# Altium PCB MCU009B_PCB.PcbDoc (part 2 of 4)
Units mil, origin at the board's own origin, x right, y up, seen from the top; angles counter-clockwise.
Board outline 2657.23 x 2215.46 mil, 10 copper layers (Top Layer, Internal-Plane 2, Mid-Layer 3, Mid-Layer 4, Internal-Plane 5, Internal-Plane 6, Mid-Layer 7, Mid-Layer 8, Internal-Plane 9, Bottom Layer), stack 60.8 mil thick; 232 components, 196 nets, 851 pads, 493 vias.

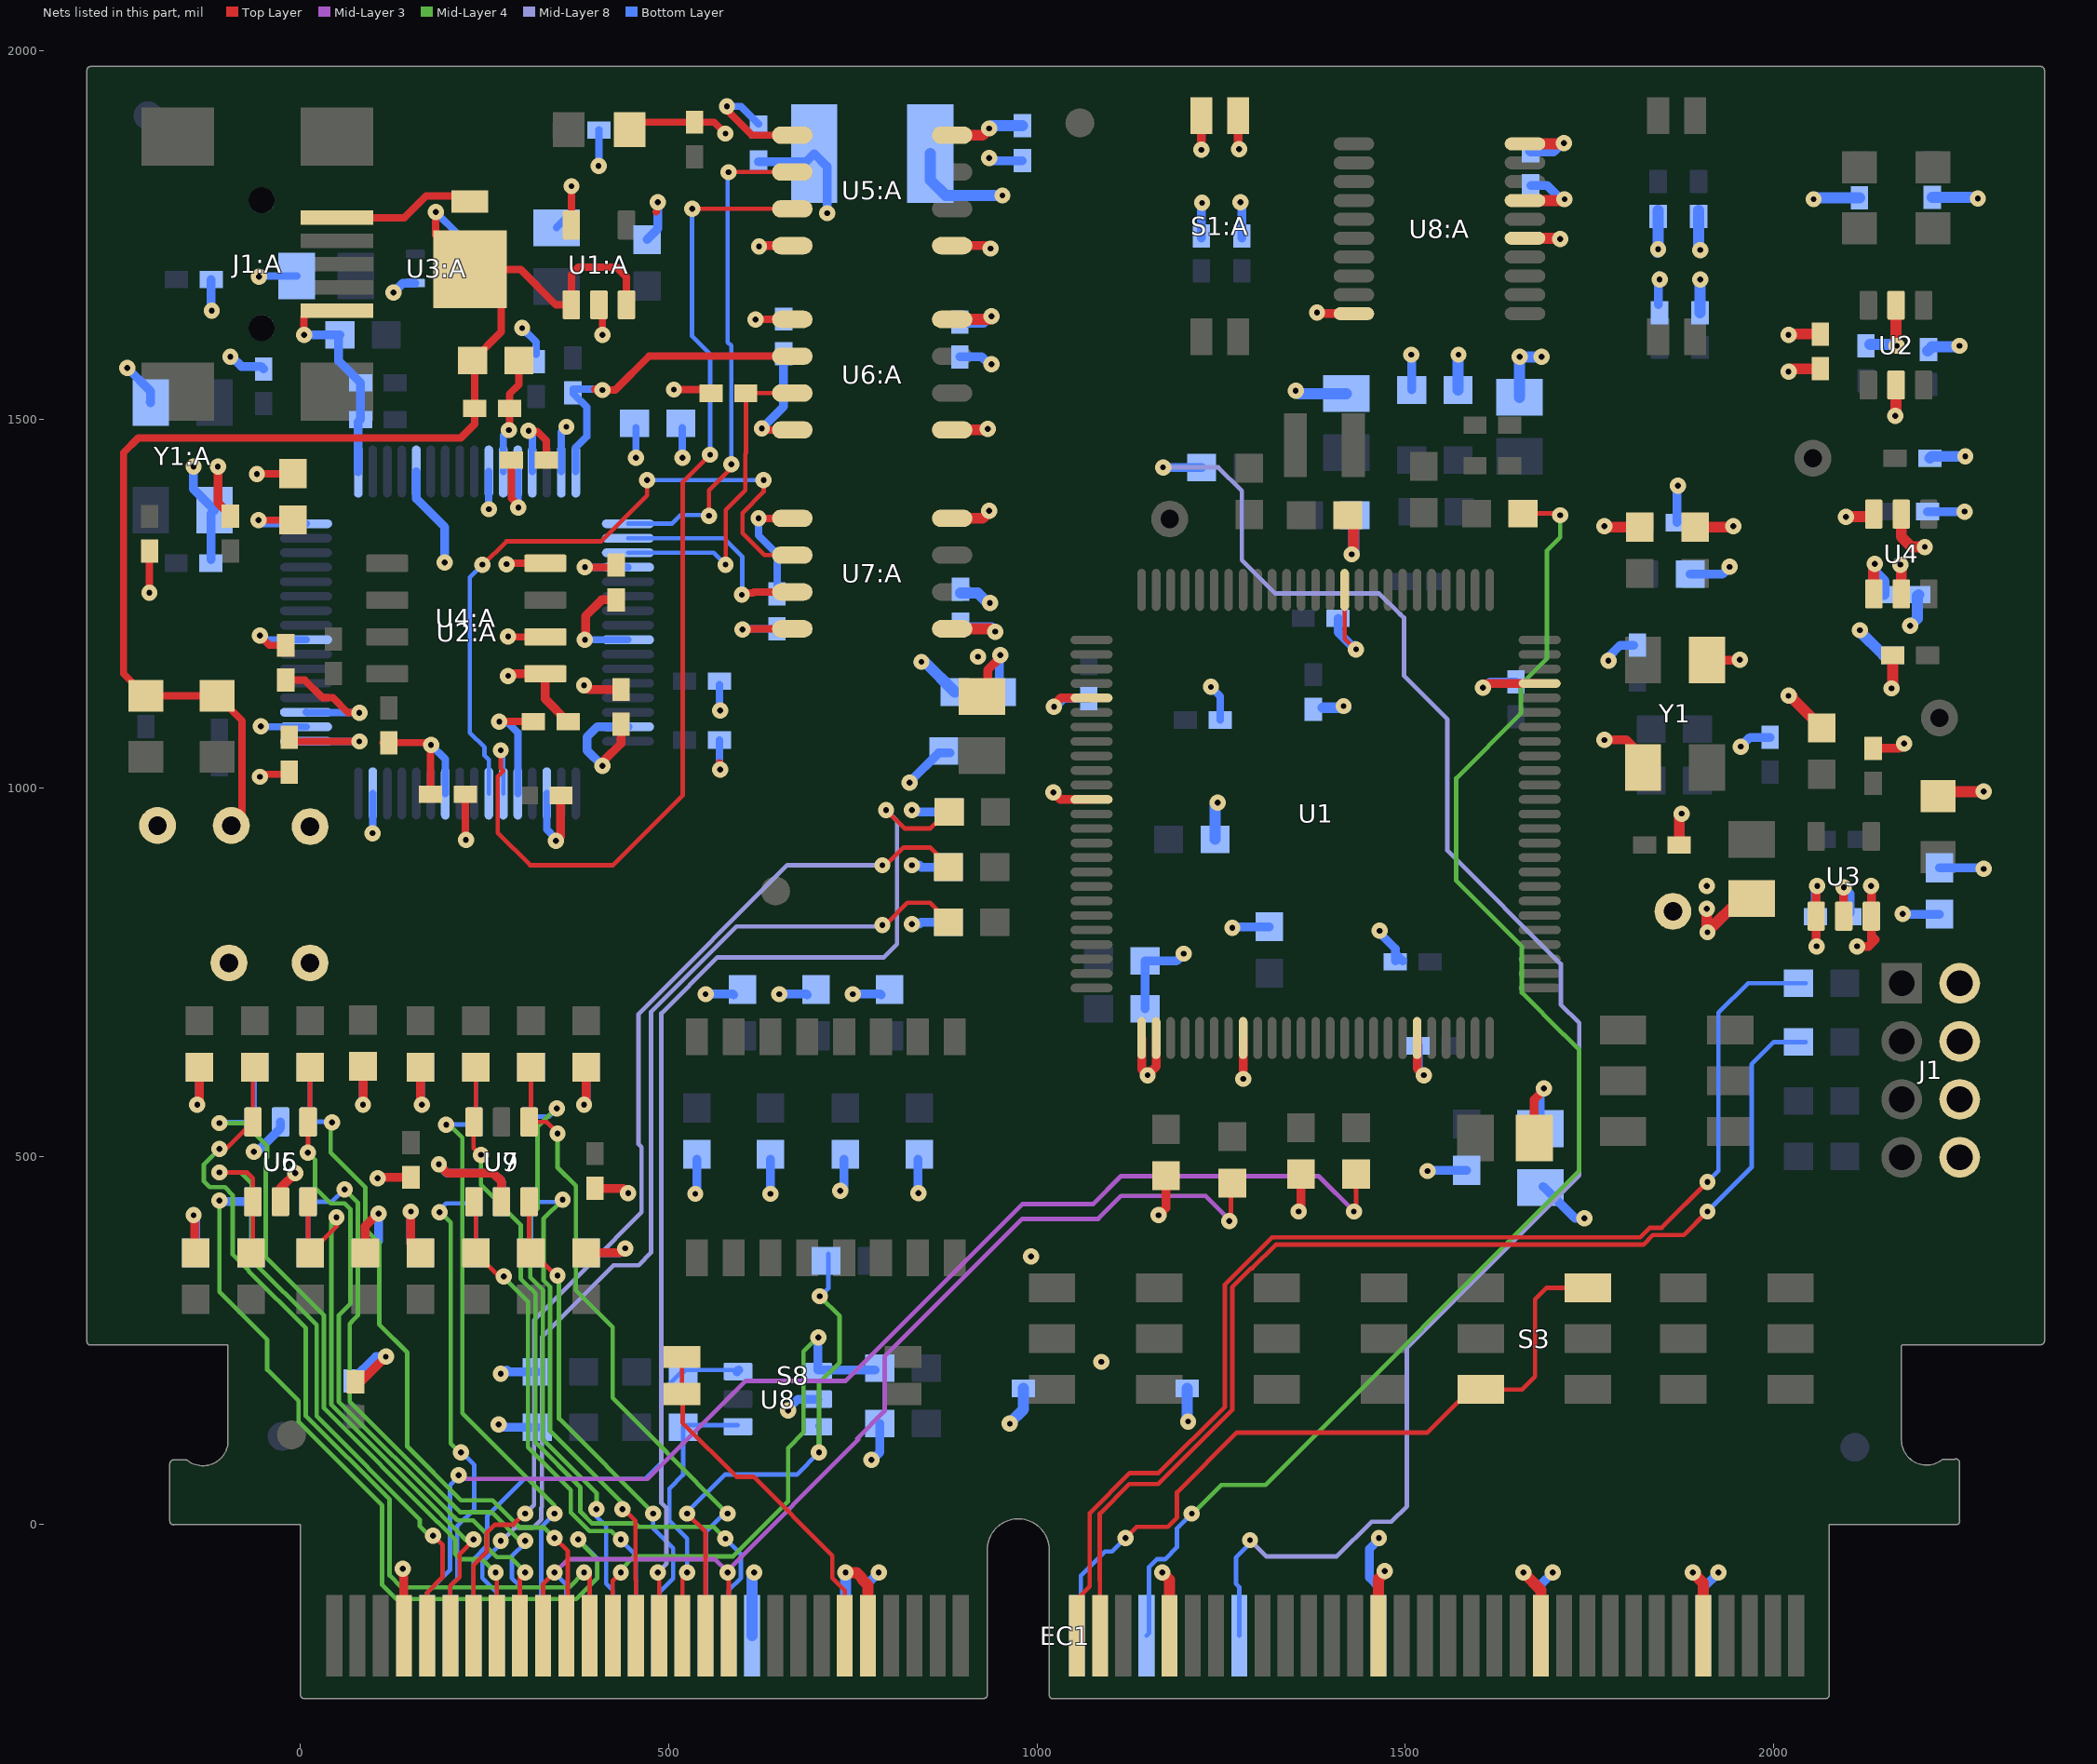
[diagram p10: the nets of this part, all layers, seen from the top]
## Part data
C1 C2 C8 C20 C21 C24 C27: library part CMP-0007318-5, "CAP, CERM, 10 uF, 10 V, +/- 20%, X5R, 0603", Cap_Case=0603, Manufacturer=MuRata, TempCo=X5R, Tolerance_%=20%, Value1=Unknown, Value2=10V, ValueDisplayed=10uF
C1:A C3 C4 C5 C6 C6:A C7:A C8:A C9 C9:A C10:A C11:A C12:A C14 C14:A C15 C16 C16:A C17 C18 C19:A C20:A C21:A C22:A C23:A C24:A C25 C25:A C31 C32 C33: library part CMP-0006629-2, "CAP, CERM, 0.1 uF, 10 V, +/- 10%, X7R, 0402", Cap_Case=0402, Manufacturer=MuRata, Supplier Part Number 1=GRM155R71A104KA01D-ND, TempCo=X7R, Tolerance_%=10%, Value1=Unknown, Value2=10V, ValueDisplayed=0.1uF
C2:A C3:A C5:A C13:A C15:A: library part CMP-0007312-5, "CAP, CERM, 4.7 uF, 6.3 V, +/- 20%, X5R, 0603", Cap_Case=0603, Manufacturer=MuRata, Supplier Part Number 1=490-5421-1-ND, TempCo=X5R, Tolerance_%=20%, Value1="0.001 ohm", Value2=6.3V, ValueDisplayed=4.7uF
C4:A C26 C29 C30: library part CMP-0006639-2, "CAP, CERM, 0.01 uF, 16 V, +/- 10%, X7R, 0402", Cap_Case=0402, Manufacturer=MuRata, Supplier Part Number 1=490-1313-1-ND, TempCo=X7R, Tolerance_%=10%, Value1=Unknown, Value2=16V, ValueDisplayed=0.01uF
C7: library part CMP-0008285-2, "CAP, CERM, 10 uF, 10 V, +/- 10%, X5R, 0805", Cap_Case=0805, Manufacturer=MuRata, Supplier Part Number 1=490-1709-1-ND, TempCo=X5R, Tolerance_%=10%, Value1="0.002 ohm", Value2=10V, ValueDisplayed=10uF
C10 C11 C12 C13 C19 C60 C61: library part CMP-0007323-5, "CAP, CERM, 2.2 uF, 10 V, +/- 10%, X5R, 0603", Cap_Case=0603, Manufacturer=MuRata, Supplier Part Number 1=490-1545-1-ND, TempCo=X5R, Tolerance_%=10%, Value1=Unknown, Value2=10V, ValueDisplayed=2.2uF
C17:A C18:A: library part CMP-0006443-2, "CAP, CERM, 27 pF, 50 V, +/- 5%, C0G/NP0, 0402", Cap_Case=0402, Manufacturer=MuRata, Supplier Part Number 1=14T3294, TempCo=C0G/NP0, Tolerance_%=5%, Value1=Unknown, Value2=50V, ValueDisplayed=27pF
C22 C23: library part CMP-0006420-2, "CAP, CERM, 15 pF, 50 V, +/- 5%, C0G/NP0, 0402", Cap_Case=0402, Manufacturer=MuRata, Supplier Part Number 1=81-GRM1555C1H150JA1D, TempCo=C0G/NP0, Tolerance_%=5%, Value1=Unknown, Value2=50V, ValueDisplayed=15pF
C26:A: library part CMP-0009297-2, "CAP, CERM, 0.01 uF, 1500 V, +/- 10%, X7R, 1812", Cap_Case=1812, Manufacturer=AVX, Supplier Part Number 1=478-4735-1-ND, TempCo=X7R, Tolerance_%=10%, Value1="0.05 ohm", Value2=1500V, ValueDisplayed=0.01uF
C28: library part CMP-0006638-2, "CAP, CERM, 1000 pF, 16 V, +/- 10%, X7R, 0402", Cap_Case=0402, Manufacturer=MuRata, Supplier Part Number 1=GRM155R71C102KA01D-ND, TempCo=X7R, Tolerance_%=10%, Value1=Unknown, Value2=16V, ValueDisplayed=1000pF
C34 C35 C36 C37 C38 C39 C40: library part CMP-0007209-4, "CAP, CERM, 330 pF, 50 V, +/- 5%, C0G/NP0, 0603", Cap_Case=0603, Manufacturer=MuRata, Supplier Part Number 1=490-1439-1-ND, TempCo=C0G/NP0, Tolerance_%=5%, Value1=Unknown, Value2=50V, ValueDisplayed=330pF
C41 C42 C43 C44 C45 C46 C47 C48 C49 C50 C51 C52 C53 C54 C55 C56 C57 C58 C59: library part CMP-0007378-5, "CAP, CERM, 0.1 uF, 16 V, +/- 10%, X7R, 0603", Cap_Case=0603, Manufacturer=MuRata, Supplier Part Number 1=490-1532-1-ND, TempCo=X7R, Tolerance_%=10%, Value1=Unknown, Value2=16V, ValueDisplayed=0.1uF
D1 D2:A: library part CMP-0002960-2, "LED, Bright Green, SMD", Color="Bright Green", Manufacturer="Wurth Elektronik", Power_TotalModule=72mW, Supplier Part Number 1=732-4986-1-ND, Value1=0.072W, Value2=2V
D1:A: library part CMP-0028747-1, "Diode, Schottky, 10 V, 1 A, AEC-Q101, POWERMITE", Manufacturer="ON Semiconductor", Supplier Part Number 1=MBRM110ET1GOSCT-ND, Value1=1A, Value2=0.53V
D2 D3: library part CMP-0002951-2, "LED, Red, SMD", Color=Red, Manufacturer="Wurth Elektronik", Power_TotalModule=72mW, Supplier Part Number 1=732-4985-1-ND, Value1=0.072W, Value2=1.9V
D3:A D4:A: library part CMP-0002959-2, "LED, Blue, SMD", Color=Blue, Manufacturer="Wurth Elektronik", Power_TotalModule=105mW, Supplier Part Number 1=732-4982-1-ND, Value1=0.105W, Value2=3.2V
EC1: library part CMP-0003813-2, "C2000 controlCARD-120HSEC Edge Connector for Samtec HSEC8-160-01-L-DV-A-BL", Manufacturer=Any
FID1 FID2 FID3 FID4 FID5 FID6: library part CMP-0077181-1, "Fiducial mark.  There is nothing to buy or mount.", Manufacturer=N/A
J1: library part CMP-0055568-1, "Header, 2mm, 4x2, Tin, TH", Color=Black, Current_A=3.2A, Manufacturer=Samtec, Supplier Part Number 1=SAM1177-04-ND
J1:A: library part CMP-0054809-1, "Connector, Receptacle, USB Mini B 2.0, SMT", Color=Black, Current_A=1A, Manufacturer="Wurth Elektronik", Supplier Part Number 1=732-2109-1-ND, Voltage_V=30V
L1: library part CMP-0003363-1, "Ferrite Bead, 220 ohm @ 100 MHz, 2 A, 0805", Manufacturer=MuRata, Supplier Part Number 1=490-1054-1-ND, Value1="0.045 ohm", Value2=2A, ValueDisplayed="220 ohm"
L1:A L2:A: library part CMP-0003398-1, "Ferrite Bead, 600 ohm @ 100 MHz, 0.5 A, 0805", Manufacturer="Laird-Signal Integrity Products", Supplier Part Number 1=240-2399-1-ND, Value1="0.3 ohm", Value2=0.5A, ValueDisplayed="600 ohm"
L2: library part CMP-0003306-1, "Ferrite Bead, 60 ohm @ 100 MHz, 3 A, 0805", Manufacturer="Taiyo Yuden", Supplier Part Number 1=587-1932-1-ND, Value1="0.025 ohm", Value2=3A, ValueDisplayed="60 ohm"
L3: library part CMP-0058752-1, "Inductor, Multilayer, Ferrite, 2.2 uH, 1.3 A, 0.08 ohm, SMD", Manufacturer=MuRata, Supplier Part Number 1=490-5114-1-ND, Value1="0.08 ohm", Value2=1.3A, ValueDisplayed=2.2uH
Logo1: library part CMP-0074838-1, "Texas Instrument Corporate Signature"
Logo2: library part CMP-0074769-1
Logo3: library part CMP-0074847-1, "FCC_disclaimer"
LOGO4: library part CMP-0074844-1
R1 R2: library part CMP-0026938-5, "RES, 4.7 k, 5%, 0.063 W, AEC-Q200 Grade 0, 0402", Manufacturer=Vishay-Dale, Power_W=63mW, Supplier Part Number 1=541-4.7KJCT-ND, TempCo="200 ppm/C", Tolerance_%=5%, Value2=0.063W, Value_Code=4k70, ValueDisplayed=4.7k
R1:A R10 R11 R23: library part CMP-0026962-3, "RES, 680, 5%, 0.063 W, AEC-Q200 Grade 0, 0402", Manufacturer=Vishay-Dale, Power_W=63mW, Supplier Part Number 1=541-680JCT-ND, TempCo="200 ppm/C", Tolerance_%=5%, Value2=0.063W, Value_Code=680R, ValueDisplayed=680
R2:A R4:A R8 R9 R9:A R15:A R16:A: library part CMP-0026825-5, "RES, 10 k, 5%, 0.063 W, AEC-Q200 Grade 0, 0402", Manufacturer=Vishay-Dale, Power_W=63mW, Supplier Part Number 1=541-10KJCT-ND, TempCo="200 ppm/C", Tolerance_%=5%, Value2=0.063W, Value_Code=10k0, ValueDisplayed=10k
R3 R4 R5 R6 R7 R16 R17 R18 R19 R21 R22 R28 R32 R35 R36 R37 R38 R39 R40 R41 R42 R43 R44 R45 R46 R47 R48 R49 R50 R51 R52 R53 R54 R55 R56 R57 R58 R59 R60 R61 R62 R63 R64: library part CMP-0025697-4, "RES, 0, 5%, 0.1 W, AEC-Q200 Grade 0, 0603", Manufacturer=Vishay-Dale, Power_W=100mW, Supplier Part Number 1=541-0.0GCT-ND, TempCo="200 ppm/C", Tolerance_%=5%, Value2=0.1W, Value_Code=0000, ValueDisplayed=0
R3:A R6:A R12:A R13:A R29: library part CMP-0026822-3, "RES, 0, 5%, 0.063 W, AEC-Q200 Grade 0, 0402", Manufacturer=Vishay-Dale, Power_W=63mW, Supplier Part Number 1=541-0.0JCT-ND, TempCo="200 ppm/C", Tolerance_%=5%, Value2=0.063W, Value_Code=0000, ValueDisplayed=0
R5:A R7:A R8:A R11:A: library part CMP-0026852-3, "RES, 1.0 k, 5%, 0.063 W, AEC-Q200 Grade 0, 0402", Manufacturer=Vishay-Dale, Power_W=63mW, Supplier Part Number 1=541-1.0KJCT-ND, TempCo="200 ppm/C", Tolerance_%=5%, Value2=0.063W, Value_Code=1k00, ValueDisplayed=1.0k
R10:A R27 R30 R31 R33 R34: library part CMP-0026890-5, "RES, 2.2 k, 5%, 0.063 W, AEC-Q200 Grade 0, 0402", Manufacturer=Vishay-Dale, Power_W=63mW, Supplier Part Number 1=541-2.2KJCT-ND, TempCo="200 ppm/C", Tolerance_%=5%, Value2=0.063W, Value_Code=2k20, ValueDisplayed=2.2k
R12 R13: library part CMP-0026826-2, "RES, 10 M, 5%, 0.063 W, AEC-Q200 Grade 0, 0402", Manufacturer=Vishay-Dale, Power_W=63mW, Supplier Part Number 1=541-10MJCT-ND, TempCo="200 ppm/C", Tolerance_%=5%, Value2=0.063W, Value_Code=10M0, ValueDisplayed=10M
R14 R15 R20: library part CMP-0020442-3, "RES, 0, 5%, 0.125 W, AEC-Q200 Grade 0, 0805", Manufacturer=Vishay-Dale, Power_W=125mW, Supplier Part Number 1=541-0.0ACT-ND, TempCo="200 ppm/C", Tolerance_%=5%, Value2=0.125W, Value_Code=0000, ValueDisplayed=0
R14:A: library part CMP-0026834-3, "RES, 12 k, 5%, 0.063 W, AEC-Q200 Grade 0, 0402", Manufacturer=Vishay-Dale, Power_W=63mW, Supplier Part Number 1=541-12KJCT-ND, TempCo="200 ppm/C", Tolerance_%=5%, Value2=0.063W, Value_Code=12k0, ValueDisplayed=12k
R24: library part CMP-0026129-2, "RES, 1.00, 1%, 0.063 W, AEC-Q200 Grade 0, 0402", Manufacturer=Vishay-Dale, Power_W=63mW, Supplier Part Number 1=541-1.00LLCT-ND, TempCo="100 ppm/C", Tolerance_%=1%, Value2=0.063W, Value_Code=1R00, ValueDisplayed=1.00
R25 R26: library part CMP-0026949-3, "RES, 56 k, 5%, 0.063 W, AEC-Q200 Grade 0, 0402", Manufacturer=Vishay-Dale, Power_W=63mW, Supplier Part Number 1=541-56KJCT-ND, TempCo="200 ppm/C", Tolerance_%=5%, Value2=0.063W, Value_Code=56k0, ValueDisplayed=56k
S1 S1:A S8: library part CMP-0002230-1, "Switch, SPST, 2 Pos, 25mA, 24VDC, SMD", CurrentRating_mA=25A, Manufacturer="CTS Electrocomponents", Supplier Part Number 1=CT2182LPST-ND
S2 S3 S4: library part CMP-0002123-2, "SLIDE SWITCH DPDT  .1A, SMT", CurrentRating_mA=100A, Manufacturer="Copal Electronics", Supplier Part Number 1=CAS220JCT-ND
S5 S6: library part CMP-0002233-1, "Switch, Dual SPDT,  2 Pos, 0.1A, 6VDC, SMD", CurrentRating_mA=100A, Manufacturer="Copal Electronics", Supplier Part Number 1=CASD20JCT-ND
S7: library part CMP-0002229-1, "Switch, SPST, 8 Pos, 25mA, 24VDC, SMD", CurrentRating_mA=25A, Manufacturer="CTS Electrocomponents", Supplier Part Number 1=CT2188LPST-ND
TP1 TP1:A TP2 TP2:A TP3 TP3:A TP4 TP5 TP6: library part CMP-0078143-2, "TEST POINT.  No entry in BOM.", Manufacturer=N/A
U1: library part CMP-0078352-1, "Piccolo Microcontroller, PZ0100A (LQFP-100)", Alternate Manufacturer="Texas Instruments"
U1:A: library part CMP-0073823-1, "Low-Noise, High PSRR, RF 200-mA Low-Dropout Linear Regulators, DBV0005A (SOT-23-5)", Alternate Manufacturer="Texas Instruments", Alternate PartNumber=TPS73033DBVT
U2: library part CMP-0051789-2, "Dual Buffer/Driver with Open-Drain Output, DBV0006A, LARGE T&R", F @ Nom Voltage(Max)(Mhz)=150, Generic Part Number=SN74LVC2G07, ICC @ Nom Voltage(Max)(mA)=0.01, Manufacturer="Texas Instruments", Operating Temperature Range(C)="-40 to 125", Rating=Catalog, tpd @ Nom Voltage(Max)(ns)=8.6,4.4,3.7,2.9, Voltage(Nom)(V)=1.8,2.5,3.3,5
U2:A: library part CMP-0004796-1, "Dual High Speed USB To Multipurpose UART/FIFO IC, LQFP-64", Manufacturer=FTDI, Supplier Part Number 1=768-1024-1-ND
U3: library part CMP-0036866-2, "Single Output Low Noise LDO, 400 mA, Fixed 3.3 V Output, 1.7 to 5.5 V Input, with Reverse Current Protection, 5-pin SOT-23 (DBV), -40 to 85 degC, Green (RoHS & no Sb/Br)", Alternate Manufacturer="Texas Instruments", Alternate PartNumber=TPS73633DBVT, Rating=Catalog
U3:A: library part CMP-0043096-2, "Low-Capacitance + / - 15 kV ESD-Protection Array for High-Speed Data Interfaces, 2 Channels, -40 to +85 degC, 5-pin SOT (DRL), Green (RoHS & no Sb/Br)", Breakdown Voltage(Min)(V)=11, IO Capacitance(Typ)(pF)=1.5, IO Leakage Current(nA)=1, Manufacturer="Texas Instruments"
U4: library part CMP-0067340-2, "High-Accuracy, Fixed-Threshold OV/UV Monitor, DDC0006A (SOT-23-T-6)", Alternate Manufacturer="Texas Instruments", Alternate PartNumber=TPS3702CX33DDCT
U4:A: library part CMP-0005261-2, "2K Microwire Compatible Serial EEPROM, SOIC-8", Manufacturer=Microchip, Supplier Part Number 1=93LC56C-I/SN-ND
U5 U6 U7 U8 U9: library part CMP-0066599-1, "Automotive Low-Capacitance 4-Channel +/-15-kV ESD Protection Array for High-Speed Data Interfaces, DBV0006A (SOT-23-6)", Alternate Manufacturer="Texas Instruments"
U5:A U6:A U7:A: library part CMP-0029375-1, "25 Mbps Dual Channels, 2 / 0, Digital Isolator, 3.3 V / 5 V, -40 to +125 degC, 8-pin SOIC (D), Green (RoHS & no Sb/Br)", Insulation Rating(VRMS)=2500, Manufacturer="Texas Instruments", Rating=Catalog, Supply Voltage(s)(V)="3.3, 5"
U8:A: library part CMP-0047070-3, "Octal Buffer/Driver With 3-State OUtputs, PW0020A (TSSOP-20)", Alternate Manufacturer="Texas Instruments", Alternate PartNumber=SN74ALVC244PW, F @ Nom Voltage(Max)(Mhz)=100, Generic Part Number=SN74ALVC244, ICC @ Nom Voltage(Max)(mA)=0.024, Operating Temperature Range(C)="-40 to 85", Rating=Catalog, tpd @ Nom Voltage(Max)(ns)=4.4,3.1,2.8, Voltage(Nom)(V)=1.8,2.5,2.7,3.3
Y1: library part CMP-0080365-1, "Crystal, 20 MHz, 25 ppm, 18, SMD", Frequency Stability="30 ppm", Frequency Tolerance="25 ppm", Load Capacitance=18, Manufacturer="ECS Inc.", PartNumber=ECS-200-18-30B-AGN-TR, Supplier Part Number 1=XC2693CT-ND
Y1:A: library part CMP-0004646-3, "Crystal, 12 MHz, 20pF, SMD", Frequency Stability=+/-50ppm, Manufacturer="ECS Inc.", PartNumber=ECS-120-20-30B-TR, Supplier Part Number 1=XC1118CT-ND
ZZ1: library part CMP-0077236-1
ZZ2: library part CMP-0077237-1
ZZ3: library part CMP-0077238-1

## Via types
v1: diameter 22, hole 8, Top Layer to Bottom Layer, 414 vias
v2: diameter 22, hole 8, Top Layer to Bottom Layer, tented both sides, 79 vias

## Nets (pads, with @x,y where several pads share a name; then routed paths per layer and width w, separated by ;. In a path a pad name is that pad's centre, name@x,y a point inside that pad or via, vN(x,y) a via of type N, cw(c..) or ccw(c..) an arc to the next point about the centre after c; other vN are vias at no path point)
3V3: C7.2 C9.1 C10.2 C19.2 C20:A.1 C22:A.1 C24:A.1 C25:A.2 C31.1 L1.1 L2.1 R1.1 R2.2 R8.2 R9.2 R10.1 R11.1 R12.2 R13.2 R14.1 R15:A.2 R16:A.2 R20.2 R25.1 R26.2 R27.2 R28.2 R30.2 R31.2 TP2.1 U2.5 U4.3 U4.4 U4.5 U5:A.8 U6:A.8 U7:A.1 U8:A.20 | length 1989.6
  Top Layer w12: R1.1@75,193.62 81.62,193.62 v1(116,228) v1@118,230 ; L2.1@933.1,1127.4 933.1,1160.1 v1@949,1176 ; L1.1@1675,525 1675,577 v1@1689,591
  Top Layer w15: U7:A.1@883.5,1215.87 936.13,1215.87 v1@938,1214 ; U6:A.8@883.5,1635.87 933.87,1635.87 v1(938,1640) ; U5:A.8@883.5,1885.87 925.87,1885.87 v1(935,1895) ; U8:A.20@1662.34,1874 1714,1874 v1(1715,1875) ; R31.2@1871.72,922.4 1871.72,961.72 v1(1875,965) ; R28.2@1893.1,1353.9 v1@1944,1353.9 ; v1(1909,836) 1909,806 v1@1910,805 ; v1(1910,804) v1@1910,805 ; v1@1944,1356 v1(1945,1355) ; v1@1945,1353.9 1945.9,1353.9 v1@1946,1354 ; R20.2@1970,850 1955,850 v1@1910,805 ; v1(2020,1615) 2021.02,1616.02 C9.1@2063.1,1616.02 ; v1(2098,1368) 2135,1368 U4.3@2135.7,1368.7 ; U4.4@2135.7,1263.27 2135.7,1302.7 2136,1303 v1@2137,1303 ; U4.3@2135.7,1371.53 U4.3@2135.7,1368.7 ; U4.3@2137,1370 U4.3@2135.7,1368.7 ; U2.5@2165.91,1655 2165.91,1603.09 v1@2167,1602 ; v1(2172,1303) 2173.1,1301.9 U4.5@2173.1,1263.27
  Bottom Layer w12: R2.2@70.2,195.28 70,195.47 102.53,228 v1(116,228) ; v1@949,1180 949,1144 946,1141 C10.2@949.6,1137.4 ; R15:A.2@1223.1,1746.02 1223.1,1748.02 1223.1,1793.1 v1(1224,1794) ; v1(1276,1795) 1278.1,1792.9 1278.1,1748.02 R16:A.2@1278.1,1746.02 ; C7.2@1683.1,537.4 1683.1,587.1 v1(1688,592)
  Bottom Layer w15: C22:A.1@895,1632.24 927.24,1632.24 935,1640 v1(938,1640) ; C24:A.1@896.22,1217.24 937.76,1217.24 v1(943,1212) ; v1(935,1895) 938.62,1898.62 C20:A.1@980,1898.62 ; v1@962,137 981.38,156.38 R8.2@981.38,185 ; R9.2@1203.62,185 1203.62,141.38 v1(1205,140) ; C19.2@1571.5,1540 1571.5,1587.5 v1(1572,1588) ; R14.1@1655,1530 v1(1655,1585) v1@1684,1585 ; C25:A.2@1670,1864.62 1700.62,1864.62 v1@1710,1874 ; v1@1842,1727 1843.1,1728.1 1843.1,1776.78 R25.1@1843.1,1783.78 ; R26.2@1898.1,1783.78 1898.1,1776.78 1898.1,1731.9 v1(1900,1730) ; v1(2054,1799) 2055.86,1800.86 R10.1@2116.34,1800.85 ; v1@2115,1214 2149,1180 R30.2@2161.38,1180 ; R12.2@2130.23,1601.79 2165.21,1601.79 v1(2167,1600) ; v1@2137,1303 2137,1293 2149.48,1280.52 C31.1@2149.48,1262.4 ; R13.2@2209,1593 2214.62,1598.62 2250.62,1598.62 v1(2252,1600) ; R27.2@2211.72,1447.4 2214.32,1450 v1(2260,1450) ; R11.1@2215.08,1801.37 2275.63,1801.37 v1(2277,1800)
  other v1: 963,137 1909,867 920,1178 950,1180 2117,1214 2137,1304 1685,1585 1843,1731
EMU_1V8: C5:A.2 C6:A.2 C7:A.2 C8:A.2 U2:A.12 U2:A.37 U2:A.49 U2:A.64 | length 609.2
  Top Layer w10: v2(-56.72,1363.35) C5:A.2@-19.8,1363.35 ; C7:A.2@-17.19,1065.68 -14.33,1062.82 62.58,1062.82 ; 7.72,1063.23 62.17,1063.23 62.58,1062.82 ; v2(80,1063) 62.77,1063 62.58,1062.82 ; v2(270,1090) C8:A.2@316.38,1090 ; C6:A.2@286.57,1444.84 286.57,1393.06 295.88,1383.75 v2(295.88,1380.55) v2@295.12,1381.31
  Bottom Layer w10: v2(-56.72,1363.35) -55.68,1364.38 -55.68,1361.68 -52.5,1358.5 U2:A.64@7.72,1358.5 ; U2:A.49@7.72,1063.23 79.77,1063.23 v2(80,1063) ; v2(270,1090) 280,1090 295.12,1074.88 U2:A.37@295.12,992.36 ; v2@295.12,1381.31 U2:A.12@295.12,1429.37
EMU_3V3: C2:A.1 C9:A.2 C10:A.2 C11:A.2 C12:A.2 C19:A.2 C21:A.2 C23:A.2 L1:A.2 L2:A.2 R1:A.1 R2:A.2 R4:A.2 R9:A.1 R11:A.1 TP2:A.1 U1:A.5 U2:A.20 U2:A.31 U2:A.42 U2:A.50 U2:A.56 U4:A.6 U4:A.8 U5:A.1 U6:A.1 U7:A.8 | length 1573.2
  Top Layer w10: v2(-55.01,1206.64) -41.83,1193.46 C10:A.2@-19.8,1193.46 ; R9:A.1@112.18,1061.44 174.32,1061.44 v2(177.31,1058.45) 176.73,1057.87 C12:A.2@176.73,991.34 ; v2@281.2,1304.84 U4:A.8@332.48,1304.84 ; v2@282.79,1204.84 U4:A.6@332.48,1204.84 ; v2(367.99,1816.64) 367.79,1816.44 U1:A.5@367.79,1763.98 U1:A.5@371.93,1759.84 ; v2(386.22,1299.45) C9:A.2@425.79,1299.45 ; v2(506.99,1540.64) 552.37,1540.64 R2:A.2@552.6,1540.87 ; v2@576.5,1922.5 613.13,1885.87 U5:A.1@668.94,1885.87 ; v2(600,1215) 612.6,1215 613.61,1216.02 ; v2@617.22,1635.87 U6:A.1@655.6,1635.87 ; v2(617.99,1635.64) 655.37,1635.64 U6:A.1@655.6,1635.87 ; U7:A.8@646.99,1216.02 613.61,1216.02 ; U6:A.1@655.99,1636.26 U6:A.1@655.6,1635.87 ; U7:A.8@668.94,1215.87 613.76,1215.87 613.61,1216.02 ; U6:A.1@668.94,1635.87 U6:A.1@655.6,1635.87
  Top Layer w12: v2(410,1030) 410,1035 435.2,1060.2 C11:A.2@435.2,1086.22
  Bottom Layer w10: v2(-56.01,1693.64) -54.8,1694.84 L2:A.2@-4.8,1694.84 ; v2@-55,1085 -52.91,1082.91 U2:A.50@7.72,1082.91 ; v2(-55.01,1206.64) -49.37,1201 U2:A.56@7.72,1201.02 ; v2@177.31,1058.26 196.69,1038.88 U2:A.42@196.69,992.36 ; v2(301.07,1624.04) 320.2,1604.91 R11:A.1@320.2,1588.46 ; L1:A.2@347.57,1760.29 367.99,1780.71 v2(367.99,1816.64) ; v2(386.22,1299.45) U2:A.20@444.72,1299.45 ; v2@405.09,1844.32 R1:A.1@405.09,1892.91 ; v2(518.49,1448.13) C2:A.1@518.49,1488.64 ; v2@568.82,1110.81 R4:A.2@568.82,1139.84 ; v2(579,1925) 598,1925 C19:A.2@622,1901 ; v2(600,1215) 601.02,1216.02 C23:A.2@646.99,1216.02 ; v2(617.99,1635.64) 618.61,1636.26 C21:A.2@655.99,1636.26
  Bottom Layer w12: v2(410,1030) 389.03,1050.97 389.03,1069.03 402.91,1082.91 U2:A.31@444.72,1082.91
  other v2: -53.73,1083.57 570,1105 281.99,1205.64 279.99,1303.64 404.72,1843.95
EMU_5V0: C1:A.2 C3:A.1 D1:A.1 D3:A.2 D4:A.2 TP1:A.1 U1:A.1 U1:A.3 U3:A.1 | length 1863.2
  Top Layer w10: TP1:A.1@-91,952 -79,964 -79,1090.97 D4:A.2@-113.01,1124.98 -209.63,1124.98 D3:A.2@-209.8,1124.8 -240,1155 -240,1455 -220.22,1474.78 217.5,1474.78 236.57,1493.86 C1:A.2@236.57,1514.84 236.57,1576.97 C3:A.1@233.7,1579.84 272.69,1618.83 D1:A.1@272.69,1703.05 ; v2(183.66,1781.59) 183.66,1750.38 D1:A.1@230.2,1703.84 ; D1:A.1@214.72,1724.53 251.2,1724.53 D1:A.1@272.69,1703.05 ; U1:A.3@442.6,1655.71 442.6,1693.38 429.37,1706.61 377.57,1706.61 367.79,1696.84 U1:A.1@367.79,1655.71 346.9,1655.71 299,1703.6 272.69,1703.6 D1:A.1@272.69,1703.05
  Bottom Layer w10: v2(183.66,1781.59) 214.72,1750.52 U3:A.1@214.72,1724.53
EMU_GND: C1:A.1 C2:A.2 C3:A.2 C4:A.1 C5:A.1 C6:A.1 C7:A.1 C8:A.1 C9:A.1 C10:A.1 C11:A.1 C12:A.1 C13:A.2 C14:A.1 C15:A.2 C16:A.1 C17:A.1 C18:A.1 C19:A.1 C21:A.1 C23:A.1 C26:A.2 D2:A.1 J1:A.5 R5:A.2 R6:A.2 R12:A.1 R13:A.1 R14:A.1 TP3:A.1 U1:A.2 U2:A.1 U2:A.5 U2:A.10 U2:A.11 U2:A.13 U2:A.15 U2:A.25 U2:A.35 U2:A.47 U2:A.51 U3:A.4 U4:A.5 U5:A.4 U6:A.4 U7:A.5 Y1:A.2 Y1:A.4 | length 3004.6
  Top Layer w10: v2(-205,1265) -205,1321.02 C17:A.1@-204.8,1321.22 ; v2(-59,1426) -20.14,1426 C5:A.1@-19.8,1426.34 ; v2@-46.76,1018.44 C7:A.1@-17.19,1018.44 ; C10:A.1@-19.8,1146.22 5.94,1146.22 29.9,1122.26 44.29,1122.26 64.55,1102 v2(80,1102) ; v2(5,1615) 5,1639.06 13.82,1647.87 J1:A.5@49.86,1647.87 ; v2@98.14,938.03 v2@98.27,938.15 ; C12:A.1@223.98,991.34 223.98,930.55 v2@224.87,929.65 ; v2(282.99,1485.64) 283.82,1486.46 C1:A.1@283.82,1514.84 283.82,1534.46 296.69,1547.34 C3:A.2@296.69,1579.84 ; v2(309.8,1484.54) 310.63,1483.71 321.47,1483.71 333.82,1471.37 C6:A.1@333.82,1444.84 ; R13:A.1@352,989.84 R13:A.1@352,991 ; U1:A.2@405.2,1655.71 410,1650.9 v2(410,1615) ; D2:A.1@445,1895 453.46,1903.46 C4:A.1@531.46,1903.46 ; 482.79,1781.74 483.55,1782.5 ; C4:A.1@535,1907 C4:A.1@531.46,1903.46 ; v2@568.82,1033.81 570,1032.63 v2(570,1025) ; v2(577,1888) 561.54,1903.46 C4:A.1@535.2,1903.46 C4:A.1@531.46,1903.46 ; v2(621.97,1365.87) U7:A.5@668.94,1365.87 ; v2(626.37,1487.85) 628.35,1485.87 U6:A.4@668.94,1485.87
  Top Layer w12: v1(-112,1436) -112,1387 R12:A.1@-95,1370 ; v1(282,1152) 284.84,1154.84 U4:A.5@332.48,1154.84 332.48,1120.52 C8:A.1@362,1091 ; v1(347,928) 353,934 R13:A.1@353,991 ; C8:A.1@363.62,1090 C8:A.1@363.62,1091 ; v2(385,1139) 390.54,1133.46 C11:A.1@435.2,1133.46 ; v2(386.22,1200.87) 387.08,1201.72 387.08,1233.2 408.99,1255.12 C9:A.1@428.7,1255.12 ; v2(622.61,1735.03) 623.44,1735.87 U5:A.4@668.94,1735.87
  Bottom Layer w10: U2:A.51@7.72,1102.6 8.31,1102 v2(80,1102) ; v2@98.27,938.15 U2:A.47@98.27,992.36 ; v2@255.75,1379.73 U2:A.10@255.75,1429.37 ; U2:A.11@275.43,1429.37 275.43,1478.08 v2(282.99,1485.64) ; v2(309.8,1484.54) 314.8,1479.54 U2:A.13@314.8,1429.37 ; U2:A.35@334.49,992.36 334.49,943.51 346,932 v1@346,927 ; U2:A.15@354.17,1429.37 354.17,1483.17 v2(361,1490) ; v2@386.22,1201.02 U2:A.25@444.72,1201.02 ; C2:A.2@455.5,1488.64 v2(455.5,1447.9) v2@455.95,1447.44 ; v2@568.82,1033.81 R5:A.2@568.82,1064.84 ; v2(621.97,1365.87) 621.97,1342.64 646.99,1317.61 C23:A.1@646.99,1263.26
  Bottom Layer w12: v2(-235,1570) -203.11,1538.11 Y1:A.2@-203.11,1522.68 Y1:A.2@-204.05,1523.61 ; v2(-145,1436) -145,1405.51 Y1:A.4@-116.5,1377.01 -121.18,1372.32 C14:A.1@-121.18,1309.84 ; R6:A.2@-121.18,1689.84 -121.18,1648.42 v2(-120.28,1647.52) ; v1(-95,1585) -93,1585 -80,1572 -53.38,1572 C18:A.1@-50,1568.62 ; v2(5,1615) 5.16,1614.84 C15:A.2@53.7,1614.84 51.93,1613.07 51.93,1579.49 C16:A.1@81.57,1549.84 R14:A.1@81.57,1499.84 78.58,1496.85 U2:A.1@78.58,1429.37 ; v2(126.39,1672.23) 139.31,1685.16 U3:A.4@155.67,1685.16 ; U2:A.5@157.32,1429.37 157.32,1392.68 196,1354 v2(196,1306) ; v1@346,927 v1(347,928) ; C13:A.2@470.54,1744.14 485,1758.6 v2(485,1795) ; C19:A.1@621.88,1849.74 686.35,1849.74 C26:A.2@697.48,1860.87 715,1843.35 v2(715,1780) ; v2(626.37,1487.85) 655.99,1517.48 C21:A.1@655.99,1589.02
  other v2: 224.68,929.27 97.99,938.5 -55,1015 256.06,1378.28
EMU_SCI-RX: U2:A.38 U5:A.3 | length 1443.1
  Top Layer w6: v2(272,1051) 272,1026.55 275.43,1023.12 267.93,1015.62 267.93,938.94 311.88,895 424.53,895 518.89,989.36 518.89,1414.86 v2(556.16,1452.13) ; v2(531.76,1785.87) U5:A.3@668.94,1785.87
  Bottom Layer w6: v2@272,1050 275.43,1046.57 U2:A.38@275.43,992.36 ; v2(531.76,1785.87) 531.76,1613.03 556.16,1588.63 v2(556.16,1452.13)
EMU_SCI-TX: U2:A.39 U7:A.6 | length 936.4
  Top Layer w6: v2@247,1302 279.64,1334.64 408.39,1334.64 470.5,1396.75 v2(470.5,1417.77) ; v2(628.8,1417.77) 628.8,1401.8 ; 629,1402 628.8,1401.8 ; U7:A.6@668.94,1315.87 629.88,1315.87 600,1345.74 600,1373 628.8,1401.8
  Bottom Layer w6: v2(247,1303) 230,1286 230,1075 250,1055 250,1044 255.75,1038.25 U2:A.39@255.75,992.36 ; v2@470.17,1418.09 v2(470.5,1417.77) v2(628.8,1417.77)
EMU_TCK: R3:A.1 U2:A.16 U6:A.2 | length 455.1
  Top Layer w10: v2@399.41,1541.22 400.63,1540 v2(410,1540) 427.35,1540 473.22,1585.87 U6:A.2@668.94,1585.87
  Bottom Layer w10: U2:A.16@373.86,1429.37 373.86,1462.11 388.79,1477.04 388.79,1516.75 370.2,1535.34 370.2,1541.22 408.78,1541.22 v2(410,1540)
EMU_TDI: U2:A.17 U5:A.2 | length 686.5
  Top Layer w6: v2(554.73,1369.33) 554.73,1404.05 588,1437.32 586.32,1439 v2(585,1439) ; v2@581.22,1835.87 U5:A.2@668.94,1835.87
  Bottom Layer w6: U2:A.17@444.72,1358.5 504.41,1358.5 516.1,1370.19 553.87,1370.19 v2(554.73,1369.33) ; v2@580,1835 580,1605 585,1600 v2(585,1439)
  other v2: 580.99,1835.64
EMU_TDO: U2:A.18 U7:A.7 | length 287.4
  Top Layer w10: v2(599.25,1262.09) 601.73,1264.58 614.42,1264.58 615.71,1265.87 U7:A.7@668.94,1265.87
  Bottom Layer w6: U2:A.18@444.72,1338.82 574.74,1338.82 599.9,1313.66 v2@599.9,1263.08
EMU_TMS: R2:A.1 U2:A.19 U6:A.3 | length 447.8
  Top Layer w6: v2@577.31,1302.67 577.31,1377.38 604,1404.07 604,1453.77 604.84,1454.61 604.84,1535.87 U6:A.3@668.94,1535.87
  Bottom Layer w6: U2:A.19@444.72,1319.13 560.95,1319.13 v2(577.12,1302.96)
EMU_USB_5V0: D1:A.2 J1:A.1 | length 195.6
  Top Layer w10: J1:A.1@49.86,1773.86 141.21,1773.86 170.65,1803.3 222.74,1803.3 D1:A.2@230.2,1795.84
GND: C1.2 C2.2 C3.1 C4.1 C5.1 C6.1 C7.1 C8.2 C9.2 C10.1 C11.1 C12.1 C13.1 C14.2 C15.2 C16.2 C17.2 C19.1 C20:A.2 C22.2 C22:A.2 C23.2 C24.2 C24:A.2 C25.2 C25:A.1 C26.1 C26:A.1 C27.1 C29.1 C30.1 C31.2 C32.2 C33.2 C34.1 C35.1 C36.1 C37.1 C38.1 C39.1 C40.1 C41.1 C42.1 C43.1 C44.1 C45.1 C46.1 C47.1 C48.2 C49.2 C50.2 C51.2 C52.2 C53.2 C54.2 C55.2 C56.2 C57.2 C58.2 C59.2 C60.1 C61.1 D1.1 EC1.7 EC1.38 EC1.46 EC1.47 EC1.65 EC1.83 EC1.97 EC1.111 J1.2 J1.4 J1.6 J1.8 R15.1 R17.1 R32.2 R33.2 R34.1 R55.1 R56.1 R57.1 R58.1 R59.1 S1:A.3 S1:A.4 TP4.1 U1.5 U1.12 U1.26 U1.27 U1.33 U1.45 U1.72 U1.86 U2.2 U3.2 U4.2 U5.2 U5:A.5 U6.2 U6:A.5 U7.2 U7:A.4 U8.2 U8:A.10 U8:A.15 U8:A.17 U9.2 Y1.2 Y1.4 | length 6197.3
  Top Layer w6: U1.86@1417.47,1268.7 1417.47,1202.53 v1@1432.5,1187.5
  Top Layer w12: v1(-145,420) -143.1,418.1 C48.2@-143.1,369.1 ; v1(-140,570) -136.9,573.1 C51.2@-136.9,620.9 ; U5.2@-26.9,438.27 -26.9,457.1 v1(-7,477) v1@-6,476 ; v1(85,570) C50.2@85,622.01 ; C49.2@88.1,368.9 C49.2@88.1,371.9 ; C49.2@90,370 C49.2@88.1,371.9 ; v1@101,468 104.38,471.38 C32.2@150,471.38 ; v1@107,424 88.1,405.1 C49.2@88.1,371.9 ; v1(139,-60) 139,-69 140.55,-70.55 EC1.7@140.55,-150.67 ; v1(150,425) 150,381 C56.2@161,370 ; C59.2@163.1,620.9 163.1,576.9 v1@170,570 ; v1(188,489) 200,477 262,477 273.1,465.9 U9.2@273.1,438.27 ; v1(385,570) 388.1,573.1 C58.2@388.1,620.9 ; C57.2@388.1,368.9 434.9,368.9 v1(441,375) ; C33.2@400,456.38 438.62,456.38 v1(445,450) ; U5:A.5@883.5,1735.87 933.13,1735.87 v1(937,1732) ; v1(1022,994) 1031.75,984.25 U1.12@1073.97,984.25 ; v1(1023,1110) 1023,1113 1032.04,1122.04 U1.5@1073.97,1122.04 ; U1.26@1141.88,660.43 1141.88,618.12 v1(1150,610) 1161.56,621.56 U1.27@1161.56,660.43 ; v1(1165,420) 1175,430 R58.1@1175,473.5 ; v1(1223,1866) 1223.1,1866.1 S1:A.4@1223.1,1912.4 ; S1:A.3@1273.1,1912.4 1273.1,1867.9 v1(1274,1867) ; U1.33@1279.67,660.43 1279.67,605.33 v1(1280,605) ; v1(1355,425) 1358.1,428.1 R59.1@1358.1,475.9 ; v1(1380,1645) 1381.32,1643.68 U8:A.10@1430.05,1643.68 ; U1.45@1515.9,660.43 1515.9,619.1 v1(1525,610) ; v1@1611.73,1141.73 U1.72@1682.23,1141.73 ; v1(1770,1065) 1800,1065 1821.52,1043.48 Y1.4@1821.52,1027.83 ; v1(1770,1355) 1771.1,1353.9 v1@1776.1,1353.9 ; v1@1775,1172 v1(1775.5,1172.5) ; Y1.2@1908.13,1173.5 1953.5,1173.5 v1(1954,1174) ; U3.2@2095,825.87 v1(2095,865) ; C26.1@2135,1053.62 2170.62,1053.62 v1(2177,1060)
  Top Layer w15: v1(740,-65) 755,-65 762.5,-72.5 762.5,-74.32 770.47,-82.29 EC1.47@770.47,-150.67 ; U7:A.4@883.5,1365.87 925.87,1365.87 935,1375 v1(935,1376) ; U6:A.5@883.5,1485.87 931.87,1485.87 v1(933,1487) ; v1(1170,-65) 1179.92,-74.92 EC1.65@1179.92,-150.67 ; v1@1429.6,1325.6 C2.2@1429.6,1357.4 ; EC1.83@1463.38,-150.67 1463.38,-73.62 v1@1473,-64 ; v1(1660,-65) 1683.86,-88.86 EC1.97@1683.86,-150.67 ; U8:A.15@1662.34,1746.05 v1@1708.95,1746.05 ; U8:A.17@1662.34,1797.23 1714.23,1797.23 v1(1716,1799) ; v1@1776.1,1353.9 R32.2@1818.1,1353.9 ; v1(1890,-65) 1904.33,-79.33 EC1.111@1904.33,-150.67 ; v1(2020,1565) 2023.78,1568.78 C9.2@2063.1,1568.78 ; v1@2025,1125 2025,1121.5 C27.1@2065,1081.5 ; v1@2159.48,1135.52 v1(2160,1135) 2161.38,1136.38 C30.1@2161.38,1180 ; v1(2165,1505) 2165.91,1505.91 U2.2@2165.91,1546.73 ; U4.2@2173.1,1371.53 2173.1,1340.9 2187,1327 v1(2205,1327) ; D1.1@2223.1,988.74 2229.36,995 v1(2285,995)
  Bottom Layer w6: v1@1955,1055 v1@1955.5,1055.5
  Bottom Layer w10: v1(1236,1137) 1248.62,1124.38 C14.2@1248.62,1092
  Bottom Layer w12: v1(-145,420) -141.9,416.9 C44.1@-141.9,368.9 ; v1(-140,570) -136.9,573.1 C41.1@-136.9,620.9 ; v1(-63,506) -60.37,506 v1@-59.69,506.69 ; v1@-59,506 -26.9,538.1 U6.2@-26.9,546.53 ; v1@80,570 v1@85,575 ; v1(85,570) v1@85,575 ; C42.1@85,622.01 v1@85,575 ; C43.1@89,368 106,385 v1(106,422) ; v1(150,425) 150,382 C53.2@166,366 ; C54.2@163.1,620.9 163.1,571.9 v1(165,570) ; v1@186,490 199,477 262,477 273.1,465.9 U7.2@273.1,438.27 ; v1(269,136) 272.6,132.4 C46.1@321.6,132.4 ; v1(272,205) 275,205 280,210 282.6,207.4 C47.1@321.6,207.4 ; v1(385,570) 388.1,573.1 C55.2@388.1,620.9 ; C52.2@388.1,368.9 433.9,368.9 v1@441,376 ; v1(536,449) 538.1,451.1 C34.1@538.1,495.9 ; v1(550,720) 587,720 C35.1@588.1,718.9 ; v1(638,449) 638.1,449.1 C36.1@638.1,495.9 ; v1(650,720) 687,720 C37.1@688.1,718.9 ; v1@660,155 675.4,170.4 U8.2@702.23,170.4 ; v1(733,453) 734.2,453 738.1,456.9 C38.1@738.1,495.9 ; v1(750,720) 787,720 C39.1@788.1,718.9 ; v1(775,88) 776.21,88 786.6,98.4 C45.1@786.6,137.4 ; v1(827,1007) 827,1008 866.4,1047.4 C11.1@881.6,1047.4 ; v1(830,815) 840,815 842.4,817.4 R56.1@881.6,817.4 ; v1(830,895) 840,895 842.6,892.4 880.6,892.4 R55.1@881.6,892.4 ; v1(830,970) 832.6,967.4 R57.1@881.6,967.4 ; C40.1@838.1,495.9 838.1,450.9 v1(839,450) ; v1@843,1170 v1(843,1171) ; C22:A.2@895,1585 925,1585 935,1575 v1(938,1575) ; v1(935,1855) 938.62,1851.38 C20:A.2@980,1851.38 ; v1(1023,1110) 1025,1110 1036.38,1121.38 C6.1@1070,1121.38 ; C60.1@1146.5,700 C61.1@1146.5,765 1189,765 v1(1199,775) v1@1200,776 ; v1(1265,810) 1266.5,811.5 C13.1@1315,811.5 ; C17.2@1408.62,1230 1408.62,1211.38 v1@1430,1190 ; v1@1463,805 1486.38,781.62 C5.1@1486.38,775 ; v1@1465,805 v1(1465,806) ; C5.1@1486.38,765 C5.1@1486.38,775 ; C5.1@1496.38,765 C5.1@1486.38,775 ; v1(1508,1588) 1508.5,1587.5 C19.1@1508.5,1540 ; C15.2@1517.27,649.99 1517.27,617.73 v1(1525,610) ; v1(1530,480) 1530.9,480.9 C8.2@1583.1,480.9 ; v1@1607,1136 1614.62,1143.62 C16.2@1650,1143.62 ; C25:A.1@1670,1817.38 1692.62,1817.38 1711,1799 v1(1716,1799) ; C7.1@1687,459 1730,416 v1(1743,416) ; v1(1775.5,1172.5) 1775.5,1177.5 1791.62,1193.62 C4.1@1810,1193.62 ; R33.2@1843.1,1656.02 1843.1,1694.9 1845,1693 v1(1845,1690) ; C23.2@1868.62,1360 1868.62,1408.62 v1(1870,1410) ; R17.1@1886.5,1290 1930,1290 v1(1940,1300) ; v1(1955,1056) 1967.62,1068.62 C22.2@1995,1068.62 ; v1(2095,865) 2103.62,856.38 C25.2@2103.62,830 ; C29.1@2208.62,1375 2258,1375 v1@2260,1377 ; C24.2@2225,891.5 2283.5,891.5 v1(2285,890)
  Bottom Layer w15: EC1.38@612.99,-150.67 612.99,-67.01 615,-65 v1(616,-65) ; EC1.46@738.98,-150.67 740,-149.64 v1(740,-65) ; v1@840,1170 843,1170 848.5,1170 C10.1@888.5,1130 ; C26:A.1@854.96,1860.87 854.96,1825.04 876,1804 v1(953,1804) ; C24:A.2@896.22,1264.49 919.51,1264.49 933,1251 v1(936,1251) ; C12.1@1241.5,930 1241.5,976.5 v1(1245,980) ; v1(1351,1539) 1352,1539 1356,1535 R15.1@1420,1535 ; 1388.1,1108.78 1418.78,1108.78 1419,1109 1417,1111 v1(1416,1111) ; v1@1428,1317 1430,1319 C1.2@1430,1362 ; v1@1430,1190 1431,1190 v1(1433,1188) ; v1@1432,1192 v1@1434,1190 ; R34.1@1900,1645 v1(1900,1690) ; v1(2185,1220) 2195,1230 2195,1260.68 C31.2@2196.72,1262.4
  other v1: 1472,-63 662,155 1087,221 992,364 105,470 2020,1125 1605,1136 1427,1317 2259,1375 1710,1745
HSEC_5V0: C24.1 C25.1 EC1.48 EC1.84 EC1.98 EC1.112 TP1.1 U3.1 U3.3 | length 704.1
  Top Layer w12: v1@2058,789 2057.6,789.4 U3.1@2057.6,825.87 2057.6,867.6 2058.2,867 v1(2059,867) ; v1(2113,785) 2128.8,785 2137.8,794 2135.8,796 2132.4,792.6 U3.3@2132.4,825.87 2132.4,865.6 v1@2131,867
  Bottom Layer w12: EC1.48@770.47,-150.67 770.47,-79.53 v1(785,-65) ; EC1.84@1463.38,-150.67 1463.38,-84.08 1451,-71.7 1451,-33 1464,-20 v1(1464,-18) ; EC1.98@1683.86,-150.67 1683.86,-81.14 v1(1700,-65) ; EC1.112@1904.33,-150.67 1904.33,-85.67 v1(1925,-65) ; C25.1@2056.38,830 2056.38,866.38 2057.76,865 2059,866.24 v1(2059,867) ; v1(2175,829) 2175.5,828.5 C24.1@2225,828.5
  other v1: 2058,785 2132,867
HSEC_ADC-A0,B15,C15,DACA: EC1.9 R36.2 U5.1 | length 940.1
  Top Layer w6: v1(-110,478) -72,478 -64.3,470.3 U5.1@-64.3,438.27 -64.3,380.1 -60,375.8 R36.2@-66.9,368.9 ; EC1.9@172.05,-150.67 172.05,-92.41 193,-71.46 193,-27 v1@179,-13
  Mid-Layer 4 w6: v1(-110,478) -81,478 -66,463 -66,359 22,271 22,147.14 162,7.14 162,-2 175,-15 v1(180,-15)
HSEC_ADC-A1,DACB: EC1.11 R38.2 U5.3 | length 802.9
  Top Layer w6: R38.2@10,370 10.5,370.5 U5.3@10.5,438.27 ; R38.2@13.1,368.9 50,405.8 49,406.8 v1(49,417) ; EC1.11@203.54,-150.67 203.54,-83.46 216,-71 216,-40 v1@237,-19
  Mid-Layer 4 w6: v1@50,418 v1(49,417) 42,410 42,163 191.6,13.4 191.6,13 213,-8.4 213,-8.88 225.12,-21 v1@232,-21
  other v1: 235,-20
HSEC_ADC-A2,B6,PGA1_IN: EC1.15 R37.1 U6.1 | length 1010.5
  Top Layer w6: v1(265,-65) 266.53,-66.53 EC1.15@266.53,-150.67
  Mid-Layer 4 w6: v1(-110,545) -76.54,545 -45,513.46 -45,498.54 -47,496.54 -47,363 32,284 32,157.98 186.98,3 187.46,3 203,-12.54 203,-13.02 210,-20.02 210,-39.46 217.54,-47 247,-47 v1(265,-65)
  Bottom Layer w6: v1(-110,545) -108.47,546.53 U6.1@-64.3,546.53 ; U6.1@-64,548 -61.9,550.1 R37.1@-61.9,620.9
HSEC_ADC-A3: EC1.17 R41.2 U5.4 | length 946.5
  Top Layer w6: v1(10,505) 10.5,505.5 U5.4@10.5,546.53 ; U5.4@13.1,545.1 R41.2@13.1,620.9 ; EC1.17@298.03,-150.67 298.03,-71.97 v1(305,-65)
  Mid-Layer 4 w6: v1(10,505) 20,495 20,457 41,436 60,436 68,428 68,300 52,284 52,167.14 201.6,17.54 201.6,17.4 213.23,5.77 234.68,5.77 253,-12.54 253,-30.46 266.54,-44 285,-44 v1@306,-65
HSEC_ADC-A4,B8,PGA2_IN: EC1.21 R39.1 U6.3 | length 991.5
  Top Layer w6: v1(345,-18) 363,-36 363,-148.69 EC1.21@361.02,-150.67
  Mid-Layer 4 w6: v1@41,545 41,505 88,458 88,401.54 107,382.54 107,272 145,234 145,106 218,33 261,33 297,-3 ; 297,-4 331,-4 v1(345,-18)
  Bottom Layer w6: R39.1@13.1,620.9 13.1,616.1 13.1,550.1 10,547 v1@42,547
  Bottom Layer w12: R39.1@10.5,613.5 13.1,616.1 15,618 R39.1@15,622
  other v1: 43,546
HSEC_ADC-A5: EC1.23 R44.2 U5.6 | length 1200.6
  Top Layer w6: v1@-109,510 -100.84,510 U5.6@-64.3,546.53 R44.2@-64.3,616.3 ; EC1.23@392.52,-150.67 v1@392.52,-67.48
  Top Layer w12: R44.2@-67,620 -67,619 R44.2@-64.3,616.3
  Mid-Layer 4 w6: v1(-110,510) -131,489 -131,466 -123,458 -102.54,458 -92,447.46 -92,367 -70,345 -70,344 7.36,266.64 7.36,147.64 121,34 121,-69 137,-85 365,-85 v1(385,-65)
HSEC_ADC-A6,PGA5_IN: EC1.25 R43.1 U8.1 | length 723.5
  Top Layer w6: EC1.25@424.01,-150.67 424.01,-75.99 v1(435,-65)
  Mid-Layer 4 w6: v1(435,-65) 435,-61 453,-43 587.46,-43 662,31.54 662,104 683,125 683,235 702,254 v1(703,254)
  Bottom Layer w12: v1(703,254) 702.23,254.77 702.23,209.8 702.43,210 R43.1@780,210
HSEC_ADC-A8,PGA6_OF: EC1.33 R35.1 U8.3 | length 727.7
  Top Layer w6: v1(525,15) 550,-10 EC1.33@550,-150.67
  Mid-Layer 4 w6: v1(704,98) 704,192 732,220 732,283 v1(705,310)
  Bottom Layer w6: v1(525,15) 525,17 576,68 674,68 v1(704,98) ; v1@702,102 v1@703,103 ; U8.3@702.23,135 U8.3@702.23,133 704,131.23 v1(704,98) ; v1@705,99 v1(704,98) ; v1@706,310 716.6,320.6 R35.1@716.6,367.4
HSEC_ADC-A9: EC1.27 R47.2 U7.1 | length 770.8
  Top Layer w6: v1@438,22 455,5 455,-75 455.51,-75.51 EC1.27@455.51,-150.67
  Mid-Layer 4 w6: v1(356,441) 330,415 330,331.54 339,322.54 339,127 437,29 v1(437,21)
  Bottom Layer w6: U7.1@312.2,438 313.1,438.9 U7.1@313.1,438 ; R47.2@313.1,368.9 U7.1@313.1,438 ; v1@356,442 352,438 U7.1@313.1,438
HSEC_ADC-B0: EC1.12 R49.2 U7.3 | length 740
  Mid-Layer 4 w6: v1@190,424 204,410 204,110 v1@220,94 ; v1(218,98) v1@220,98
  Bottom Layer w6: v1@188,426 198,436 230,436 232.9,438.9 238.1,438.9 R49.2@238.1,368.9 ; EC1.12@203.54,-150.67 203.54,-83.46 213,-74 213,-2 236,21 236,81 219,98 v1(218,98)
  other v1: 189,424
HSEC_ADC-B1,A10,C10,PGA7_IN: EC1.14 R46.1 U8.6 | length 656.4
  Bottom Layer w6: 235,-47 235.04,-46.96 ; EC1.14@235.04,-150.67 235.04,-46.96 ; R46.1@520,207 522.8,209.8 U8.6@593.97,209.8 ; R46.1@520,210 490,180 490,84 468,62 304,62 253.5,11.5 253.5,-28.5 235.04,-46.96
  Bottom Layer w12: EC1.14@235.04,-150.67 EC1.14@237,-148.71 ; U8.6@592.4,207.4 U8.6@595,210
HSEC_ADC-B2,C6,PGA3_IN: EC1.18 R40.1 U6.4 | length 892
  Mid-Layer 4 w6: v1(60,455) 78,437 78,284 69,275 ; 69.27,274.73 67,272.46 67,167 217,17 259.4,17 301.4,-25 304.4,-22 v1(305,-22)
  Bottom Layer w6: R40.1@10,370 10.5,370.5 10.5,374.5 U6.4@10.5,438.27 43.27,438.27 v1(60,455) v1@61,456 ; EC1.18@298.03,-150.67 298.03,-83.49 287,-72.46 287,-43 305,-25 v1(305,-22)
  Bottom Layer w12: R40.1@10.5,374.5 R40.1@15,370
HSEC_ADC-B3,VDAC: EC1.20 R53.2 U7.4 | length 868.7
  Mid-Layer 4 w6: v1(198,543) 202,543 220,525 220,151.14 345,26.14 v1(345,15)
  Bottom Layer w6: v1@208,543 230,543 238.1,551.1 R53.2@238.1,620.9 ; EC1.20@329.53,-150.67 327,-148.14 327,-3 v1(345,15)
HSEC_ADC-B4,C8,C3,PGA4_IN: EC1.24 R42.1 U6.6 | length 1253.8
  Mid-Layer 3 w6: v1@377,-23 v1(377,-20)
  Mid-Layer 4 w6: v1(-110,440) -110,316 -45,251 -45,210.36 -2.64,168 -2.64,139.64 111,26 111,-82 130,-101 374.46,-101 403,-72.46 403,-47 v1@377,-21
  Bottom Layer w6: U6.6@-69.27,438.27 -66,435 -66.9,434.1 R42.1@-66.9,368.9 ; v1(377,-20) 403,-46 403,-72.46 392.52,-82.94 EC1.24@392.52,-150.67
  Bottom Layer w12: v1(-110,440) -108.27,438.27 -69.27,438.27 U6.6@-64.3,438.27
HSEC_ADC-C0: EC1.26 R60.2 U7.6 | length 893.5
  Mid-Layer 4 w6: v1@348,566 322,540 322,429 312,419 312,335.4 329,318.4 329,116 402,43 v1(402,21)
  Bottom Layer w6: U7.6@310.5,546.53 U7.6@312.48,548.52 ; R60.2@313.1,611.1 313.1,552.1 311,550 U7.6@312.48,548.52 ; v1@348,564 338,554 317.97,554 U7.6@312.48,548.52 ; v1(402,21) 402,11 415,-2 415,-80 424.01,-89.01 EC1.26@424.01,-150.67
  Bottom Layer w12: R60.2@313.1,611.1 315,613 R60.2@315,617
  other v1: 348,565
HSEC_ADC-C1: EC1.28 R61.2 U9.1 | length 710.6
  Top Layer w6: U9.1@235,439.8 238.1,442.9 R61.2@238.1,368.9 270,337 v1(276,337)
  Top Layer w12: R61.2@235,370 R61.2@235.7,370.7
  Mid-Layer 4 w6: v1@275.5,336.5 309,303 309,105 367,47 367,16.4 392.2,-8.8 421.8,-8.8 v1@434,-21
  Bottom Layer w6: v1@434,-20 455.51,-41.51 EC1.28@455.51,-150.67
  other v1: 435,-20
HSEC_ADC-C2: EC1.30 R62.2 U9.3 | length 673.6
  Top Layer w6: R62.2@310.5,371.5 U9.3@310.5,438.27 ; R62.2@313.1,368.9 316.11,368.89 v1@347,338 ; v1(349,338) v1@349,340
  Mid-Layer 4 w6: v1@351,334 351,144 480,15 v1(479,15)
  Bottom Layer w6: v1(479,15) 479,-5 506,-32 506,-73 487.01,-91.99 EC1.30@487.01,-150.67
HSEC_ADC-C4: EC1.34 R63.2 U9.4 | length 915.8
  Top Layer w6: U9.4@310.5,543.5 U9.4@310.5,546.53 U9.4@313.1,546.53 ; R63.2@313.1,620.9 U9.4@313.1,546.53 ; v1@350,531 334.47,546.53 U9.4@313.1,546.53
  Mid-Layer 4 w6: v1(349,531) 349,485 374,460 374,318 424,268 424,172 497,99 ; 496.5,98.5 v1(580,15)
  Bottom Layer w6: EC1.34@550,-150.67 551,-149.67 551,-9 575,15 v1(580,15)
HSEC_ADC-C5,PGA6_IN: EC1.31 R45.1 U8.4 | length 382.2
  Top Layer w6: EC1.31@518.5,-150.67 518.5,-71.5 v1(525,-65)
  Mid-Layer 3 w6: v1@524,-64 v1(525,-65)
  Bottom Layer w6: R45.1@519.6,132.4 519.6,67.6 501,49 501,5 525,-19 v1@525,-64 ; R45.1@521,134 522,135 U8.4@593.97,135 ; v1(525,-65) v1@530,-65
HSEC_ADC-C14: EC1.36 R64.2 U9.6 | length 1025.8
  Top Layer w6: R64.2@238.1,620.9 238.1,548.1 235,545 235,511 v1@241,505
  Mid-Layer 4 w6: v1(245,502) 245,461 299,407 299,334 313,320 ; 313.13,320.13 319,314.26 319,111.86 380,50.86 380,17.54 395.77,1.77 454.23,1.77 459,-3 561,-3 v1(577,-19) ; v1@574.5,-21.5 v1@579,-26
  Bottom Layer w6: v1(577,-19) 598,-40 598,-72.46 581.49,-88.96 EC1.36@581.49,-150.67
HSEC_ADCVREFHI-EXT: EC1.45 S8.1 S8.2 | length 481.1
  Top Layer w6: S8.1@518.1,227.4 518.1,178.1 518.9,178.1 518.9,138.1 592,65 615,65 721,-41 ; 722,-43 722,-72.46 738.98,-89.43 EC1.45@738.98,-150.67
HSEC_GPIO-12: EC1.57 R3.1 | length 1640.8
  Top Layer w6: EC1.57@1059.39,-124 1059.39,-96 1071.5,-83.89 1071.5,15.5 1072,16 ; 1074,18 1072,16 ; v1(1910,465) 1848,403 1831.72,403 1818.72,390 1318.75,390 1255,326.25 1255,160 1165,70 1125.86,70 1072,16.14 1072,16
  Bottom Layer w6: v1(1910,465) 1925,480 1925,695 1965,735 R3.1@2033.5,735 R3.1@2043.5,735
HSEC_GPIO-13: EC1.59 R4.1 | length 1569.1
  Top Layer w6: EC1.59@1085.43,-150.67 1085.43,-75 1085,-75 1085,15 1125,55 1164.14,55 1265,155.86 1265,322.11 1290.87,347.98 1292.12,347.98 1324.14,380 1822.86,380 1835.86,393 1878,393 v1(1910,425)
  Bottom Layer w6: v1(1910,425) 1970,485 1970,625 2000,655 R4.1@2033.5,655 R4.1@2043.5,655
HSEC_GPIO-22: EC1.72 R19.2 | length 2313.5
  Mid-Layer 8 w6: v1(1171,1435) 1246,1435 1278,1403 1278,1309 1323,1264 1464,1264 1492.5,1235.5 ; v1(1289,-21) 1292.54,-21 1290.77,-22.77 1311,-43 1407,-43 1454,4 1481,4 1502,25 1502,239.98 1736,473.98 1736,681 1711,706 1711,761 1557,915 1557,1093.14 1498,1152.14 1498,1231 1493,1236
  Bottom Layer w6: EC1.72@1274.41,-150.67 1274.41,-84.41 1270,-80 1270,-45 1289,-26 v1(1289,-21)
  Bottom Layer w12: v1(1171,1435) R19.2@1223.5,1435
HSEC_GPIO-23: EC1.64 R18.2 | length 1987.2
  Top Layer w6: R18.2@1659.6,1372.4 1707.6,1372.4 v1(1710,1370)
  Mid-Layer 4 w6: v1@1209,13 1250,54 1310,54 1736,480 1736,644.46 1715.46,665 1715,665 1658,722 1658,785 1569,874 1569,1013 1656.64,1100.64 1656.64,1139.64 1692,1175 1692,1322 1710,1340 v1(1710,1370)
  Bottom Layer w6: EC1.64@1148.42,-150.67 1152,-147.09 1152,-57.54 1162.54,-47 1173.46,-47 1190,-30.46 1190,-5 v1(1210,15)
HSEC_PGA1_GND: EC1.13 R48.1 | length 1482.7
  Top Layer w6: EC1.13@235.04,-150.67 235.04,-54.96 253,-37 253,-11 264,0 289,0 v1@305,16 ; v1(790,895) 795,895 819,919 855,919 R48.1@881.6,892.4
  Top Layer w12: EC1.13@235,-150.63 EC1.13@235.04,-150.67
  Mid-Layer 8 w6: v1(305,15) 317,27 317,277.46 427.54,388 427.54,388.54 463,424 463,512.46 459,516.46 459,693 661,895 v1(790,895)
HSEC_PGA3_GND: EC1.16 R50.1 | length 1462
  Top Layer w6: v1(790,814) 794,814 824,844 855,844 R50.1@881.6,817.4
  Mid-Layer 8 w6: v1@270,-25 291,-4 316,-4 327,7 327,22.46 328,23.46 328,255 425,352 459,352 476,369 476,695.86 592.14,812 v1@791,812
  Bottom Layer w6: EC1.16@266.53,-150.67 266.53,-91.99 247,-72.46 247,-51 v1@272,-26
  other v1: 272,-22
HSEC_PGA5_GND: EC1.29 R51.1 | length 1506.8
  Top Layer w6: v1(485,-65) 487.01,-67.01 EC1.29@487.01,-150.67 ; v1(795,970) 820,945 855.2,945 877.6,967.4 R51.1@881.6,967.4
  Mid-Layer 8 w6: v1(485,-65) 497,-53 497,22.46 490,29.46 490,694 566,770 792,770 810,788 810,955 v1(795,970)
HSEC_PGA7_GND: EC1.10 R54.1 | length 1695.5
  Top Layer w6: v1(1430,425) 1433.1,428.1 R54.1@1433.1,475.9
  Mid-Layer 3 w6: v1@215,70 223,62 471,62 604,195 740,195 980,435 1076,435 1114,473 1382,473 v1(1430,425)
  Bottom Layer w6: EC1.10@172.05,-150.67 172.05,-92.41 203,-61.46 203,53 v1@215,65 ; v1@214,66 v1(215,67)
HSEC_PGA246_GND: EC1.19 EC1.22 EC1.35 R52.1 | length 1538.7
  Top Layer w6: EC1.19@329.53,-150.67 329.53,-80 344.53,-65 v1(345,-65) ; v1(580,-65) 581.49,-66.49 EC1.35@581.49,-150.67 ; v1(1261,412) 1263.1,414.1 R52.1@1263.1,475.9
  Mid-Layer 3 w6: v1@345,-64 v1(345,-65) 363,-47 563,-47 v1@579,-63 ; v1@345,-63 v1@345.5,-63.5 ; v1@581,-65 v1@579,-63 ; 756,117 793,154 793,228 980,415 1083,415 1114,446 1229,446 v1@1261,414 ; 757.5,115.5 v1@579,-63
  Bottom Layer w6: v1(345,-65) 361.02,-81.02 EC1.22@361.02,-150.67
HSEC_PIN58: EC1.58 S3.3 S3.4 | length 988.1
  Top Layer w6: v1@1119,-24 v1@1122.5,-20.5 ; v1(1120,-18) 1135,-3 1177.46,-3 1190,9.54 1190,44 1271,125 1530,125 1590,185 S3.4@1600,185 ; S3.4@1602.17,183.5 1658.5,183.5 1676,201 1676,306 1691.3,321.3 S3.3@1747.83,321.3
  Bottom Layer w6: EC1.58@1059.39,-122 1059.39,-69.11 1092,-36.5 1101.5,-36.5 v1(1120,-18)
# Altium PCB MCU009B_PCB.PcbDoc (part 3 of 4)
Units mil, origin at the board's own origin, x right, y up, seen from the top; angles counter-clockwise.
Board outline 2657.23 x 2215.46 mil, 10 copper layers (Top Layer, Internal-Plane 2, Mid-Layer 3, Mid-Layer 4, Internal-Plane 5, Internal-Plane 6, Mid-Layer 7, Mid-Layer 8, Internal-Plane 9, Bottom Layer), stack 60.8 mil thick; 232 components, 196 nets, 851 pads, 493 vias.

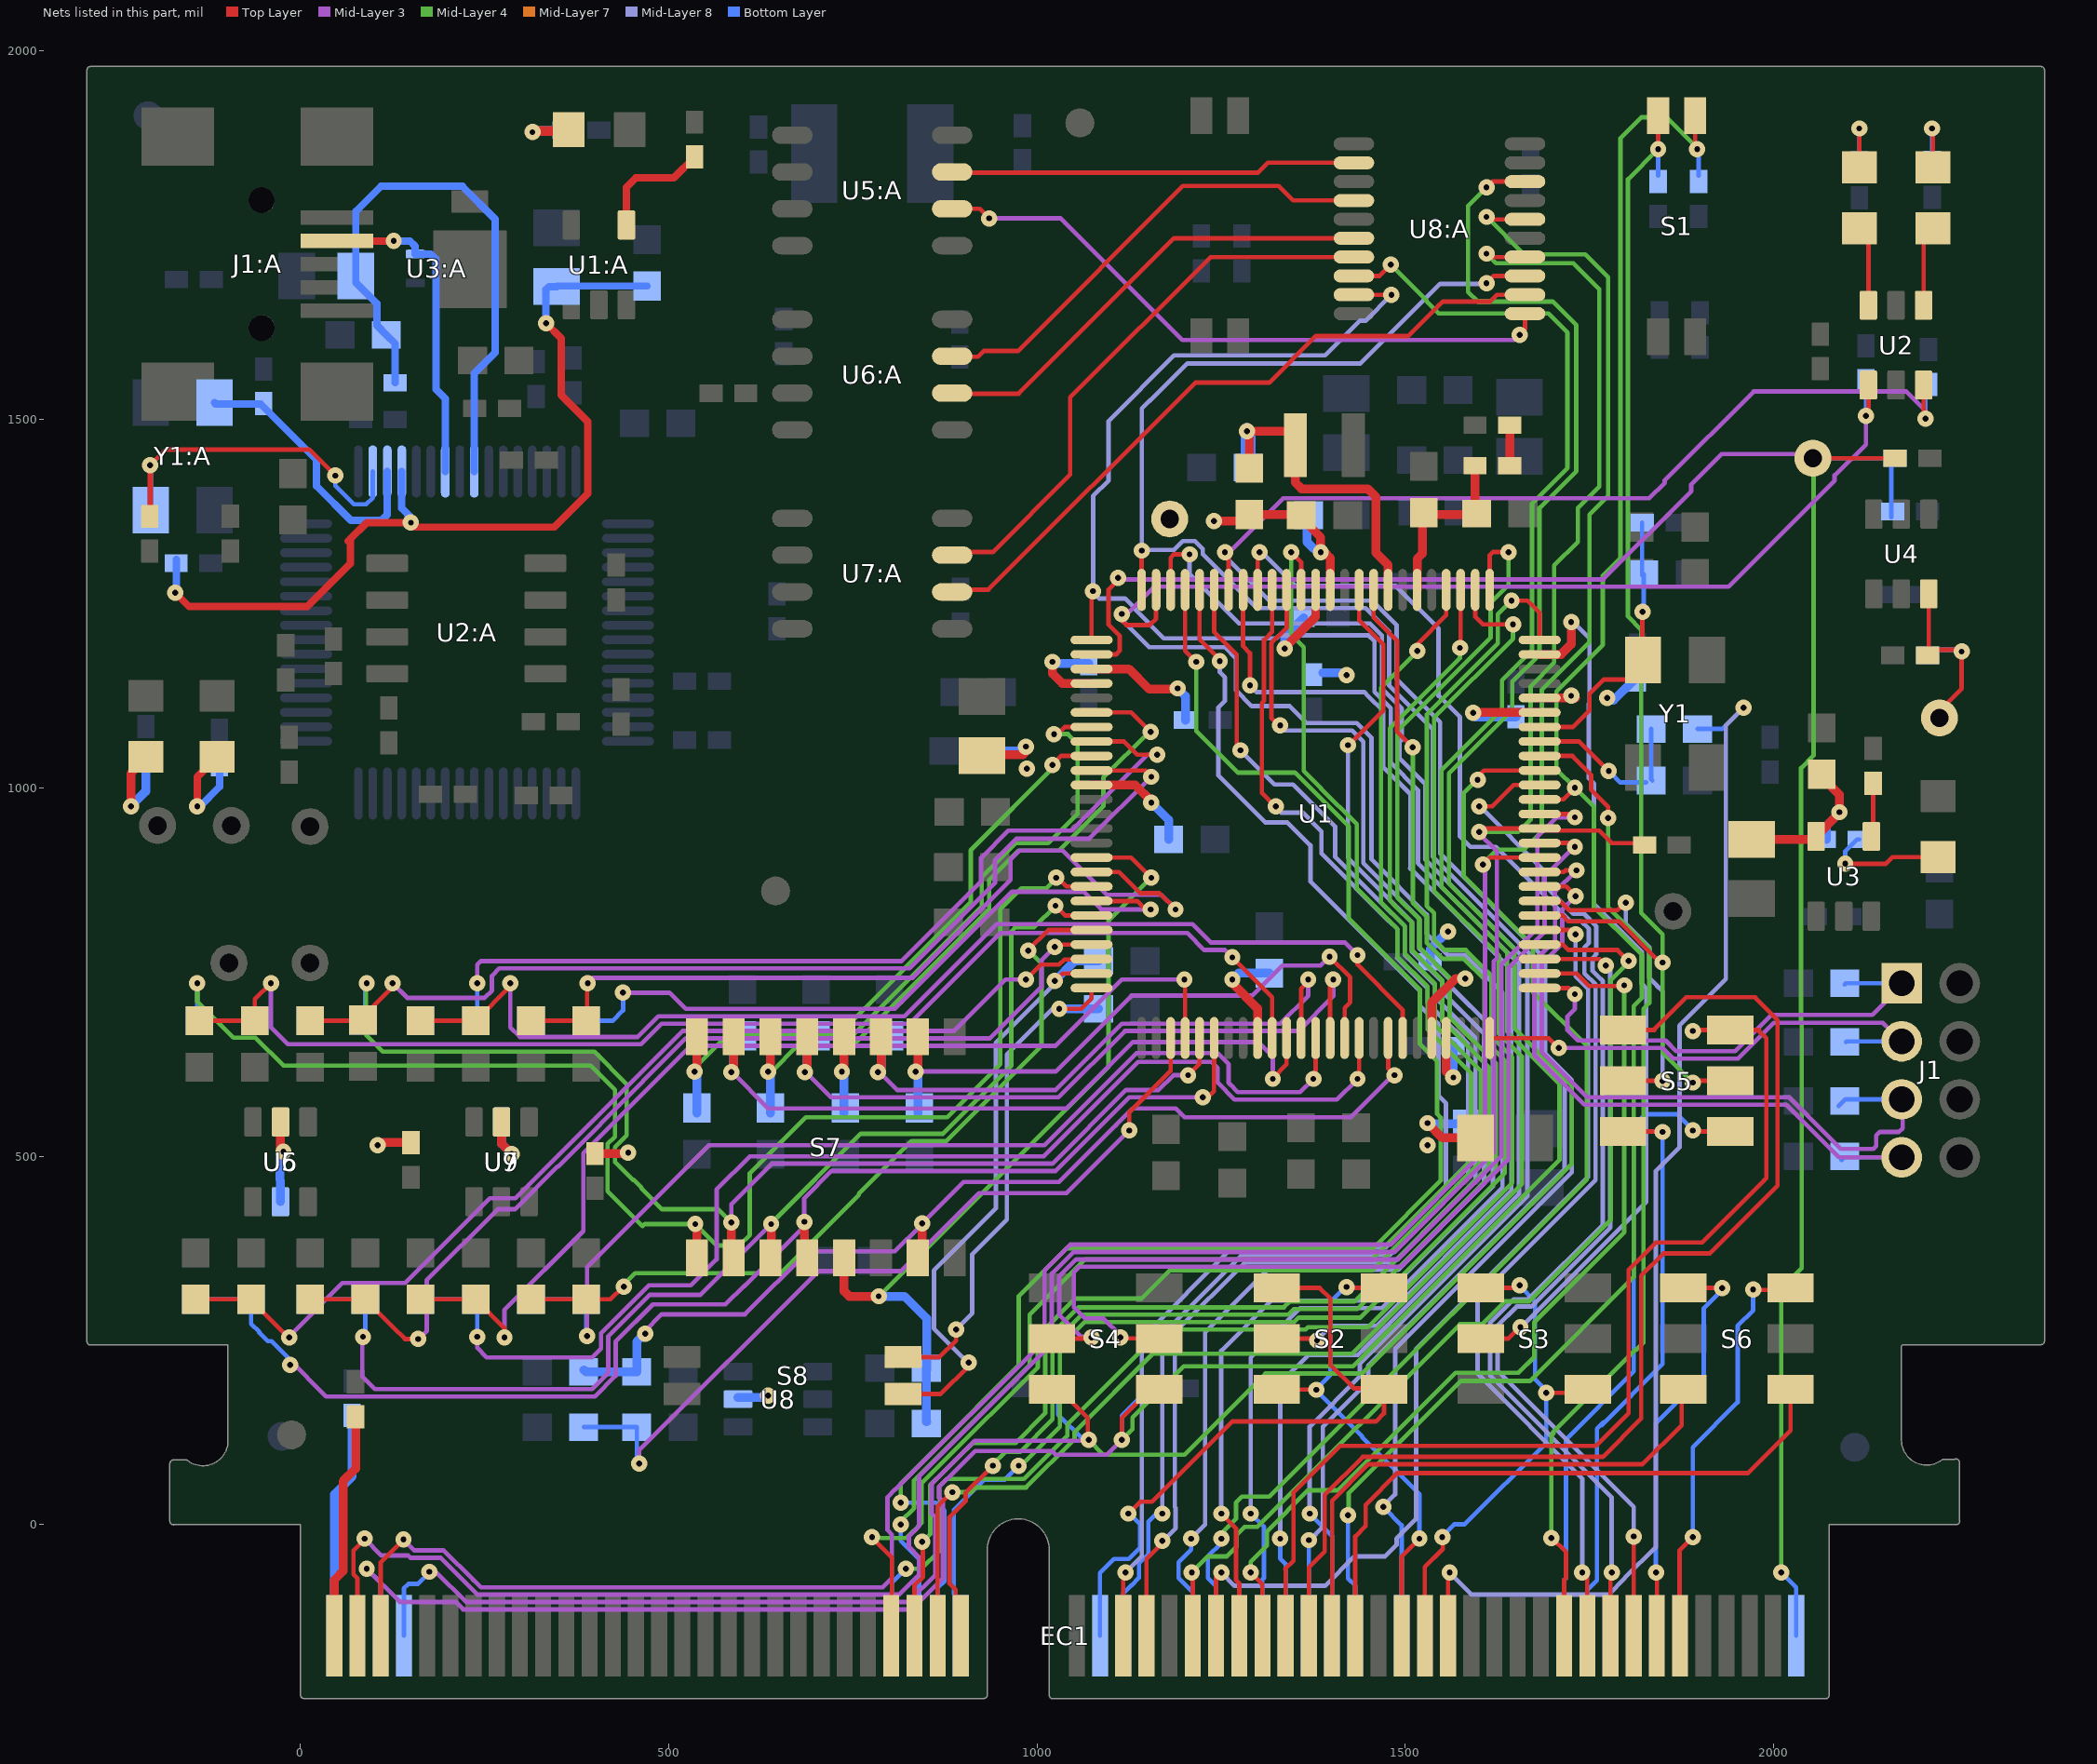
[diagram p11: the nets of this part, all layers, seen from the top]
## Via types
v1: diameter 22, hole 8, Top Layer to Bottom Layer, 414 vias
v2: diameter 22, hole 8, Top Layer to Bottom Layer, tented both sides, 79 vias

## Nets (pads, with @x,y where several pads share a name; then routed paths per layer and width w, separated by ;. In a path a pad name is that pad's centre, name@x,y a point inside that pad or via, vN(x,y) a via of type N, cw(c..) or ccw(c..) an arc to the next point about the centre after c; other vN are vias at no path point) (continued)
HSEC_PIN60: EC1.60 S2.1 S2.6 | length 895
  Top Layer w6: v1@1125,16 1140,31 1156,31 1265,140 1460,140 1470.93,150.93 S2.6@1470.93,183.5 ; S2.1@1325.27,321.3 1383.7,321.3 1398,307 1398,217 1430,185 S2.6@1465,185 ; S2.6@1470.93,185 S2.6@1475,185
  Bottom Layer w6: EC1.60@1085.43,-150.67 1085.43,-65.57 1104.5,-46.5 1124.5,-46.5 1140,-31 1140,0 v1@1124,16
  other v1: 1124,15
HSEC_PIN75: EC1.75 S5.3 | length 1426.1
  Top Layer w6: 1336.9,-60.1 1348,-49 1348,44 1411,107 1759,107 1803,151 1803,346 1840,383 1903,383 1987,467 1987,467.46 1990,470.46 1990,660 1980,670 ; EC1.75@1337.4,-150.67 1337.4,-60.6 ; v1(1890,670) 1891.3,671.3 S5.3@1940.93,671.3 1980,671.3
HSEC_PIN77: EC1.77 S5.6 | length 1568.7
  Top Layer w6: EC1.77@1368.9,-150.67 1368.9,-58.1 1390.39,-36.61 1390.39,40.39 1442,92 1768,92 1820,144 1820,338 1850,368 1913,368 2005,460 2005,685 1975,715 ; S5.6@1795.27,671.3 1838,671.3 1838,673 1881,716 1975,716
HSEC_PIN79: EC1.79 S6.3 | length 750.2
  Top Layer w6: EC1.79@1400.39,-150.67 1400.39,32.39 1450,82 1822,82 1875,135 S6.3@1875,185
HSEC_PIN81: EC1.81 S6.6 | length 860.8
  Top Layer w6: EC1.81@1431.89,-150.67 1431.89,-16 ; 1432,-16 1446,-2 1446,27 1489,70 1965,70 2022.83,127.83 S6.6@2022.83,182.83 ; S6.6@2022.83,183.5 S6.6@2022.83,182.83 ; S6.6@2025,185 S6.6@2022.83,182.83
HSEC_PIN85: EC1.85 S2.3 S2.4 | length 677.6
  Top Layer w6: S2.3@1325.27,183.5 1378.5,183.5 1379,184 v1(1379,183) ; v1(1420,322.6) 1418.7,321.3 S2.4@1470.93,321.3 ; EC1.85@1494.88,-150.67 1494.88,-43.12 v1(1519,-19) v1@1520,-18
  Mid-Layer 7 w6: v1(1420,322.6) v1@1420,330
  Bottom Layer w6: v1@1377,184 1441.5,119.5 ; v1(1379,183) 1379,184 1398,203 1398,302 v1@1419,323 ; 1441,119 1519,41 v1(1519,-19)
HSEC_PIN87: EC1.87 S3.1 S3.6 | length 680.1
  Top Layer w6: EC1.87@1526.38,-150.67 1526.38,-57.62 1551,-33 v1@1551,-19 ; v1@1550,-19 v1(1550,-17) ; S3.6@1602.17,321.3 1651.3,321.3 v1(1655,325) ; v1(1691,179) 1742,179 S3.1@1747,184
  Bottom Layer w6: v1@1549,-17 1566.5,0.5 1580.5,0.5 1691,111 v1(1691,179) ; v1(1655,325) 1655,324 1676,303 1676,197 v1@1693,180
HSEC_PIN100: EC1.100 S5.1 | length 878.3
  Top Layer w6: v1(1890,535) 1891.5,533.5 S5.1@1940.93,533.5
  Bottom Layer w6: EC1.100@1715.35,-150.67 1715.35,-75.1 1718,-72.46 1718,116 1810,208 1810,542 1825,557 1869,557 v1@1890,536
HSEC_PIN102: EC1.102 S5.4 | length 785.2
  Top Layer w6: S5.4@1795.27,533.5 1848.5,533.5 v1(1849,533)
  Bottom Layer w6: EC1.102@1746.85,-150.67 1746.85,-88.61 1760,-75.46 1760,130 1769,139 ; 1766,135 1849,218 v1(1849,533)
HSEC_PIN107: EC1.107 S6.1 | length 561.9
  Top Layer w6: v1(1840,-65) 1841.34,-66.34 EC1.107@1841.34,-150.67 ; S6.1@1877.17,321.3 1929.7,321.3 v1(1930,321)
  Bottom Layer w6: v1(1840,-65) 1840,138 1905,203 1905,294 v1@1931,320
HSEC_PIN109: EC1.109 S6.4 | length 561.6
  Top Layer w6: EC1.109@1872.83,-150.67 1872,-149.84 1872,-35 v1(1890,-17) ; v1(1972,319) 1971.5,318.5 S6.4@2020.93,318.5
  Bottom Layer w6: v1(1890,-17) 1890,105 1951,166 1951,270 1972,291 v1(1972,319)
HSEC_TDI: EC1.8 R8.1 S4.3 U8:A.18 | length 3853.8
  Top Layer w6: S4.3@1020.27,183.5 1030.5,183.5 1069,145 v1@1069,119 ; v1(1610,1815) 1617.82,1822.82 U8:A.18@1662.34,1822.82
  Mid-Layer 3 w6: v1(175,-64) 184,-64 225,-105 825,-105 862,-68 862,10 857,15 857,55.6 915.4,114 1069,114 v1(1070,115)
  Mid-Layer 4 w6: v1(1070,115) 1090,95 1200,95 1310,205 1441,205 1726,490 1726,595.57 1648,673.57 1648,780.86 1559,869.86 1559,1019.86 1645,1105.86 1645,1144 1682,1181 1682,1380 1732,1430 1732,1628 1700,1660 1598,1660 1585,1673 1585,1790 v1(1610,1815)
  Bottom Layer w6: EC1.8@140.55,-150.67 140.55,-86.45 146.5,-80.5 159.5,-80.5 v1@176,-64 ; R8.1@1028.62,185 1028.62,149.38 1063,115 v1(1070,115)
HSEC_TDO: EC1.6 R9.1 S4.6 U8:A.8 | length 3882.1
  Top Layer w6: v1(1115,115) 1115,145 1153.5,183.5 S4.6@1165.93,183.5 ; U8:A.8@1430.05,1694.87 1464.87,1694.87 v1(1480,1710)
  Mid-Layer 3 w6: v1@85,-60 v1(90,-60) 135,-105 210.86,-105 220.86,-115 830,-115 872,-73 872,31.54 867,36.54 867,51.46 877.54,62 878.14,62 916.14,100 1020,100 1025,95 1095,95 v1(1115,115) ; v1@1113,117 v1@1117,121
  Mid-Layer 4 w6: v1(1115,115) 1129.5,129.5 1129.5,145.5 1199,215 1429,215 1709,495 1709,598.43 1638,669.43 1638,776.72 1549,865.72 1549,1024 1631,1106 1631,1146 1672,1187 1672,1386 1720,1434 1720,1618 1694,1644 1545,1644 1528,1661 ; v1(1480,1710) 1528.5,1661.5
  Bottom Layer w6: v1(90,-60) 109.05,-79.05 EC1.6@109.05,-150.67 ; v1(1115,115) 1115,148 1152,185 1154,185 1155,186 R9.1@1157,184 ; R9.1@1156.38,188.78 R9.1@1158.1,188.78
MCU_1V2: C1.1 C2.1 C3.2 C4.2 C5.2 C6.2 R22.1 TP3.1 U1.4 U1.46 U1.71 U1.87 | length 699.9
  Top Layer w12: v1(1021,1171) 1021,1155 1034.27,1141.73 U1.4@1073.97,1141.73 ; v1(1240,1362) 1279.2,1362 R22.1@1286.1,1368.9 ; R22.1@1285,1370 R22.1@1286.1,1368.9 ; U1.87@1397.79,1268.7 1397.79,1312.21 1390,1320 v1(1385,1320) 1385,1340 1354.1,1370.9 R22.1@1288.1,1370.9 R22.1@1286.1,1368.9 ; U1.46@1535.58,660.43 1535.58,708.58 1568,741 v1(1581,741) ; U1.71@1682.23,1122.04 1731.04,1122.04 1728.08,1125 v1(1725,1125) ; v1@1773,1119 v1@1776,1122
  Bottom Layer w12: v1@1020,1172 v1(1021,1171) 1023.38,1168.62 C6.2@1070,1168.62 ; C1.1@1366.6,1357.4 1366.6,1333.4 1375,1325 ; 1388.1,1156.02 1417.02,1156.02 v1(1420,1153) ; C5.2@1533.62,765 1533.62,781.62 1558,806 v1(1558,805) ; v1@1773,1119 v1@1776,1122 ; v1@1782.62,1119 C4.2@1810,1146.38
  other v1: 1774,1122
MCU_3V3: C8.1 C14.1 C15.1 C16.1 C17.1 L1.2 U1.3 U1.47 U1.70 U1.88 | length 708
  Top Layer w12: U1.3@1073.97,1161.41 1124.59,1161.41 1152,1134 1190,1134 v1(1191,1135) ; v1@1336,1190 1378.1,1232.1 U1.88@1378.1,1268.7 ; v1@1529,546 v1(1530,545) 1550,525 L1.2@1595,525 ; U1.47@1555.27,660.43 1555.27,614.73 1563,607 v1(1565,607) ; v1@1599.64,1102.36 U1.70@1682.23,1102.36
  Bottom Layer w12: v1@1186.38,1135 v1(1191,1135) ; v1@1190,1136 v1(1191,1135) ; C14.1@1201.38,1092 1201.38,1124.62 v1(1191,1135) ; v1(1336,1189) 1336,1205 C17.1@1362,1231 ; v1@1528,545 1529.1,543.9 C8.1@1583.1,543.9 ; C15.1@1564.52,649.99 1564.52,607.48 v1(1565,607) ; v1@1590,1102 1595.62,1096.38 C16.1@1650,1096.38
  other v1: 1530,515 1592,1102
MCU_A_3V3: C11.2 C12.2 C13.2 C32.1 C33.1 L2.2 U1.11 U1.34 U5.5 U6.5 U7.5 U8.5 U9.5 | length 761.8
  Top Layer w12: U5.5@-26.9,546.53 -26.9,511.1 -23,507.2 v1(-23,506) ; v1@106,515 109.62,518.62 C32.1@150,518.62 ; U9.5@273.1,546.53 273.1,516.9 v1(287,503) ; C33.1@400,503.62 443.62,503.62 v1(445,505) ; L2.2@925,1045 981,1045 v1@986,1050 ; U1.11@1073.97,1003.93 1133.07,1003.93 v1@1155,982 ; v1(1265,740) 1265,735 1299.36,700.64 U1.34@1299.36,660.43
  Bottom Layer w12: U6.5@-26.9,438.27 -26.9,467.2 -28,468.3 -28,506 v1@-25,509 ; U7.5@273.1,546.53 273.1,516.9 v1(287,503) ; U8.5@593.97,172.4 633.4,172.4 v1@636,175 ; C11.2@936.5,1050 985,1050 v1@985,1055 ; v1(1155,980) 1178.5,956.5 C12.2@1178.5,930 ; v1@1155,981 v1@1155.5,980.5 ; v1(1265,740) 1273.5,748.5 C13.2@1315,748.5
  other v1: 635,175 105,515 986,1026 985,1056
MCU_ADC-A0: C48.1 R36.1 U1.23 | length 1452
  Top Layer w6: C48.1@-141.9,305.9 R36.1@-66.9,305.9 -66.9,304.9 v1@-17,255 ; v1(985,740) 1005,760 1030,760 1037,767 1073.25,767 U1.23@1073.97,767.71
  Mid-Layer 3 w6: v1@-16,255 57,328 142,328 257,443 291.86,443 518.86,670 887,670 957,740 v1(985,740) ; v1@-15.5,253.5 v1@-14,252 ; v1(-15,254) v1@-15,255
MCU_ADC-A1: C49.1 R38.1 U1.22 | length 1362.3
  Top Layer w6: R38.1@13.1,305.9 C49.1@87.9,305.9 ; C49.1@88.1,305.9 126,268 142,252 v1(160,252) ; v1@1027.4,787.4 U1.22@1073.97,787.4
  Mid-Layer 3 w6: v1@161,252 171.5,262.5 171.5,331.5 268,428 291,428 349,486 349.7,486 465,601.3 465,602 523,660 936,660 1006,730 1006,766 v1(1024,784) v1@1025,785
MCU_ADC-A3: C50.1 R41.1 U1.10 | length 1428.1
  Top Layer w6: R41.1@13.1,683.9 89.9,683.89 C50.1@88.1,683.9 ; C50.1@85,685 85,690 v1@130,735 ; U1.10@1073.97,1023.62 1147.38,1023.62 v1@1158,1013
  Mid-Layer 3 w6: v1(125,735) 145,715 250,715 260,725 260,745 270,755 827,755 943,871 943,902 972,931 1071,931 v1(1155,1015)
MCU_ADC-A5: C51.1 R44.1 U1.35 | length 1716.7
  Top Layer w6: C51.1@-136.9,683.9 R44.1@-63.1,683.9 ; R44.1@-61.9,683.9 -61.9,713.1 v1(-40,735) ; v1(1265,770) 1319.04,715.96 U1.35@1319.04,660.43
  Mid-Layer 3 w6: v1(-40,735) -40,675 -17,652 462.14,652 490.14,680 827,680 950,803 1204,803 1227,780 1255,780 v1(1265,770)
MCU_ADC-A9: C52.1 R47.1 U1.38 | length 1432.3
  Top Layer w6: v1(1375,605) 1378.1,608.1 U1.38@1378.1,660.43
  Mid-Layer 3 w6: v1(389,256) 389,349.46 554.54,515 1010,515 1135,640 1245,640 1260,625 1260,600 1262,598 1262,597.54 ; 1259.77,599.77 1262,597.54 ; v1(1375,605) 1357,587 1272.54,587 1262,597.54
  Bottom Layer w6: R47.1@313.1,305.9 C52.1@391.1,305.9 ; C52.1@388.1,305.9 388.1,256.9 v1(389,256)
MCU_ADC-B0: C53.1 R49.1 U1.41 | length 1669.5
  Top Layer w6: 1437.16,617.16 U1.41@1437.16,660.43
  Mid-Layer 3 w6: v1@240,256 v1(240,255) 240,240 253,227 396,227 408,239 408,260 473,325 530,325 565,360 565,455 610,500 1009.14,500 1137.14,628 1237,628 1245,620 1245,600 1268,577 1407,577 v1(1435,605)
  Bottom Layer w6: C53.1@163.1,305.9 R49.1@238.1,305.9 240,304 v1(240,255) 240,254 v1@239,253
  Bottom Layer w12: R49.1@238.1,305.9 239.1,305.9 R49.1@240,305
MCU_ADC-B3: C54.1 R53.1 U1.8 | length 1308.1
  Top Layer w6: U1.8@1073.97,1062.99 1117.99,1062.99 1135.97,1045 v1(1163,1045)
  Mid-Layer 3 w6: v1(240,735) 240,760 245,765 816,765 924,873 924,905 961,942 1047,942 1150,1045 v1(1163,1045)
  Bottom Layer w6: C54.1@163.1,683.9 237.9,683.9 240,686 v1(240,735)
MCU_ADC-C0: C55.1 R60.1 U1.19 | length 1040.5
  Top Layer w6: U1.19@1073.97,846.45 1135.55,846.45 v1@1149,833
  Mid-Layer 3 w6: v1(438,722) v1@439,722 ; v1@438,723 v1@439,722 ; v1(1154,835) 1087,835 1063,859 966,859 807,700 523,700 501,722 v1@439,722
  Bottom Layer w6: R60.1@313.1,683.9 C55.1@390.9,683.9 ; C55.1@388.1,683.9 C55.1@390.89,683.9 ; v1(438,722) 438,698 423.9,683.9 C55.1@390.89,683.9
MCU_ADC-C1: C56.1 R61.1 U1.29 | length 1432.9
  Top Layer w6: C56.1@163.1,305.9 R61.1@237.9,305.9 ; R61.1@238.1,305.9 277,267 v1(277,254) v1@277,252 ; v1(1200,740) 1200.93,739.07 U1.29@1200.93,660.43
  Mid-Layer 3 w6: v1(277,254) 277,291.46 384,398.46 384,504 530,650 1025,650 1115,740 v1(1200,740)
MCU_ADC-C2: C57.1 R62.1 U1.21 | length 1073.7
  Top Layer w6: R62.1@313.1,305.9 C57.1@390.9,305.9 ; C57.1@388.1,305.9 420.9,305.9 v1@437,322 ; v1@987.5,779.5 1015.08,807.08 U1.21@1073.97,807.08
  Mid-Layer 4 w6: v1@437,324 454.27,341.27 651.73,341.27 758,447.54 758,449 829.5,520.5 876.64,520.5 1006,649.86 1006,762 v1@988,780
  other v1: 439,323 988,779
MCU_ADC-C4: C58.1 R63.1 U1.17 | length 1187.2
  Top Layer w6: R63.1@313.1,683.9 389.1,683.9 389.1,734.1 v1(390,735) ; U1.17@1073.97,885.82 1111.18,885.82 1140,857 1166,857 v1(1188,835)
  Mid-Layer 3 w6: v1@388,735 395,742 831,742 964,875 964,903 976,915 1035,915 1095,855 1169,855 1188,836 v1(1188,835)
MCU_ADC-C14: C59.1 R64.1 U1.44 | length 1585.8
  Top Layer w6: C59.1@163.1,683.9 R64.1@237.9,683.9 ; R64.1@238.1,683.9 285,730.8 v1(285,735) v1@285,740 ; v1(1435,773) 1435,760 1496.21,698.79 U1.44@1496.21,660.43
  Mid-Layer 3 w6: v1(285,735) 285,675 298,662 458,662 486,690 820,690 945,815 1211,815 1236,790 1418,790 v1(1435,773) v1@1436,772
MCU_ADC-PGA1: C41.2 R37.2 S7.1 U1.18 | length 2040.2
  Top Layer w6: v1(1026,878) 1028,878 1039.86,866.14 U1.18@1073.97,866.14
  Top Layer w12: v1(536,408) 538.1,405.9 S7.1@538.1,362.4
  Mid-Layer 4 w6: v1@-140,740 v1(-140,735) -140,710 -91,661 -61,661 -23,623 394,623 427,590 427,526.6 417,516.6 417,452.54 464.54,405 467.54,408 v1(536,408) 565,379 596,379 610,393 610,477 686,553 878,553 950,625 950,835 978.5,863.5 1012.5,863.5 1026,877 v1(1026,878)
  Bottom Layer w6: v1(-140,735) -140,686.99 C41.2@-136.9,683.9 -62.1,683.9 R37.2@-61,685
  Bottom Layer w12: R37.2@-61.9,683.9 -61.1,683.9 R37.2@-60,685
MCU_ADC-PGA1OF: C34.2 S7.16 U1.9 | length 877.1
  Top Layer w6: v1(1021,1031) 1021,1032 1032.3,1043.3 U1.9@1073.97,1043.3
  Top Layer w12: v1(535,615) 538.1,618.1 S7.16@538.1,662.4
  Mid-Layer 4 w6: v1@530,615 580,665 730,665 910,845 910,915.46 1025.54,1031 v1(1021,1031)
  Bottom Layer w12: C34.2@538.1,558.89 C34.2@538.1,565.5 v1@538.1,615
MCU_ADC-PGA2: C42.2 R39.2 S7.2 U1.30 | length 1707.2
  Top Layer w6: v1(1205,610) 1220.62,625.62 U1.30@1220.62,660.43
  Top Layer w12: v1(585,410) 585,365 S7.2@590,360
  Mid-Layer 3 w6: v1(585,410) 585,435 640,490 1020.86,490 1120.86,590 1165,590 1185,610 v1(1205,610)
  Mid-Layer 4 w6: v1@90,736 89,735 89,665 112,642 399,642 443,598 443,528.46 427,512.46 427,492 451,468 452.46,468 463,457.46 463,456 491,428 567,428 v1(585,410)
  Bottom Layer w6: R39.2@13.1,683.9 79.9,683.9 88,692 88,733 v1(90,735)
MCU_ADC-PGA2OF: C35.2 S7.15 U1.36 | length 986.9
  Top Layer w6: v1(1320,605) 1320,606 1338.73,624.73 U1.36@1338.73,660.43
  Top Layer w12: v1(585,614) 588.1,617.1 S7.15@588.1,662.4
  Mid-Layer 3 w6: v1(585,614) 586,614 635,565 1040,565 1130,655 1300,655 1320,635 v1(1320,605)
  Bottom Layer w12: v1(585,614) 588.1,617.1 C35.2@588.1,655.91
MCU_ADC-PGA3: C43.2 R40.2 S7.3 U1.20 | length 1628.3
  Top Layer w6: v1@1027.5,837.5 1038.23,826.77 U1.20@1073.97,826.77
  Top Layer w12: v1@635,408.8 635.8,408 v1(639,408) 639,369 635,365 S7.3@640,365
  Mid-Layer 3 w6: v1@84,257 84,201 101,184 395.86,184 418,206.14 418,255.86 474.14,312 543,312 v1@633,402
  Mid-Layer 4 w6: v1(639,408) 639,409 760.5,530.5 872.5,530.5 965,623 965,805 971,811 996,811 v1(1025,840)
  Bottom Layer w6: R40.2@13.1,305.9 C43.2@87.1,305.9 ; v1@88.1,260.1 C43.2@88.1,305.9
  other v1: 85,255
MCU_ADC-PGA3OF: C36.2 S7.14 U1.7 | length 886.8
  Top Layer w6: v1(1023,1073) 1028,1073 1037.67,1082.67 U1.7@1073.97,1082.67
  Top Layer w12: v1(635,615) 638.1,618.1 S7.14@638.1,662.4
  Mid-Layer 4 w6: v1@630,615 v1(635,615) 640,615 675,650 735.86,650 925,839.14 925,879.14 970.86,925 1015,925 1055,965 1055,1060 1042,1073 v1(1023,1073)
  Bottom Layer w12: v1(635,615) 638.1,611.9 C36.2@638.1,565.5 C36.2@638.1,558.89
MCU_ADC-PGA4: C44.2 R42.2 S7.4 U1.31 | length 1796.4
  Top Layer w6: v1(1225,580) 1232,580 1240,588 1240,626.39 1240.3,626.7 U1.31@1240.3,660.43
  Top Layer w12: v1(684,411) 684,371 S7.4@690,365
  Mid-Layer 3 w6: v1@-16,225 35,174 400,174 428,202 428,248.46 478.54,299 577,299 603,325 ; 602,323 v1@681,402 ; v1(684,411) 684,443 721,480 1025,480 1125,580 v1(1225,580)
  Bottom Layer w6: C44.2@-141.9,305.9 R42.2@-70.9,305.9 ; R42.2@-66.9,305.9 -66.9,272.68 -55.73,261.51 -55.73,260.73 -44,249 -39,249 -14,224 v1(-14,217)
  Bottom Layer w12: R42.2@-66.9,305.9 R42.2@-65.9,305.9
MCU_ADC-PGA4OF: C37.2 S7.13 U1.39 | length 985.9
  Top Layer w6: U1.39@1397.79,660.43 1397.79,737.21 1400.57,740 v1(1402,740)
  Top Layer w12: v1(685,614) 688.1,617.1 S7.13@688.1,662.4
  Mid-Layer 3 w6: v1(685,614) 686,614 720,580 1029.14,580 1119.14,670 1355,670 1402,717 v1(1402,740)
  Bottom Layer w12: v1(685,614) 688.1,617.1 C37.2@688.1,655.91
MCU_ADC-PGA5: C45.2 R43.2 S7.5 U1.16 | length 1131.2
  Top Layer w6: U1.16@1073.97,905.51 1127.49,905.51 v1(1155,878) v1@1156,877
  Top Layer w12: S7.5@738.1,362.4 738.1,316.9 745,310 v1(785,310)
  Mid-Layer 4 w6: v1(785,310) 1097,622 1097,820 v1(1155,878)
  Bottom Layer w12: v1(785,310) 820,310 850,280 R43.2@850,210 ; R43.2@849.6,212.4 849.59,139.59 C45.2@850,140
MCU_ADC-PGA5OF: C38.2 S7.12 U1.6 | length 865.1
  Top Layer w6: U1.6@1073.97,1102.36 1127.64,1102.36 v1(1154,1076) v1@1155,1075
  Top Layer w12: v1(735,615) 738.1,618.1 S7.12@738.1,662.4
  Mid-Layer 4 w6: v1(735,615) 735,635 935,835 935,875 975,915 1030,915 1090,975 1090,1014 1152,1076 v1(1154,1076)
  Bottom Layer w12: C38.2@738.1,558.89 v1@738.1,615
MCU_ADC-PGA6: C46.2 R45.2 U1.28 | length 1131.5
  Top Layer w6: v1(1125,535) 1125,559.54 1181.25,615.79 U1.28@1181.25,660.43
  Mid-Layer 3 w6: v1@460,85 460,101 703,344 815,344 921,450 1040,450 v1(1125,535)
  Bottom Layer w6: C46.2@384.6,132.4 419.6,132.4 ; 420.4,132.4 R45.2@456.6,132.4 456.6,86.4 v1(460,83)
MCU_ADC-PGA6OF: C39.2 S7.11 U1.37 | length 846.9
  Top Layer w6: U1.37@1358.41,660.43 1358.41,727.41 v1@1370,739
  Top Layer w12: v1(784,614) 788.1,618.1 S7.11@788.1,662.4
  Mid-Layer 3 w6: v1(784,614) 785,615 810,590 1025,590 1115,680 1330,680 1368,718 v1(1368,740)
  Bottom Layer w12: v1(784,614) 788.1,618.1 C39.2@788.1,655.91
MCU_ADC-PGA7: C47.2 R46.2 S7.7 U1.43 | length 1402.7
  Top Layer w6: 1476.53,618.47 U1.43@1476.53,660.43
  Top Layer w12: S7.7@838.1,362.4 844,368.3 v1(844,409)
  Mid-Layer 3 w6: v1@467,262 490.5,285.5 603.5,285.5 689,371 807,371 842,406 v1@841,406 ; v1(844,409) v1@841,406 ; v1@1487,614 1426,553 1200,553 1188,565 1129.54,565 1107,542.46 1107,542 1030,465 900,465 v1@841,406
  Bottom Layer w12: C47.2@385,210 387.6,207.4 R46.2@456.6,207.4 456.6,248.4 467.21,259 v1(468,259)
  other v1: 1485,610
MCU_ADC-PGA7OF: C40.2 S7.10 U1.40 | length 856.6
  Top Layer w6: v1@1395,773 v1(1397,771) 1425,743 1425,709 1417.47,701.47 U1.40@1417.47,660.43
  Top Layer w12: v1(835,615) 838.1,618.1 S7.10@838.1,662.4
  Mid-Layer 3 w6: v1(835,615) 1025,615 1128,718 1292,718 1333,759 1385,759 v1@1394,768
  Bottom Layer w12: v1(835,615) 838.1,611.9 C40.2@838.1,558.89
MCU_GPIO-00: EC1.49 U1.79 | length 2109
  Top Layer w6: v1@775,-17 803,-45 803,-149.64 EC1.49@801.97,-150.67 ; v1@1516,1185 v1(1516,1186) 1516,1195 1555.27,1234.27 U1.79@1555.27,1268.7
  Mid-Layer 4 w6: v1@776,-16 778,-18 822.46,-18 831.73,-8.73 ; 832,-9 843,2 843,55.74 869.26,82 ; 869.28,82 1001,213.72 1001,256 1052,307 1142,307 1180,345 1455,345 1602,492 1602,616 1540,678 1540,734.28 1499,775.28 1499,812.6 1467,844.6 1467,1136 v1@1516,1185
  other v1: 776,-17
MCU_GPIO-01: EC1.51 U1.78 | length 2089
  Top Layer w6: EC1.51@833.46,-150.67 833.46,-82.54 845,-71 v1@845,-24 ; v1(1574,1190) 1574.95,1190.95 U1.78@1574.95,1268.7
  Mid-Layer 4 w6: v1@844.5,-23.5 855,-13 855,53.6 873.4,72 ; 873.43,72 903.71,102.29 ; 904,102 913,111 971,111 1011,151 1011,249.74 1056.26,295 1335,295 1343,303 1431,303 1613,485 1613,621 1550,684 1550,738.43 1509,779.43 1509,816.74 1486.74,839 1486.74,839.26 1479,847 1479,1081.14 1574,1176.14 v1(1574,1190) v1@1576,1192
  other v1: 844,-23
MCU_GPIO-02: EC1.53 U1.77 | length 2103
  Top Layer w6: EC1.53@864.96,-150.67 864.96,24.96 v1@885,45 ; U1.77@1594.64,1268.7 1594.64,1232.36 1605,1222 v1(1646,1222) v1@1648,1222
  Mid-Layer 4 w6: v1(885,44) 910,44 916.52,50.52 985.12,50.52 1051,116.4 1051,126 1157,232 1427.46,232 1658,462.54 1658,635.28 1627,666.28 1627,772 1539,860 1539,1095.46 1646,1202.46 v1(1646,1222)
MCU_GPIO-03: EC1.55 U1.76 | length 2166.3
  Top Layer w6: EC1.55@889.32,-116 889.32,-88.32 881,-80 881,10 903,32 903,43 v1(940,80) ; U1.76@1614.32,1268.7 1614.32,1315.68 1618.64,1320 v1(1640,1320)
  Mid-Layer 4 w6: v1@939,81 957,99 977,99 1021,143 1021,245.6 1060.4,285 1341,285 1348.5,292.5 1434.64,292.5 1623,480.86 1623,626 1560,689 1560,742.57 1519,783.57 1519,821.14 1489,851.14 1489,1077 1615.5,1203.5 1615.5,1250.96 1640,1275.46 v1(1640,1320) ; v1(940,80) v1@940,81
MCU_GPIO-04: EC1.50 U1.75 | length 2184.7
  Top Layer w6: v1(1644,1254) 1666,1254 1682.23,1237.77 U1.75@1682.23,1200.78
  Mid-Layer 4 w6: v1(822,-60) 843,-60 868,-35 868,35.54 867,36.54 867,51.46 877.54,62 982.46,62 1041,120.54 1041,136 1170,265 1364.54,265 1367.54,268 1449.31,268 1645,463.69 1645,634.14 1617,662.14 1617,744.6 1612.8,748.8 ; 1613,749 1582,780 1553.14,780 1539,794.14 1539,830 1529,840 1529,1099.6 1625.5,1196.1 1625.5,1235.5 v1(1644,1254)
  Bottom Layer w6: EC1.50@801.97,-150.67 803,-149.64 803,-79 v1(822,-60)
MCU_GPIO-05: EC1.52 U1.89 | length 2190.7
  Top Layer w6: v1(1345,1320) 1358.41,1306.59 U1.89@1358.41,1268.7
  Mid-Layer 4 w6: v1(815,0) 815,4.54 833,22.54 833,59.88 865.12,92 ; 865.14,92 990,216.86 990,285 1065,360 1455,360 1589,494 1589,613 1530,672 1530,730.14 1489,771.14 1489,808.46 1434,863.46 1434,950.6 1385,999.6 1385,1000 1362,1023 1362,1191 1345,1208 v1(1345,1320)
  Bottom Layer w6: v1(815,0) 815,-22 840,-47 840,-144.13 EC1.52@833.46,-150.67
MCU_GPIO-06: EC1.54 U1.97 | length 2213.7
  Top Layer w6: U1.97@1200.93,1268.7 1200.93,1186.07 v1(1216,1171)
  Mid-Layer 4 w6: v1(815,30) 815,56.02 860.98,102 975,216 975,310 1040,375 1455.86,375 1548,467.14 1548,552.46 1543,557.46 1543,629 1519.7,652.3 1519.7,726.3 1464,782 1463.54,782 1423,822.54 1423,947.46 1349.73,1020.73 1272.27,1020.73 1216,1077 v1@1216,1170 ; v1@1215,1171 v1@1216,1170 ; v1(1216,1171) v1@1216,1170
  Bottom Layer w6: v1(815,30) 863,30 874,19 874,-77 864.96,-86.04 EC1.54@864.96,-150.67
MCU_GPIO-07: EC1.56 U1.84 | length 2014.8
  Top Layer w6: U1.84@1456.84,1268.7 1456.84,1231.16 1488.5,1199.5 1488.5,1076.5 v1(1510,1055)
  Mid-Layer 4 w6: v1@976,78 1031,133 1031,241.46 1064.54,275 1349,275 1355,281 1439,281 1635,477 1635,630 1607,658 1607,740.46 1579.46,768 1551,768 1529,790 1529,825.28 1510,844.28 v1(1510,1055)
  Bottom Layer w6: EC1.56@889.32,-111 889.32,-96.32 887,-94 887,20 928,61 956,61 v1(975,80)
MCU_GPIO-08: S3.5 U1.74 | length 1209.5
  Top Layer w6: S3.5@1602.17,252.4 1639.4,252.4 v1@1656,269
  Top Layer w12: U1.74@1682.23,1181.1 1711.1,1181.1 1725,1195 v1(1725,1225)
  Mid-Layer 8 w6: v1(1656,268) 1657,268 1827,438 1827,728 1821,734 1821,777 1756,842 1756,1006 1749,1013 1749,1114.54 1750,1115.54 1750,1203 v1@1728,1225
MCU_GPIO-09: EC1.71 U1.90 | length 1854.2
  Top Layer w6: v1(1250,15) 1270,-5 1270,-75 1274.41,-79.41 EC1.71@1274.41,-150.67 ; v1@1329,1084 1318,1095 1318,1196.46 1339,1217.46 1339,1268.43 U1.90@1338.73,1268.7
  Mid-Layer 8 w6: v1(1250,15) 1250,236 1318,304 1463.86,304 1618.71,458.86 1618.71,673.29 1560,732 1560,740.57 1519,781.57 1519,822 1443,898 1443,1062.46 1427.46,1078 1336,1078 v1@1330,1084
  other v1: 1330,1085
MCU_GPIO-10: S2.2 U1.93 | length 1453.3
  Top Layer w6: U1.93@1279.67,1268.7 1279.67,1192.33 1289,1183 v1@1289,1145 ; S2.2@1325.27,252.4 1377.6,252.4 v1(1380,250)
  Mid-Layer 8 w6: v1(1289,1139) 1298,1130 1444,1130 1450,1124 ; v1(1380,250) 1379,250 1399,270 1461,270 1643.86,452.86 1643.86,753.14 1507,890 ; 1450.07,1124.07 1470,1104.14 1470,1028 1507,991 1507,890 ; 1506,891 1507,890
MCU_GPIO-11: EC1.73 U1.52 | length 1300.4
  Top Layer w6: v1(1290,-65) 1305.9,-80.9 EC1.73@1305.9,-150.67 ; U1.52@1682.23,748.03 1731.97,748.03 1749,731 1798,731 v1@1801,734
  Mid-Layer 4 w6: v1(1290,-65) 1290,-50.46 1312,-28.46 1312,-9 1367.73,46.73 1408.73,46.73 1568,206 1653.46,206 1675,227.54 1675,275 1797,397 v1(1797,732)
MCU_GPIO-12: J1.1 R3.2 U1.51 | length 688.4
  Top Layer w6: U1.51@1682.23,728.34 1721.66,728.34 v1(1730,720)
  Mid-Layer 3 w6: v1(1730,720) 1730,700 1720,690 1720,671 1734,657 1853.14,657 1867.64,642.5 1947.5,642.5 1997,692 2134,692 J1.1@2176,734
  Bottom Layer w6: R3.2@2096,733 2097.75,734.75 J1.1@2173.62,734.75
MCU_GPIO-13: J1.3 R4.2 U1.50 | length 690.4
  Top Layer w6: U1.50@1614.32,660.43 1694.57,660.43 v1(1708,647)
  Mid-Layer 3 w6: v1(1708,647) 1849,647 1863.5,632.5 1951.64,632.5 2000.14,681 2148,681 J1.3@2174,655 ; J1.3@2181.31,663.69 J1.3@2185,660
  Bottom Layer w6: R4.2@2098,655 2099.01,656.01 J1.3@2173.62,656.01 ; J1.3@2180,655 J1.3@2185,660
MCU_GPIO-14: EC1.61 U1.96 | length 1887.7
  Top Layer w6: EC1.61@1116.93,-150.67 1116.93,-66.93 1118.86,-65 v1(1120,-65) ; U1.96@1220.62,1268.7 1220.62,1201.38 v1@1249,1173
  Mid-Layer 8 w6: v1(1120,-65) 1142,-43 1142,253 1265,376 1473,376 1555,458 1555,572 1545,582 1545,678.98 1520,703.98 1520,724 1371,873 1371,922 1340,953 1310,953 1246,1017 1246,1109 1255,1118 1255,1150 1248,1157 v1(1248,1172) ; v1@1248,1174 v1@1249,1173
MCU_GPIO-15: EC1.63 U1.95 | length 1884.9
  Top Layer w6: EC1.63@1148.42,-150.67 1148.42,-46.58 1170,-25 v1(1170,-22) ; U1.95@1240.3,1268.7 1240.3,1211.7 1271,1181 1271,1056 v1(1276,1051)
  Mid-Layer 8 w6: v1@1171,-22 1188,-5 1188,22.46 1187,23.46 1187,260.86 1282.14,356 1484,356 1595,467 1595,661 1540,716 1540,732.28 1499,773.28 1499,812.6 1482.6,829 1482,829 1404.5,906.5 1404.5,947.5 1347.5,1004.5 1322.5,1004.5 v1(1276,1051)
MCU_GPIO-16: EC1.67 U1.54 | length 1358.2
  Top Layer w6: v1(1210,-65) 1211.42,-66.42 EC1.67@1211.42,-150.67 ; U1.54@1682.23,787.4 1714,787.4 1721.4,780 1788,780 v1(1803,765) ; v1@1801,763 v1@1804,760
  Mid-Layer 4 w6: v1(1210,-65) 1232,-43 1257.46,-43 1271,-29.46 1271,-13.54 1281.54,-3 1299,-3 1574,272 1604,272 1635,303 1668,303 1779,414 1779,739.46 1803,763.46 v1(1803,765)
MCU_GPIO-17: EC1.69 U1.55 | length 1352
  Top Layer w6: EC1.69@1242.91,-150.67 1242.91,-72.09 v1(1250,-65) ; U1.55@1682.23,807.08 1723.92,807.08 v1@1731,800
  Mid-Layer 8 w6: v1(1250,-65) 1268,-83 1391,-83 1431,-43 1472.46,-43 1488,-27.46 1488,-19 1514.5,7.5 1514.5,238.33 1748,471.83 1748,727.46 1731,744.46 v1(1731,801)
MCU_GPIO-18: R7.2 R16.2 U1.68 | length 240.8
  Top Layer w6: U1.68@1682.23,1062.99 1736.01,1062.99 v1(1776,1023) v1@1780,1019
  Bottom Layer w6: v1@1778,1021 1791.6,1007.4 R16.2@1826.6,1007.4 ; R7.2@1833.5,1080 1833.5,1011.5 R16.2@1835,1010
MCU_GPIO-22: L3.2 R19.1 R22.2 U1.83 | length 477.7
  Top Layer w12: v1@1286,1484 1353,1484 L3.2@1360,1477 ; R22.2@1288.1,1433.9 v1@1288.1,1481.9 ; L3.2@1350.63,1465 1350.63,1414.37 1359,1406 1449,1406 1460,1395 1460,1319 1476.53,1302.47 U1.83@1476.53,1268.7
  Bottom Layer w20: v1(1285,1484) 1285,1485 1286.5,1483.5 R19.1@1286.5,1435
MCU_GPIO-23: R18.1 R21.2 R24.2 U1.81 | length 253.2
  Top Layer w12: U1.81@1515.9,1268.7 1515.9,1307.1 ; R21.2@1515.9,1365.9 R21.2@1517,1364.79 ; 1516,1307 1515.9,1307.1 ; R21.2@1518,1373 R21.2@1520.1,1370.9 ; R24.2@1594.48,1437.4 R18.1@1594.48,1370.52 ; R18.1@1595,1370 R18.1@1594.48,1370.52 ; 1515.9,1307.1 1515.9,1310.9 1523,1318 1523,1368 R21.2@1520.1,1370.9 ; R21.2@1520.1,1370.9 1594.1,1370.9 R18.1@1594.48,1370.52
MCU_GPIO-24: R25.2 S1.2 S5.2 U1.56 | length 1649.9
  Top Layer w6: U1.56@1680,827 U1.56@1682.23,827 ; U1.56@1682.23,826.77 1713.23,826.77 1721,819 1790,819 v1@1843,766 ; S1.2@1843.1,1912.4 v1@1843.1,1869.1 ; v1(1890,600) 1892.4,602.4 S5.2@1940.93,602.4 ; v1(1843,1867) v1@1843,1869 ; v1(1843,1867) 1842,1868 v1@1843,1869 ; v1(1843,1867) 1843.1,1866.9 v1@1843.1,1869.1 ; v1@1843,1869 v1@1843.1,1869.1
  Mid-Layer 4 w6: v1(1843,1867) 1802,1826 1802,1232.54 1820,1214.54 1820,830.25 1849,801.25 v1(1849,763) 1849,641 1889,601 v1@1891,601
  Bottom Layer w6: v1(1843,1867) 1843,1868 1843.1,1868.1 R25.2@1843.1,1831.02
MCU_GPIO-25: S5.5 U1.57 | length 445.3
  Top Layer w6: U1.57@1682.23,846.45 1709.69,846.45 1722,834.14 1722,834 1788,834 v1@1798.5,844.5 ; S5.5@1795.27,602.4 1848.6,602.4 v1(1849,602)
  Mid-Layer 8 w6: v1@1801,846 v1(1799,844) 1799,816 1831,784 1831,742.14 1841.07,732.07 ; 1841,732 1849,724 v1(1849,602)
MCU_GPIO-26: J1.5 R5.2 U1.58 | length 982.8
  Top Layer w6: U1.58@1682.23,866.14 1718.41,866.14 1731,853.54 v1(1731,853)
  Mid-Layer 3 w6: v1(1731,853) 1713,835 1713,789 1685,761 1685,642 1747,580 2021.14,580 2091.14,510 2135,510 2139,514 2139,528 2144.09,533.09 2170.09,533.09 2175,538 2175,571 J1.5@2183,579
  Bottom Layer w6: R5.2@2088,568 2097.27,577.27 J1.5@2173.62,577.27
MCU_GPIO-27: J1.7 R6.2 U1.59 | length 975.9
  Top Layer w6: U1.59@1682.23,885.82 1714.82,885.82 1717,888 v1(1732,888)
  Mid-Layer 3 w6: v1(1732,888) 1703,859 1703,793.14 1675,765.14 1675,637.86 1742.86,570 2017,570 2088.47,498.53 J1.7@2173.62,498.53 ; J1.7@2180,500 2185,495 J1.7@2190,495
  Bottom Layer w6: R6.2@2092,495 2095.53,498.53 J1.7@2173.62,498.53
MCU_GPIO-28: EC1.76 U1.1 U8:A.9 | length 2838.4
  Top Layer w6: U1.1@1073.97,1200.78 v1@1073.97,1265.97 ; U8:A.9@1430.05,1669.27 v1@1479.27,1669.27 ; v1(1481,1669) 1479.55,1669 v1@1479.27,1669.27 ; v1@1483,1670 1482.27,1669.27 v1@1479.27,1669.27
  Mid-Layer 8 w6: v1@1075,1266 1084,1257 1119.46,1257 1133,1243.46 1133,1242 1172,1203 1324.54,1203 1328.54,1207 1450,1207 1458,1199 1458,1130.28 1480,1108.28 1480,1034 1517,997 1517,898 1575,840 1575.43,840 1654,761.43 1654,448.54 1435.46,230 1368,230 1330,192 v1(1330,-19) ; v1@1076,1266 v1(1076,1267) 1076,1396 1097,1417 1097,1498 1186,1587 1391,1587 1438,1634 1446,1634 v1(1481,1669)
  Bottom Layer w6: v1(1330,-19) 1330,-46 1337,-53 ; EC1.76@1337.4,-150.67 1337.4,-53
MCU_GPIO-29: EC1.78 U1.100 U8:A.13 | length 2843.5
  Top Layer w6: U1.100@1141.88,1268.7 v1@1141.88,1322 ; v1(1610,1685) 1619.87,1694.87 U8:A.13@1662.34,1694.87
  Mid-Layer 8 w6: v1@1141,1323 v1(1142,1322) 1142,1515 1153,1526 ; v1@1143,1323 1186,1323 1198,1335 1214.46,1335 1225,1324.46 1225,1317 1298,1244 1446,1244 1478,1212 1478,1138.57 1537,1079.57 1537,906.72 1680,763.72 1680,635.4 1691.2,624.2 ; 1153.5,1525.5 1204,1576 1439,1576 1547,1684 v1@1611,1684 ; v1(1369,-21) 1370,-21 1388,-3 1388,133 1449.37,194.37 1449.37,215.63 1716,482.26 1716,599 1691,624 ; v1@1608,1687 v1@1610,1689
  Bottom Layer w6: EC1.78@1368.9,-150.67 1368.9,-24.1 v1@1369,-24
MCU_GPIO-30: EC1.80 U1.98 | length 1970.7
  Top Layer w6: U1.98@1181.25,1268.7 1181.25,1312.25 1186,1317 v1(1207,1317)
  Mid-Layer 8 w6: v1(1207,1317) 1207,1290 1274,1223 1452,1223 1468,1207 1468,1134.43 1495,1107.43 1495,1065.46 1492,1062.46 1492,1040 1527,1005 1527,902.57 1665.63,763.94 1665.63,446.03 1438,218.4 1438,201 1370,133 v1(1370,15)
  Bottom Layer w6: v1(1370,15) 1400.39,-15.39 EC1.80@1400.39,-150.67
MCU_GPIO-31: EC1.74 R12.1 U1.99 U2.1 | length 3290.4
  Top Layer w6: v1@1115,1227 1121,1221 1153,1221 1161.56,1229.56 U1.99@1161.56,1268.7 ; v1(2125,1505) 2128.5,1508.5 U2.1@2128.5,1546.73
  Mid-Layer 3 w6: v1(1115,1236) 1122,1236 1159,1273 1938.46,1273 2082.5,1417.04 2082.5,1424.5 ; 2083,1424 2125,1466 v1(2125,1505)
  Mid-Layer 8 w6: v1(1115,1236) 1115,1228 1152,1191 1255,1191 1270,1176 1270,1132.54 1291.54,1111 1343,1111 1366,1088 1434,1088 1454,1068 1454,903 1529,828 1529,802 1558,773 1580.86,773 1631.78,722.07 1631.78,457.78 1468,294 1357,294 1290,227 v1(1290,15)
  Bottom Layer w6: v1(1290,15) 1308,-3 1308,-72.46 1305.9,-74.55 EC1.74@1305.9,-150.67 ; v1(2125,1505) R12.1@2125,1552.76
MCU_GPIO-32: EC1.82 R26.1 S1.1 U1.64 | length 2629.3
  Top Layer w6: U1.64@1682.23,984.25 1714.25,984.25 v1(1730,1000) ; S1.1@1893.1,1912.4 1893.1,1866.9 1894,1866 1896,1868 v1(1896,1867)
  Mid-Layer 4 w6: v1@1423,12 1423,43 1575,195 1669,195 1810,336 1810,704 1821,715 1821,773.46 1784.46,810 1783.86,810 1765,828.86 1765,829 1756,838 1756,974 v1(1730,1000) 1705,1025 1705,1131 1768,1194 1768,1288 1792,1312 1792,1882 1820,1910 1855,1910 1896,1869 v1(1896,1867) 1898,1867 v1@1900,1865
  Bottom Layer w6: v1(1422,13) 1422,-73 1431.89,-82.89 EC1.82@1431.89,-150.67 ; v1(1896,1867) 1896,1870 1898.1,1867.9 R26.1@1898.1,1831.02
MCU_GPIO-33: EC1.105 U1.53 | length 1156.2
  Top Layer w6: U1.53@1682.23,767.71 1763.29,767.71 v1(1772,759) ; EC1.105@1809.84,-150.67 1809.84,-84.84 1810,-84.68 v1(1810,-16)
  Mid-Layer 8 w6: v1@1772,758 1778,752 1778,403.14 1670.86,296 1651,296 1625,270 1625,209 1810,24 v1(1810,-16)
MCU_GPIO-34: EC1.86 R13.1 U1.94 U2.3 | length 3059.2
  Top Layer w6: v1(1255,1320) 1259.99,1315.01 U1.94@1259.99,1268.7 ; 2203.31,1511.69 U2.3@2203.31,1546.73
  Mid-Layer 3 w6: v1(1255,1320) 1261,1320 1334,1393 1831,1393 1852,1414 1852,1417.46 1972.54,1538 2180,1538 2206,1512
  Mid-Layer 8 w6: v1@1251,1320 1251,1318.54 1315.54,1254 1455,1254 1488,1221 1488,1148 1547,1089 1547,910.86 1690,767.86 1690,639.54 1726,603.54 1726,478.12 1486,238.12 1486,41 v1@1469,24
  Bottom Layer w6: v1(1470,24) 1494.88,-0.88 EC1.86@1494.88,-150.67 ; R13.1@2205,1551.38 2206,1550.38 v1(2206,1501)
MCU_GPIO-35: S4.2 U1.63 | length 1391.7
  Top Layer w6: S4.2@1020.27,252.4 1072.4,252.4 v1(1074,254) ; U1.63@1682.23,964.56 1725.44,964.56 v1(1730,960)
  Mid-Layer 3 w6: v1@1065,255 1060,255 1030,285 1030,336.72 1053.28,360 1490,360 1630,500 1630,760.14 1679,809.14 1679,934 1705,960 v1(1730,960)
  Mid-Layer 7 w6: v1@1072,256 1071,255 1072,254 v1(1074,254)
MCU_GPIO-37: S4.5 U1.61 | length 1341
  Top Layer w6: v1(1113,254) 1114,253 1165.33,253 S4.5@1165.93,252.4 ; U1.61@1682.23,925.19 v1@1724.81,925.19
  Mid-Layer 3 w6: v1(1113,254) 1113,257 1090,280 1065,280 1050,295 1050,342.57 1057.43,350 1494.14,350 1640,495.86 1640,756 1689,805 1689,880 1729,920 v1(1730,920)
MCU_GPIO-39: EC1.62 U1.91 | length 1875.5
  Top Layer w6: U1.91@1319.04,1268.7 U1.91@1319.04,1268.7 1319,1211.6 1308,1200.6 1308,1118 1305,1115 1305,993 v1@1323,975
  Mid-Layer 8 w6: v1(1170,15) 1170,258 1278,366 1479,366 1585,472 1585,653 1558,680 ; v1@1323,975 1331.5,966.5 1360.5,966.5 1386,941 1386,910.86 1477.86,819 1478.46,819 1489,808.46 1489,770 1488.57,769.57 1530,728.14 1530,708.12 1558.06,680.06
  Bottom Layer w6: EC1.62@1116.93,-150.67 1116.93,-93.07 1127,-83 1127.46,-83 1138.42,-72.03 1138.42,-52.58 1151,-40 1151,4.15 1161.85,15 v1(1170,15)
  other v1: 1324,975
MCU_GPIO-40: EC1.68 U1.85 | length 1820.1
  Top Layer w6: v1@1421,1056 1470,1105 1470,1195 1437.16,1227.84 U1.85@1437.16,1268.7
  Mid-Layer 8 w6: v1(1209,-19) 1228,0 1228,261 1313,346 1490,346 1606.64,462.64 1606.64,666.36 1550,723 1550,736.43 1509,777.43 1509,817.86 1422,904.86 v1(1422,1058) 1422,1060 v1@1420,1062
  Bottom Layer w6: v1(1209,-19) 1209,-34 1192,-51 1192,-72.46 1211.42,-91.87 EC1.68@1211.42,-150.67
MCU_GPIO-56: EC1.103 U1.65 | length 1448.5
  Top Layer w6: v1(1600,975) 1618,975 1646.93,1003.93 U1.65@1682.23,1003.93 ; EC1.103@1778.35,-150.67 1778.35,-66.65 v1(1780,-65)
  Mid-Layer 8 w6: v1@1599,975 v1(1600,975) ; v1@1600,976 1688,888 1688,869 1728,829 1742.6,829 1759,812.6 1759,774 1754,769 1754,751.54 1764.54,741 1765,741 1768,738 1768,407.28 1666.72,306 1646.86,306 1615,274.14 1615,202 1780,37 v1(1780,-65)
MCU_GPIO-57: EC1.70 U1.66 | length 1578.5
  Top Layer w6: v1@1597,1014 1606.62,1023.62 U1.66@1682.23,1023.62
  Mid-Layer 4 w6: v1(1250,-19) 1243,-19 1270,8 1270,30 1278,38 1315,38 1562,285 1563,285 1746,468 1746,650 1673,723 1673,786 1579,880 1579,993 v1@1598,1012
  Bottom Layer w6: EC1.70@1242.91,-150.67 1242.91,-83.37 1232,-72.46 1232,-43 1250,-25 v1(1250,-19)
  other v1: 1598,1011
MCU_GPIO-58: EC1.99 U1.67 | length 1355.5
  Top Layer w6: U1.67@1682.23,1043.3 1726.7,1043.3 1752,1018 1752,997.54 1775,974.54 v1(1775,959) ; v1(1698,-18) 1699,-18 1718,-37 1718,-72.46 1715.35,-75.1 EC1.99@1715.35,-150.67
  Mid-Layer 4 w6: v1(1698,-18) 1698,121 1701,124 1700,125 1812.5,237.5 ; v1@1775,961 v1(1775,959) v1@1775,957 ; v1@1779,961 v1@1775,957 ; 1813,237 1823,247 1823,700 1831,708 1831,782 1775,838 v1@1775,957
MCU_GPIO-59: EC1.101 U1.92 | length 1967.2
  Top Layer w6: U1.92@1299.36,1268.7 1299.36,1320.36 1302,1323 v1(1302,1320) ; v1(1740,-65) 1745,-65 1746.85,-66.85 EC1.101@1746.85,-150.67
  Mid-Layer 8 w6: v1@1302,1323 v1(1302,1320) 1305,1320 1351,1274 1487,1274 1545,1216 1545,1125 1574,1096 1574,934 1588,920 1622.86,920 1723.86,819 1738.46,819 1749,808.46 1749,789.54 1743,783.54 1743,748.4 1758,733.4 1758,467.69 1598,307.69 1598,204.86 1740,62.86 v1(1740,-65)
MCU_TCK: EC1.5 U1.60 U8:A.16 | length 3628.2
  Top Layer w6: EC1.5@109.05,-150.67 109.05,-50.95 v1(140,-20) v1@141,-19 ; v1(1605,896) 1614.51,905.51 U1.60@1682.23,905.51 ; v1(1610,1775) 1613.36,1771.64 U8:A.16@1662.34,1771.64
  Mid-Layer 3 w6: v1(140,-20) 155,-35 194.6,-35 234.8,-75.2 ; 235,-75 245,-85 790.46,-85 803,-72.46 803,-13.46 797,-7.46 797,37.46 807.54,48 808,48 1010,250 1010,345 1045,380 1480,380 1608,508 1608,897 1607,896 v1(1605,896)
  Mid-Layer 4 w6: v1@1605,897 1624,916 1661,916 1685,940 1685,1133 1750,1198 1750,1371 1775,1396 1775,1693 1744,1724 1661,1724 v1(1610,1775)
MCU_TMS: EC1.3 R31.1 U1.62 U8:A.14 | length 3847.2
  Top Layer w6: EC1.3@77.56,-150.67 77.56,-73.01 72,-67.46 72,-35 v1@88,-19 ; v1@1597,937 v1(1600,940) 1604.88,944.88 U1.62@1682.23,944.88 1685.11,942 1763,942 1780,925 1820,925 R31.1@1825,920 ; v1(1610,1725) 1614.54,1720.46 U8:A.14@1662.34,1720.46
  Mid-Layer 3 w6: v1(87,-19) 110,-42 146.46,-42 149.46,-45 190.46,-45 240.46,-95 812.46,-95 840,-67.46 840,-44.46 826,-30.46 826,-15.54 840,-1.54 840,65.86 1020,245.86 1020,340.86 1049.14,370 1485,370 1620,505 1620,764.28 1624,768.28 1624,914 v1@1599,939
  Mid-Layer 4 w6: v1@1602,940 1653,940 1670,957 1670,1138 1702,1170 1702,1302 1734,1334 1734,1380 1763,1409 1763,1677 1728,1712 1623,1712 v1(1610,1725)
MCU_X1: C23.1 R17.2 U1.69 Y1.3 | length 359.4
  Top Layer w6: U1.69@1682.23,1082.67 1727.67,1082.67 1750,1105 1750,1128 1769,1147 Y1.3@1810,1147 ; Y1.3@1821.52,1173.5 1821.52,1238.52 v1(1822,1239)
  Bottom Layer w6: v1@1820,1240 1823.5,1243.5 R17.2@1823.5,1286.5 ; C23.1@1821.38,1360 1821.38,1288.62 R17.2@1823.5,1286.5 ; R17.2@1823.5,1290 R17.2@1823.5,1286.5
MCU_XRSN: C29.2 EC1.120 R27.1 R29.2 TP5.1 U1.2 | length 3103.5
  Top Layer w6: U1.2@1073.97,1181.1 1107.1,1181.1 1112,1186 1112,1206.54 1097,1221.54 1097,1269 v1@1111,1283 ; TP5.1@2055,1450 2057.6,1447.4 R29.2@2164.48,1447.4
  Mid-Layer 3 w6: v1@1108,1286 1111,1283 1768.46,1283 1888,1402.54 1888,1412 1929,1453 TP5.1@2061,1453
  Mid-Layer 4 w6: v1(2010,-65) 2010,320 2038,348 2038,681.54 2037,682.54 2037,1027 2054,1044 TP5.1@2054,1448
  Bottom Layer w6: v1(2010,-65) 2030.31,-85.31 EC1.120@2030.31,-150.67 ; TP5.1@2055,1445 2057.4,1447.4 R27.1@2164.48,1447.4 ; C29.2@2159.48,1367.4 R27.1@2159.48,1444.48
  other v1: 1110,1285
MID_SCI-RX: U5:A.6 U8:A.11 | length 879.8
  Top Layer w6: U5:A.6@883.5,1785.87 922.13,1785.87 v1(935,1773) ; v1(1655,1615) 1662.34,1622.34 U8:A.11@1662.34,1643.68
  Mid-Layer 3 w6: v1(935,1773) 1032,1773 1197,1608 1648,1608 v1(1655,1615)
MID_SCI-TX: U7:A.3 U8:A.7 | length 772.4
  Top Layer w6: U7:A.3@885,1320 940,1320 1045,1425 1045,1530 1235.46,1720.46 U8:A.7@1430.05,1720.46
MID_TCK: U6:A.7 U8:A.4 | length 646.8
  Top Layer w6: U6:A.7@890,1585 919.54,1585 927.54,1593 974,1593 1198,1817 1328,1817 1347.77,1797.23 U8:A.4@1430.05,1797.23
  Top Layer w12: U8:A.4@1428.28,1799 U8:A.4@1430.05,1797.23
MID_TDI: U5:A.7 U8:A.2 | length 554.7
  Top Layer w6: U5:A.7@885,1835 1300,1835 1313.41,1848.41 U8:A.2@1430.05,1848.41
  Top Layer w12: U5:A.7@883.5,1835.87 U5:A.7@886.37,1833
MID_TDO: U7:A.2 U8:A.12 | length 946.7
  Top Layer w6: U7:A.2@883.5,1265.87 886.64,1269 934,1269 1215,1550 1315,1550 1378.38,1613.38 1504.17,1613.38 1545.79,1655 ; 1545,1655 1545.79,1655 ; U8:A.12@1662.34,1669.27 1624.27,1669.27 1615,1660 1550.79,1660 1545.79,1655
MID_TMS: U6:A.6 U8:A.6 | length 647.3
  Top Layer w6: U6:A.6@890,1535 975,1535 1186.05,1746.05 U8:A.6@1430.05,1746.05 U8:A.6@1449.88,1746.05
NetC4:A_2: C4:A.2 U1:A.4 | length 160.7
  Top Layer w10: U1:A.4@442.6,1763.98 442.6,1815.08 455.41,1827.9 506.87,1827.9 C4:A.2@535.2,1856.22
NetC13:A_1: C13:A.1 C14:A.2 L1:A.1 U2:A.4 | length 1219.1
  Top Layer w10: v2(-170,1265) -150.97,1245.97 9.2,1245.97 67.67,1304.45 67.67,1337.67 ; 65,1335 67.67,1337.67 ; v2(333.44,1630.72) 353.96,1610.2 353.96,1533.04 390,1497 390,1399.38 344.58,1353.97 156.03,1353.97 v2(150,1360) 90,1360 67.67,1337.67
  Bottom Layer w10: v2(-170,1265) -168.43,1266.57 C14:A.2@-168.43,1309.84 ; U2:A.4@137.64,1429.37 137.64,1379.36 150,1367 v2(150,1360) ; v2(333.44,1630.72) 333.44,1676.22 337.51,1680.29 L1:A.1@347.57,1680.29 348.43,1681.15 C13:A.1@470.54,1681.15
NetC15:A_1: C15:A.1 C16:A.2 L2:A.1 U2:A.9 | length 830.8
  Bottom Layer w10: C16:A.2@128.82,1549.84 128.82,1602.72 C15:A.1@116.69,1614.84 103.85,1627.68 103.85,1657.29 75.2,1685.95 L2:A.1@75.2,1694.84 75.2,1782.28 109.33,1816.42 219.93,1816.42 264.51,1771.83 264.51,1590.85 236.06,1562.4 U2:A.9@236.06,1429.37
NetC17:A_2: C17:A.2 U2:A.2 Y1:A.1 | length 578.7
  Top Layer w6: C17:A.2@-204.8,1368.46 v2@-204.8,1436.81 ; C17:A.2@-203.11,1377.01 -203.11,1437.07 v2(-203.82,1437.79) -182.41,1459.2 12.04,1459.2 v2(47.45,1423.78)
  Bottom Layer w6: Y1:A.1@-203.11,1377.01 v2@-203.11,1437.07 ; v2(47.45,1423.78) 47.45,1409.89 72.53,1384.82 89.38,1384.82 98.27,1393.7 U2:A.2@98.27,1429.37
NetC18:A_2: C18:A.2 U2:A.3 Y1:A.3 | length 383.2
  Bottom Layer w10: Y1:A.3@-116.5,1522.68 -115.04,1521.22 -54.22,1521.22 22,1445 22,1409.55 68.46,1363.09 110.36,1363.09 117.95,1370.68 U2:A.3@117.95,1429.37
NetC26_2: C26.2 U3.4 | length 71.4
  Top Layer w6: U3.4@2135,935 C26.2@2135,1006.38
NetC27_2: C27.2 R20.1 R23.1 U3.5 | length 241.3
  Top Layer w12: R20.1@1970,930 U3.5@2055,930 ; U3.5@2057.6,934.13 2089,965.54 v1(2089,967) 2089,991 2065,1015 C27.2@2065,1018.5
  Bottom Layer w12: R23.1@2071.38,930 2071.38,948.38 v1@2091,968 ; v1@2088,968 v1@2090,970
NetC28_1: C28.1 R24.1 | length 59
  Top Layer w12: R24.1@1641.72,1437.4 1641.72,1491.72 C28.1@1645,1495
NetC30_2: C30.2 R30.1 TP6.1 U4.6 | length 285.7
  Top Layer w6: C30.2@2205,1185 C30.2@2207.4,1187.4 ; C30.2@2206.72,1187.4 C30.2@2207.4,1187.4 ; U4.6@2210.5,1263.27 2210.5,1190.5 C30.2@2207.4,1187.4 ; TP6.1@2215,1095 2255,1135 v1(2255,1185) 2252.6,1187.4 C30.2@2207.4,1187.4
  Bottom Layer w6: R30.1@2206.72,1187.4 2252.6,1187.4 v1(2255,1185)
NetC60_2: C60.2 S8.4 U1.25 | length 717.2
  Top Layer w6: S8.4@818.1,227.4 867.4,227.4 890,250 v1(890,265) ; v1(1030,700) 1060,700 1073.97,713.97 U1.25@1073.97,728.34
  Mid-Layer 8 w6: v1(890,265) 912,287 912,367 959,414 959,638 1021,700 v1(1030,700)
  Bottom Layer w12: v1@1030,705 v1(1030,700) C60.2@1083.5,700
NetC61_2: C61.2 S8.3 U1.24 | length 841.1
  Top Layer w6: S8.3@818.1,177.4 869.4,177.4 907,215 v1(907,220) ; v1@1024,737 1035.03,748.03 U1.24@1073.97,748.03
  Mid-Layer 8 w6: v1@907,219 860,266 860,345 944,429 944,654 1024,734 v1(1024,738)
  Bottom Layer w12: v1(1024,738) 1051,765 C61.2@1083.5,765
NetD1_2: D1.2 R23.2 | length 172.5
  Top Layer w6: v1(2097,897) 2152,897 2161.06,906.06 D1.2@2223.1,906.06
  Bottom Layer w6: v1(2097,897) 2097,914 2113,930 R23.2@2115.62,930 R23.2@2116,930
NetD2:A_2: D2:A.2 R1:A.2 | length 132.5
  Top Layer w10: v2(315,1890) 360.68,1890 D2:A.2@364.09,1893.41 ; v2@319.93,1892.91 D2:A.2@357.85,1892.91
  Bottom Layer w10: v2(315,1890) 317.91,1892.91 R1:A.2@357.85,1892.91
NetD2_1: D2.1 U2.6 | length 91.5
  Top Layer w6: U2.6@2128.5,1655 D2.1@2128.5,1746.5
NetD2_2: D2.2 R10.2 | length 99.9
  Top Layer w6: v1(2116,1895) 2116.22,1894.78 D2.2@2116.22,1842.2
  Bottom Layer w6: v1(2116,1895) 2116.35,1894.65 R10.2@2116.34,1848.1
NetD3:A_1: D3:A.1 R7:A.2 | length 149.9
  Top Layer w12: v2(-230,975) -230,1020 D3:A.1@-205,1045
  Bottom Layer w12: v2(-230,975) -209.8,995.2 R7:A.2@-209.8,1036.22
NetD3_1: D3.1 U2.4 | length 83.3
  Top Layer w6: U2.4@2203.31,1655 D3.1@2203.31,1738.31
NetD3_2: D3.2 R11.2 | length 89.5
  Top Layer w6: v1(2215,1895) 2215.91,1894.09 D3.2@2215.91,1842.2
  Bottom Layer w6: R11.2@2215.08,1848.61 v1@2215.08,1884.92
NetD4:A_1: D4:A.1 R8:A.2 | length 153.6
  Top Layer w10: v2(-140,975) -140,1015 -116.79,1038.21 D4:A.1@-109.8,1031.22
  Bottom Layer w10: v2(-140,975) -136.24,975 -109.8,1001.43 R8:A.2@-109.8,1031.22
NetEC1_1: EC1.1 R1.2 | length 313.9
  Top Layer w10: R1.2@70.2,148.03 R1.2@71.06,147.17
  Top Layer w12: EC1.1@46.06,-150.67 46.06,-74.94 58,-63 58,59 75,76 R1.2@75,146.38 ; R1.2@70,146.38 R1.2@70,150
NetEC1_2: EC1.2 R2.1 | length 306.8
  Bottom Layer w10: R2.1@70.2,148.03 R2.1@71.06,147.17
  Bottom Layer w12: EC1.2@46.06,-150.67 46.06,41.06 70,65 R2.1@70,145
NetEC1_89: EC1.89 R7.1 | length 1669
  Top Layer w6: EC1.89@1557.87,-150.67 1557.87,-67.13 v1(1560,-65)
  Mid-Layer 8 w6: v1(1560,-65) 1590,-95 1775.46,-95 1798,-72.46 1798,-72 1840,-30 1840,480 1872,512 1872,677.46 1935,740.46 1935,1085 v1(1959,1109)
  Bottom Layer w6: R7.1@1896.5,1080 1930,1080 v1(1959,1109)
NetJ1:A_2: J1:A.2 U2:A.7 U3:A.5 | length 444.4
  Top Layer w10: J1:A.2@49.86,1742.36 v2(126.72,1742.36) v2@126.99,1742.64
  Bottom Layer w10: v2(126.72,1742.36) 148.54,1742.36 155.67,1735.23 155.67,1724.53 176.86,1724.53 184.11,1717.28 184.11,1540.89 196.69,1528.31 U2:A.7@196.69,1429.37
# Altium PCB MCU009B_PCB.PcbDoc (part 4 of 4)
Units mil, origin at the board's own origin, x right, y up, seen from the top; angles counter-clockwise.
Board outline 2657.23 x 2215.46 mil, 10 copper layers (Top Layer, Internal-Plane 2, Mid-Layer 3, Mid-Layer 4, Internal-Plane 5, Internal-Plane 6, Mid-Layer 7, Mid-Layer 8, Internal-Plane 9, Bottom Layer), stack 60.8 mil thick; 232 components, 196 nets, 851 pads, 493 vias.

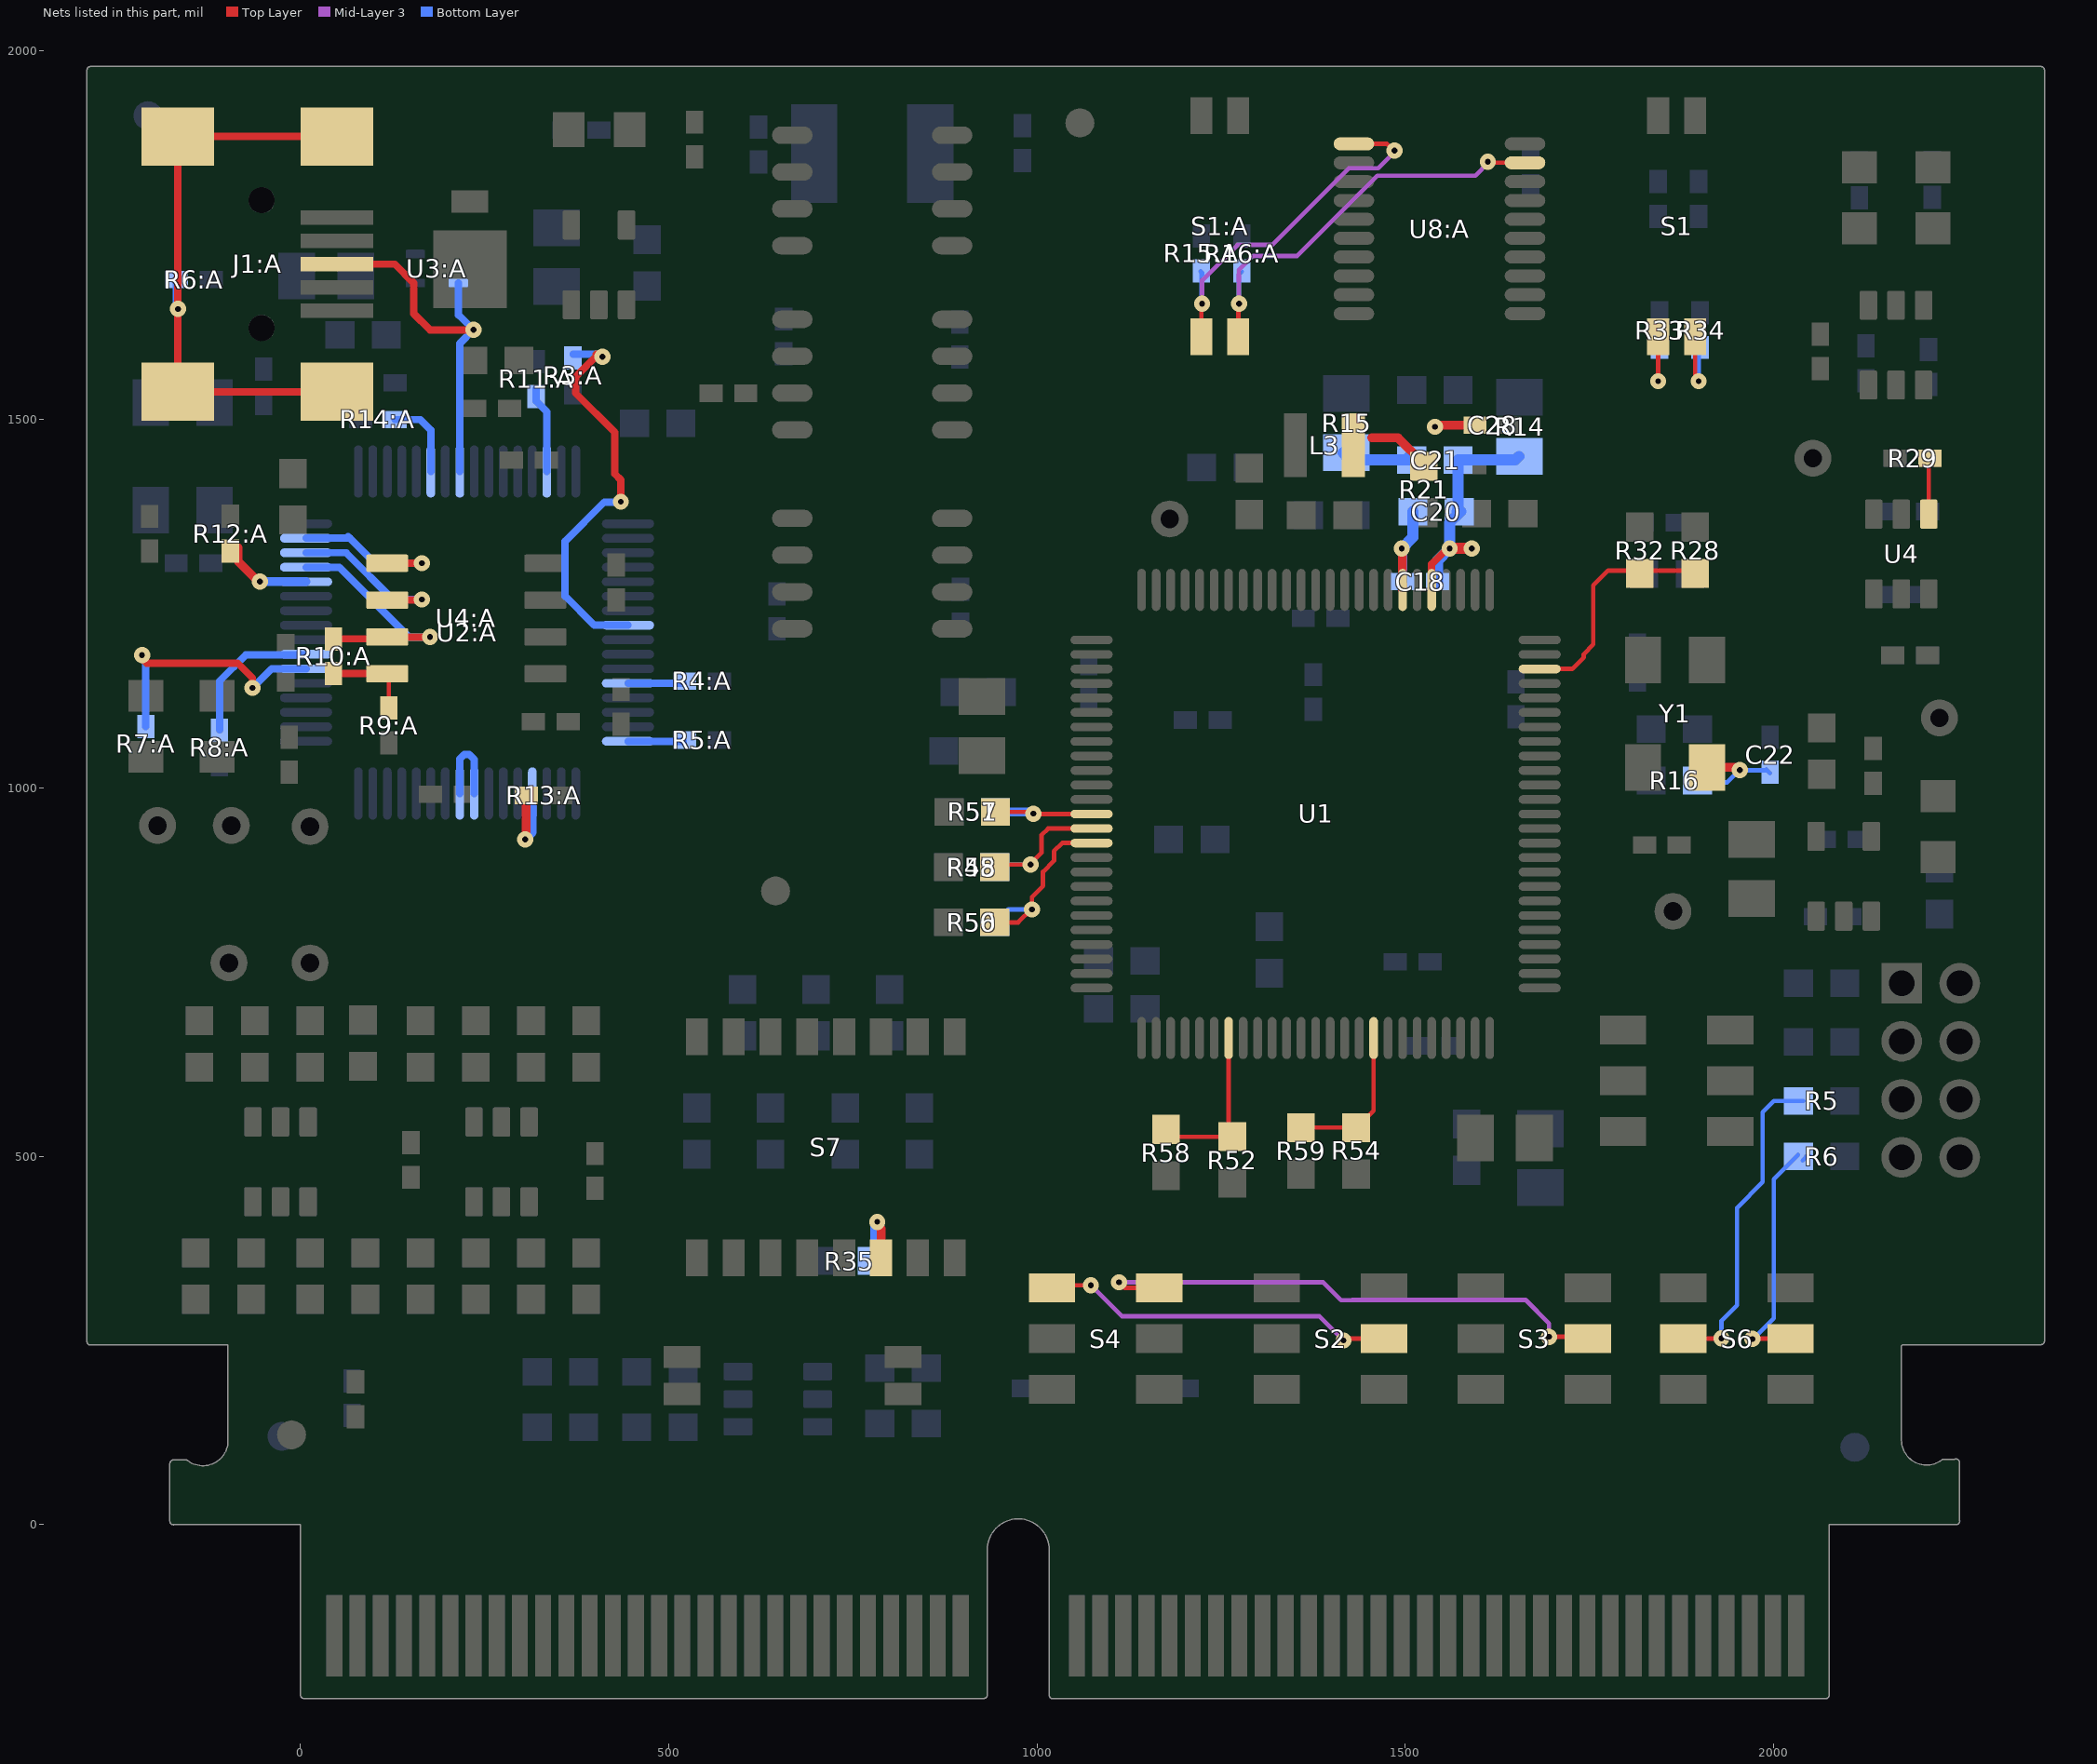
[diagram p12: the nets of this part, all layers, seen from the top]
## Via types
v1: diameter 22, hole 8, Top Layer to Bottom Layer, 414 vias
v2: diameter 22, hole 8, Top Layer to Bottom Layer, tented both sides, 79 vias

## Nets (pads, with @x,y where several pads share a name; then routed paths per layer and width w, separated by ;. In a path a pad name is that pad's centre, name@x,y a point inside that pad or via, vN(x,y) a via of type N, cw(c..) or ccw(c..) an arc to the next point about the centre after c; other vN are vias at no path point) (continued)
NetJ1:A_3: J1:A.3 U2:A.8 U3:A.3 | length 518.3
  Top Layer w10: J1:A.3@49.86,1710.87 128.22,1710.87 153.93,1685.16 153.93,1643.7 175.99,1621.64 v2(234.99,1621.64)
  Bottom Layer w10: U3:A.3@214.72,1685.16 214.72,1641.91 v2(234.99,1621.64) 216.38,1603.02 U2:A.8@216.38,1429.37
NetJ1:A_6: J1:A.6 J1:A.7 J1:A.8 J1:A.9 R6:A.1 | length 817.5
  Top Layer w10: J1:A.7@49.86,1537.64 J1:A.9@-166.67,1537.64 -166.67,1649.29 v2(-165.99,1649.98) -166.67,1650.66 J1:A.8@-166.67,1884.09 J1:A.6@49.86,1884.09
  Bottom Layer w10: v2@-168.43,1652.42 R6:A.1@-168.43,1689.84
NetL3_1: L3.1 R21.1 | length 85.1
  Top Layer w12: 1454.37,1475 1490,1475 R21.1@1525,1440
NetR3:A_2: R3:A.2 U2:A.24 | length 550.5
  Top Layer w10: v2@401.66,1588.46 v2@403.34,1586.79 ; v2(410,1585) 400.96,1585 373.47,1557.5 373.47,1535.88 427,1482.34 427,1426.09 435.01,1418.09 v2(435.01,1388.3) v2@434.61,1387.9
  Bottom Layer w10: R3:A.2@370.2,1588.46 v2@401.66,1588.46 ; v2@434.61,1387.9 412.64,1387.9 359.33,1334.59 359.33,1260.3 398.92,1220.71 U2:A.24@444.72,1220.71
NetR4:A_1: R4:A.1 U2:A.28 | length 74.7
  Bottom Layer w10: U2:A.28@444.72,1141.97 R4:A.1@519.45,1141.97
NetR5:A_1: R5:A.1 U2:A.32 | length 75.2
  Bottom Layer w10: U2:A.32@444.72,1063.23 R5:A.1@519.96,1063.23
NetR7:A_1: R7:A.1 U2:A.54 | length 347.2
  Top Layer w10: v2(-215,1180) -215,1175.64 -208.75,1169.39 -85.22,1169.39 -65.01,1149.18 v2(-65.01,1135.64)
  Bottom Layer w10: R7:A.1@-209.8,1083.46 -209.8,1168.34 ; v2(-65.01,1135.64) -38.99,1161.65 U2:A.54@7.72,1161.65
NetR8:A_1: R8:A.1 U2:A.55 | length 199
  Bottom Layer w10: R8:A.1@-109.8,1078.46 -109.8,1144.84 -74.01,1180.64 7.02,1180.64 U2:A.55@7.72,1181.34
NetR9:A_2: R9:A.2 R10:A.1 U4:A.4 | length 129
  Top Layer w6: U4:A.4@112.18,1149.46 U4:A.4@116.36,1153.64 ; U4:A.4@115,1155 U4:A.4@116.36,1153.64 ; U4:A.4@117.74,1155.02 U4:A.4@116.36,1153.64 ; R9:A.2@120,1108.62 120,1150 116.53,1153.47 U4:A.4@116.36,1153.64
  Top Layer w10: R10:A.1@44.99,1155.02 U4:A.4@117.74,1155.02
NetR10:A_2: R10:A.2 U2:A.61 U4:A.3 | length 339.5
  Top Layer w10: R10:A.2@44.99,1202.26 115.74,1202.26 118.12,1204.64 v2(175.99,1204.64)
  Bottom Layer w10: U2:A.61@7.72,1299.45 52.67,1299.45 147.48,1204.64 v2(175.99,1204.64)
NetR11:A_2: R11:A.2 U2:A.14 | length 117.8
  Bottom Layer w10: R11:A.2@320.2,1541.22 320.2,1524.8 334.49,1510.51 U2:A.14@334.49,1429.37
NetR12:A_2: R12:A.2 U2:A.60 | length 122.6
  Top Layer w12: R12:A.2@-84.8,1326.22 -84.8,1307.8 -57,1280 v1(-55,1280)
  Bottom Layer w12: v1(-55,1280) -54.76,1279.76 U2:A.60@7.72,1279.76
NetR13:A_2: R13:A.2 U2:A.36 | length 126.9
  Top Layer w12: v1(305,930) 306.57,931.57 R13:A.2@306.57,989.84
  Bottom Layer w12: v1(305,930) 314.8,939.8 U2:A.36@314.8,992.36
NetR14:A_2: R14:A.2 U2:A.6 | length 110.3
  Bottom Layer w10: R14:A.2@128.82,1499.84 162.79,1499.84 177.01,1485.62 U2:A.6@177.01,1429.37
NetR15:A_1: R15:A.1 S1:A.1 U8:A.1 | length 549
  Top Layer w6: S1:A.1@1223.1,1612.4 1223.1,1658.1 1224,1657.2 v1(1224,1657) ; U8:A.1@1430.05,1874 1475,1874 1484,1865 v1(1485,1865)
  Mid-Layer 3 w6: v1(1224,1657) 1224,1689 1272,1737 1319,1737 1423,1841 1463,1841 v1@1486,1864
  Bottom Layer w6: R15:A.1@1222,1701 1224,1699 v1(1224,1657) ; v1@1223.1,1666.9 R15:A.1@1223.1,1698.78
NetR16:A_1: R16:A.1 S1:A.2 U8:A.19 | length 589.3
  Top Layer w6: S1:A.2@1273.1,1612.4 1273.1,1658.1 1274,1657.2 v1(1274,1657) ; v1(1611.82,1850) 1613.41,1848.41 U8:A.19@1662.34,1848.41
  Mid-Layer 3 w6: v1(1274,1657) 1274,1703 1293,1722 1353,1722 1462,1831 1595,1831 v1@1613,1849
  Bottom Layer w6: v1(1274,1657) 1274,1696.68 R16:A.1@1278.1,1700.78
NetR28_1: R28.1 R32.1 U1.73 | length 322.1
  Top Layer w6: U1.73@1673,1161.41 U1.73@1682.23,1161.41 1726.41,1161.41 1742,1177 1742,1181.6 1755,1194.6 1755,1275 1775,1295 R28.1@1890,1295
NetR29_1: R29.1 U4.1 | length 69
  Top Layer w6: U4.1@2210.5,1371.53 R29.1@2210.5,1440.5
NetR33_1: R33.1 S1.3 | length 115.7
  Top Layer w6: v1(1843,1552) 1843.1,1552.1 S1.3@1843.1,1612.4
  Bottom Layer w6: v1@1842,1554 1843.1,1555.1 R33.1@1843.1,1608.78
NetR34_2: R34.2 S1.4 | length 121.7
  Top Layer w6: S1.4@1893.1,1612.4 1893.1,1556.9 v1(1898,1552) 1898,1553 v1@1899,1554
  Bottom Layer w6: v1(1898,1552) 1898.1,1552.1 R34.2@1898.1,1608.78
NetR35_2: R35.2 S7.6 | length 98.6
  Top Layer w12: v1(783,411) v1@783,410.8 ; v1@785,408.8 v1@783,410.8 ; S7.6@788.1,362.4 788.1,401.9 783,407 v1@783,410.8
  Bottom Layer w12: R35.2@779.6,367.4 779.6,404.6 783,408 v1(783,411)
NetR48_2: R48.2 R55.2 U1.14 | length 220
  Top Layer w6: R48.2@944,891 949,896 v1(991,896) 991,892 v1@990,891 ; v1@991,897 1006,912 1006,936 1014.88,944.88 U1.14@1073.97,944.88
  Bottom Layer w6: R55.2@944,892 948,896 v1(991,896)
NetR50_2: R50.2 R56.2 U1.15 | length 259.1
  Top Layer w6: R50.2@944.6,817.4 974.4,817.4 v1@993,836 ; v1(993,835) v1@993,836 ; 1034,925 1023,914 1023,901 1008,886 1008,867 993,852 v1@993,836 ; 1034,925.19 U1.15@1073.97,925.19
  Bottom Layer w6: R56.2@946,818 R56.2@949,821 ; R56.2@948,822 961,835 v1(993,835)
  Bottom Layer w12: R56.2@940,820 R56.2@941,821
NetR51_2: R51.2 R57.2 U1.13 | length 181.9
  Top Layer w6: R51.2@944.6,967.4 992.6,967.4 v1(995,965) 995.44,964.56 U1.13@1073.97,964.56
  Bottom Layer w12: R57.2@944.6,967.4 992.6,967.4 v1(995,965)
NetR52_2: R52.2 R58.2 U1.32 | length 211
  Top Layer w6: R58.2@1175,540 1188.5,526.5 R52.2@1265,526.5 ; R52.2@1259.99,545.01 U1.32@1259.99,660.43
NetR54_2: R54.2 R59.2 U1.42 | length 203.7
  Top Layer w6: R59.2@1358.9,538.9 R54.2@1433.1,538.9 ; R54.2@1435,540 1456.84,561.84 U1.42@1456.84,660.43
NetS2_5: S2.5 S4.1 | length 487
  Top Layer w6: S4.1@1020.27,321.3 1023.97,325 v1(1073,325) ; v1(1416,250) 1418.4,252.4 S2.5@1470.93,252.4
  Mid-Layer 3 w6: v1(1073,325) 1115,283 1383,283 1413,253 v1@1420,253
NetS3_2: S3.2 S4.4 | length 737.1
  Top Layer w6: v1(1111,329) 1118.7,321.3 S4.4@1165.93,321.3 ; v1(1695,255) 1744,255 S3.2@1746.6,252.4 ; S3.2@1747,252 S3.2@1746.6,252.4 ; S3.2@1747.83,252.4 S3.2@1746.6,252.4
  Mid-Layer 3 w6: v1(1111,329) 1388.14,329 1412.54,304.6 1427.46,304.6 1427.86,305 1663,305 1695,273 v1@1695,256
NetU2:A_40: U2:A.40 U2:A.41 | length 118.3
  Bottom Layer w10: U2:A.41@216.38,992.36 216.38,1039.33 222.52,1045.47 229.18,1045.47 236.06,1038.59 U2:A.40@236.06,992.36
NetU2:A_62: U2:A.62 U4:A.2 | length 231
  Top Layer w10: U4:A.2@117.91,1254.84 164.2,1254.84 v2(164.99,1255.64)
  Bottom Layer w10: U2:A.62@7.72,1319.13 61.99,1319.13 125.49,1255.64 v2(164.99,1255.64)
NetU2:A_63: U2:A.63 U4:A.1 | length 227.2
  Top Layer w10: U4:A.1@117.91,1304.84 164.84,1304.84 v2(165,1305) v2@166,1306
  Bottom Layer w10: U2:A.63@7.72,1338.82 67.18,1338.82 ; 65,1341 67.18,1338.82 ; v2(165,1305) 101,1305 67.18,1338.82 ; v2@166,1306 v2@169,1303
SW_3V3: C18.1 C20.2 C21.2 R14.2 U1.80 | length 398.4
  Top Layer w10: U1.80@1535.58,1268.7 1535.58,1303.58 1556,1324 v1@1561,1324
  Top Layer w15: v1(1560,1325) 1589,1325 1590,1324 v1(1590,1325)
  Bottom Layer w10: C18.1@1543.62,1275 C18.1@1543.62,1280
  Bottom Layer w15: C18.1@1543.62,1280 1543.62,1308.62 v1(1560,1325) ; C20.2@1570,1375 1571.5,1376.5 C21.2@1571.5,1445 1649,1445 R14.2@1654,1450 ; C20.2@1575,1375 1560,1360 v1(1560,1325) ; v1(1590,1325) v1(1560,1325)
SW_GND: C18.2 C20.1 C21.1 C28.2 R15.2 U1.82 | length 318.8
  Top Layer w12: v1(1495,1325) 1495,1320 1496.21,1318.79 U1.82@1496.21,1268.7 ; v1(1540,1490) 1542.4,1492.4 C28.2@1594.48,1492.4
  Bottom Layer w12: v1(1495,1325) 1496.38,1323.62 C18.2@1496.38,1280
  Bottom Layer w15: R15.2@1415,1455 1425,1445 C21.1@1508.5,1445 ; v1(1495,1325) 1510,1340 C20.1@1510,1375 ; C21.1@1505,1450 C21.1@1510,1445
SW_GPIO-26: R5.1 S6.2 | length 443.5
  Top Layer w6: S6.2@1877.17,252.4 1928.4,252.4 v1(1929,253)
  Bottom Layer w6: v1(1929,253) 1929,277 1950,298 1950,430 1985,465 1985,560 2000,575 R5.1@2033.5,575 R5.1@2040,575
SW_GPIO-27: R6.1 S6.5 | length 342.9
  Top Layer w6: v1(1971,252) 1972.2,252 1972.6,252.4 S6.5@2022.83,252.4
  Bottom Layer w6: v1(1971,252) 1972,252 2000,280 2000,469 R6.1@2033,502 ; R6.1@2039.25,494.25 R6.1@2045,500 ; R6.1@2043.5,500 R6.1@2045,500 ; R6.1@2050,500 R6.1@2045,500
X2: C22.1 R16.1 Y1.1 | length 163.8
  Top Layer w12: Y1.1@1908.13,1027.83 1952.17,1027.83 1954,1026 v1(1954,1024)
  Bottom Layer w6: R16.1@1889.6,1007.4 1936.4,1007.4 v1@1954,1025 ; v1(1954,1024) 1989,1024 1990,1025 C22.1@1995,1020
pads on no net: EC1.4 EC1.32 EC1.37 EC1.39 EC1.40 EC1.41 EC1.42 EC1.43 EC1.44 EC1.66 EC1.88 EC1.90 EC1.91 EC1.92 EC1.93 EC1.94 EC1.95 EC1.96 EC1.104 EC1.106 EC1.108 EC1.110 EC1.113 EC1.114 EC1.115 EC1.116 EC1.117 EC1.118 EC1.119 FID1.1 FID2.1 FID3.1 FID4.1 FID5.1 FID6.1 J1:A.4 J1:A.ALIGN1 J1:A.ALIGN2 S7.8 S7.9 U1.48 U1.49 U2:A.21 U2:A.22 U2:A.23 U2:A.26 U2:A.27 U2:A.29 U2:A.30 U2:A.33 U2:A.34 U2:A.43 U2:A.44 U2:A.45 U2:A.46 U2:A.48 U2:A.52 U2:A.53 U2:A.57 U2:A.58 U2:A.59 U3:A.2 U4:A.7 U8:A.3 U8:A.5

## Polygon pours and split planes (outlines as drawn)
GND on Mid-Layer 7 "Mid-Layer 7-No Net" (solid, pour order 6): -270,799 -270,264 -257,264 -99,264 cw(c-99,243) -78,243 -78,238 -78,113 cw(c-131,113) -131,60 -132,60 -136,60 -157,66 -157,20 -143,20 0,20 cw(c0,0) 20,0 20,-216 912,-216 912,-34 cw(c974,-34) 974,28 975,28 978,28 cw(c978,-31) 1037,-31 1037,-216 2055,-216 2055,-1 cw(c2076,-1) 2076,20 2232,20 2232,66 2218,61 2207,61 2204,61 cw(c2204,106.87) 2171.57,74.43 2164,82 cw(c2190.56,108.56) 2153,108.56 2153,122 2153,241 2153,242 cw(c2175,242) 2175,264 2347,264 2347,1959 2323,1959 827,1959 827,1123 827,1119 825,1117 793,1085 813,1085 985,1085 985,1127 985,1129 985,1128 1000,1141 1126,1141 1162,1105 1192,1105 1214,1083 1214,959 1232,941 1343,941 1365,919 1365,822 1402,785 1442,785 1510,717 1510,470 1432,392 995,392 946,343 946,220 781,55 777,55 774,58 774,62 936,224 936,347 991,402 1428,402 1500,474 1500,713 1438,775 1397,775 1355,818 1355,915 1339,931 1228,931 1204,955 1204,1079 1188,1095 1158,1095 1122,1131 1004,1131 995,1123 995,1075 990,1075 783,1075 507,799
EMU_GND on Internal-Plane 2 (split plane): 726,1160.07 464.77,898.84 -269.63,898.84 -269.63,1959.01 726,1959.01
GND on Internal-Plane 2 (split plane): 257 vertices, not listed, extent -269.63,-216.18 2347.33,1959.01
EMU_GND on Internal-Plane 5 (split plane): 725.99,1160.06 464.77,898.84 -269.63,898.84 -269.63,1959.01 725.99,1959.01
GND on Internal-Plane 5 (split plane): 235 vertices, not listed, extent -269.63,-216.18 2347.33,1959.01
MCU_1V2 on Internal-Plane 6 (split plane): 1706.9,1295.72 1706.9,1271 1707.29,1269.05 1708.4,1267.4 1764.9,1210.89 1764.9,1199.23 1764.9,1188 1765.29,1186.05 1766.4,1184.4 1768.05,1183.29 1769.86,1182.93 1779.4,1173.4 1781.05,1172.29 1781.61,1172.18 1804.9,1148.89 1804.9,1097.11 1748.89,1041.1 1735,1041.1 1733.05,1040.71 1731.4,1039.6 1686.4,994.6 1685.29,992.95 1684.9,991 1684.9,814.11 1661.4,790.6 1660.29,788.95 1659.9,787 1659.9,782 1659.9,695.1 1587.11,695.1 1555.1,727.11 1555.1,740 1555.1,765 1554.71,766.95 1553.6,768.6 1525.1,797.11 1525.1,870 1524.71,871.95 1523.6,873.6 1438.6,958.6 1436.95,959.71 1435,960.1 1432.11,960.1 1370.1,1022.11 1370.1,1157.89 1392.11,1179.9 1417.89,1179.9 1459.9,1137.89 1459.9,1122 1460.29,1120.05 1461.4,1118.4 1508.4,1071.4 1510.05,1070.29 1512,1069.9 1615,1069.9 1616.95,1070.29 1618.6,1071.4 1635.6,1088.4 1636.71,1090.05 1637.1,1092 1637.1,1138 1636.71,1139.95 1635.6,1141.6 1532.6,1244.6 1530.95,1245.71 1530.39,1245.82 1503.6,1272.6 1501.95,1273.71 1500,1274.1 1350,1274.1 1348.05,1273.71 1346.4,1272.6 1328.89,1255.1 1215,1255.1 1213.05,1254.71 1211.4,1253.6 1162.89,1205.1 1120,1205.1 1118.05,1204.71 1116.4,1203.6 1106.4,1193.6 1105.29,1191.95 1104.9,1190 1104.9,1141.1 995.1,1141.1 995.1,1231.16 995.1,1364.66 1045.34,1414.9 1587.72,1414.9
EMU_1V8 on Internal-Plane 6 (split plane): 329.38,1432.46 329.38,1369.12 314.09,1353.83 294.07,1353.83 279.57,1368.33 279.57,1386.09 279.18,1388.04 278.08,1389.69 276.42,1390.8 274.63,1391.15 266.95,1398.83 265.3,1399.94 263.35,1400.32 150.09,1400.32 148.14,1399.94 146.48,1398.83 136.15,1388.5 135.05,1386.84 134.66,1384.89 134.66,1153.21 135.05,1151.26 136.15,1149.61 172.31,1113.44 173.97,1112.34 175.92,1111.95 312.1,1111.95 365.15,1058.91 365.15,1030.94 336.34,1002.13 270.23,1002.13 239.43,1032.93 239.43,1068.57 239.05,1070.52 237.94,1072.17 215.69,1094.43 214.03,1095.53 212.08,1095.92 177.72,1095.92 175.77,1095.53 174.11,1094.43 119.18,1039.49 43.31,1039.49 7.36,1075.45 7.36,1290.31 6.97,1292.26 5.86,1293.92 -14.01,1313.79 -15.66,1314.89 -17.61,1315.28 -46.5,1315.28 -83.25,1352.03 -83.25,1388.74 -76.3,1395.69 -34.7,1395.69 -32.75,1396.08 -31.1,1397.18 13.51,1441.79 320.05,1441.79
MCU_3V3 on Internal-Plane 6 (split plane): 1524.4,1237.4 1526.05,1236.29 1526.61,1236.18 1626.9,1135.89 1626.9,1094.11 1612.89,1080.1 1514.11,1080.1 1470.1,1124.11 1470.1,1140 1469.71,1141.95 1468.6,1143.6 1423.6,1188.6 1421.95,1189.71 1420,1190.1 1390,1190.1 1388.05,1189.71 1386.4,1188.6 1361.4,1163.6 1360.29,1161.95 1359.9,1160 1359.9,1020 1360.29,1018.05 1361.4,1016.4 1426.4,951.4 1428.05,950.29 1430,949.9 1432.89,949.9 1514.9,867.89 1514.9,795 1515.29,793.05 1516.4,791.4 1544.9,762.89 1544.9,740 1544.9,725 1545.29,723.05 1546.4,721.4 1579.9,687.89 1579.9,665 1579.9,645 1579.9,635 1580.29,633.05 1581.4,631.4 1604.9,607.89 1604.9,580 1604.9,520.1 1510.1,520.1 1510.1,715 1509.71,716.95 1508.6,718.6 1443.6,783.6 1441.95,784.71 1440,785.1 1402.11,785.1 1365.1,822.11 1365.1,917 1364.71,918.95 1363.6,920.6 1344.6,939.6 1342.95,940.71 1341,941.1 1232.11,941.1 1214.1,959.11 1214.1,1081 1213.71,1082.95 1212.6,1084.6 1193.6,1103.6 1191.95,1104.71 1190,1105.1 1162.11,1105.1 1129.6,1137.6 1127.6,1139.6 1125.95,1140.71 1124,1141.1 1115.1,1141.1 1115.1,1187.89 1122.11,1194.9 1165,1194.9 1166.95,1195.29 1168.6,1196.4 1217.11,1244.9 1331,1244.9 1332.95,1245.29 1334.6,1246.4 1352.11,1263.9 1497.89,1263.9
MCU_A_3V3 on Internal-Plane 6 (split plane): 1122.4,1130.4 1156.4,1096.4 1158.05,1095.29 1160,1094.9 1187.89,1094.9 1203.9,1078.89 1203.9,957 1204.29,955.05 1205.4,953.4 1226.4,932.4 1228.05,931.29 1230,930.9 1338.89,930.9 1354.9,914.89 1354.9,820 1355.29,818.05 1356.4,816.4 1396.4,776.4 1398.05,775.29 1400,774.9 1437.89,774.9 1499.9,712.89 1499.9,227.11 1467.89,195.1 910,195.1 908.05,194.71 906.4,193.6 617.89,-94.9 238.11,-94.9 166.1,-22.89 166.1,309 165.71,310.95 164.6,312.6 93.6,383.6 91.95,384.71 90,385.1 -32.89,385.1 -49.9,402.11 -49.9,512.89 -27.89,534.9 0,534.9 1.95,535.29 3.6,536.4 13.6,546.4 14.71,548.05 15.1,550 15.1,667.89 92.11,744.9 540,744.9 541.95,745.29 543.6,746.4 872.11,1074.9 990,1074.9 991.95,1075.29 993.6,1076.4 994.71,1078.05 995.1,1080 995.1,1128.98 995.9,1130.9 1121.89,1130.9
3V3 on Internal-Plane 6 (split plane): 2347.33,895.1 2147.11,895.1 2128.6,913.6 2126.95,914.71 2125,915.1 2060,915.1 2058.05,914.71 2056.4,913.6 2016.4,873.6 2015.29,871.95 2014.9,870 2014.9,790 2015.29,788.05 2016.4,786.4 2054.9,747.89 2054.9,640 2054.9,202.11 1957.89,105.1 832.31,105.1 912.11,184.9 1470,184.9 1471.95,185.29 1473.6,186.4 1508.6,221.4 1509.71,223.05 1510.1,225 1510.1,509.9 1610,509.9 1611.95,510.29 1613.6,511.4 1614.71,513.05 1615.1,515 1615.1,580 1615.1,610 1614.71,611.95 1613.6,613.6 1590.1,637.11 1590.1,645 1590.1,684.9 1665,684.9 1666.95,685.29 1668.6,686.4 1669.71,688.05 1670.1,690 1670.1,782 1670.1,784.89 1693.6,808.4 1694.71,810.05 1695.1,812 1695.1,988.89 1737.11,1030.9 1751,1030.9 1752.95,1031.29 1754.6,1032.4 1813.6,1091.4 1814.71,1093.05 1815.1,1095 1815.1,1151 1814.71,1152.95 1813.6,1154.6 1787.6,1180.6 1785.95,1181.71 1785.39,1181.82 1775.6,1191.6 1775.1,1191.94 1775.1,1199.23 1775.1,1213 1774.71,1214.95 1773.6,1216.6 1717.1,1273.11 1717.1,1297.83 1716.71,1299.78 1715.6,1301.44 1593.44,1423.6 1591.78,1424.71 1589.83,1425.1 1043.23,1425.1 1041.27,1424.71 1039.62,1423.6 986.4,1370.38 985.29,1368.73 984.9,1366.77 984.9,1231.16 984.9,1130 984.9,1085.1 870,1085.1 868.05,1084.71 866.4,1083.6 537.89,755.1 90,755.1 88.05,754.71 86.4,753.6 6.4,673.6 5.29,671.95 4.9,670 4.9,552.11 -2.11,545.1 -30,545.1 -31.95,544.71 -33.6,543.6 -58.6,518.6 -59.71,516.95 -60.1,515 -60.1,400 -59.71,398.05 -58.6,396.4 -38.6,376.4 -36.95,375.29 -35,374.9 87.89,374.9 155.9,306.89 155.9,205.1 67.11,205.1 -61.4,333.6 -63.05,334.71 -65,335.1 -97.89,335.1 -149.9,387.11 -149.9,593.11 -121.26,626.53 -26.4,721.4 -25.29,723.05 -24.9,725 -24.9,798.84 506.2,798.84 825.99,1118.64 825.99,1959.01 2347.33,1959.01
EMU_3V3 on Internal-Plane 6 (split plane): 725.99,1160.06 464.77,898.84 -269.63,898.84 -269.63,1959.01 725.99,1959.01
HSEC_5V0 on Internal-Plane 6 (split plane): 187 vertices, not listed, extent -269.63,-216.18 2347.33,904.9
EMU_GND on Internal-Plane 9 (split plane): 726.08,1160.16 464.87,898.94 -269.63,898.94 -269.63,1959.01 726.08,1959.01
GND on Internal-Plane 9 (split plane): 233 vertices, not listed, extent -269.63,-216.18 2347.33,1959.01

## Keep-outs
Keep-Out Layer:
  text ".Layer_Name" at -3604.9,-2856.09 h60

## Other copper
Top Layer:
  region net MCU_A_3V3: 894,1021 965,1021 971,1015 991,1015 998,1021 999,1064 994,1069 894,1069
  region net 3V3: 894,1101 956,1101 956,1165 964,1173 964,1193 962,1195 902,1195 894,1187
  region net 3V3: 1651,494 1699,494 1699,573 1705,579 1705,599 1698,606 1668,606 1651,589
  region net MCU_3V3: 1619,556 1619,495 1618,494 1536,494 1513,513 1513,556 1521,564 1550,564 1558,556
  region net HSEC_5V0: 2047,777 2089,777 2141,777 2157,793 2157,807 2157,872 2150,879 2147,882 2122,882 2118,878 2118,856 2122,852 2122,802 2120,800 2070,800 2068,802 2068,852 2072,856 2072,880 2068,884 2049,884 2045,880 2045,854 2047,852
  region net NetC27_2: 1940,906 2039,906 2049,916 2068,916 2068,951 2066,953 1940,953 1939,952 1939,907
  region net 3V3: 2001,874 2001,806 1988,793 1904,793 1893,804 1893,872 1900,879 1917,879 1923,874
  region net MCU_GPIO-22: 1270,1415 1306,1415 1306,1455 1334,1455 1336,1453 1337,1453 1366,1453 1366,1507 1273,1507 1270,1504
  region net SW_3V3: 1531,1306 1539,1314 1539,1333 1544,1338 1600,1338 1605,1333 1605,1314 1598,1307 1546,1307 1540,1301 1541,1300 1541,1246 1530,1246 1530,1293 1531,1294
  region net NetL3_1: 1414,1507 1481,1507 1532,1456 1542,1456 1542,1417 1507,1417 1507,1423 1414,1423
  region net SW_GND: 1490,1309 1477,1322 1477,1336 1487,1346 1502,1346 1508,1340 1508,1320 1502,1311 1502,1248 1490,1248
  region net MCU_1V2: 1225,1355 1229,1351 1378,1351 1378,1387 1378,1388 1228,1388 1225,1385
  text ".Layer_Name" at -3604.9,-2856.09 h60
Mid-Layer 3:
  text ".Layer_Name" at -3619,-2847 h60
Mid-Layer 4:
  text ".Layer_Name" at -3600,-2847 h60
Mid-Layer 7:
  text ".Layer_Name" at -3595,-2852 h60
Mid-Layer 8:
  text ".Layer_Name" at -3600,-2846 h60
Bottom Layer:
  region net SW_3V3: 1685,1474 1602,1474 1591,1463 1552,1463 1552,1434 1554,1432 1554,1339 1537,1322 1537,1311 1541,1307 1595,1307 1603,1315 1603,1345 1591,1357 1591,1427 1621,1427 1623,1425 1685,1425
  region net SW_GND: 1389,1480 1474,1480 1519,1503 1553,1503 1553,1482 1527,1464 1528,1463 1528,1332 1528,1323 1514,1309 1511,1309 1488,1309 1480,1317 1480,1346 1491,1357 1491,1430 1389,1430
  region net GND: 1451,1511 1451,1559 1346,1559 1337,1550 1337,1522 1348,1511
  region net 3V3: 1624,1506 1686,1506 1686,1555 1702,1571 1702,1593 1697,1598 1633,1598 1624,1589 1624,1508
  text ".Layer_Name" at -3604.9,-2856.09 h60
Internal-Plane 2 (plane layer: these items are gaps in the copper):
  region: 506.19,798.84 825.99,1118.64 755.28,1189.35 435.48,869.55
  rectangle: 726,1119 826,1977
  rectangle: -293.8,798.84 506.2,898.84
  lines w10: 697.45,1007.09 697.45,1017.86 ; 776,1080 990,1080 990,1092.75 990,1118.25 990,1119.44 990,1125.81 1002.16,1136 1040,1136 1124,1136 1160,1100 1190,1100 1209,1081 1209,957 1230,936 1341,936 1360,917 1360,820 1400,780 1420,780 1440,780 1505,715 1505,472 1430,397 993,397 941,345 941,222 799,80 779,60 ; 776.47,1115.01 783.39,1121.93
  text ".Layer_Name" at -3619,-2838 h60
Internal-Plane 9 (plane layer: these items are gaps in the copper):
  rectangle: 726.08,1118.73 826.08,1976.73
  rectangle: -293.71,798.94 506.29,898.94
  region: 506.29,798.94 826.08,1118.73 755.37,1189.44 435.58,869.65
  lines w10: 760,1080 975,1080 990,1080 990,1125 1001,1136 1074,1136 1124,1136 1160,1100 1190,1100 1209,1081 1209,957 1230,936 1341,936 1360,917 1360,820 1400,780 1440,780 1505,715 1505,472 1430,397 993,397 941,345 941,222 779,60
  text ".Layer_Name" at -3603,-2855 h60
Internal-Plane 6 (plane layer: these items are gaps in the copper):
  rectangle: -293.8,798.84 506.2,898.84
  region: 506.19,798.84 825.99,1118.64 755.28,1189.35 435.48,869.55
  rectangle: 725.99,1118.64 825.99,1976.64
  lines w10: -30,800 -30,725 -125,630 -155,595 -155,385 -100,330 -91.25,330 -73.75,330 -65,330 65,200 160,200 ; 820,100 1960,100 2060,200 2060,640 2060,750 2020,790 2020,870 2060,910 2125,910 2145,890 2370,890 ; 1110,1136 1110,1190 1120,1200 1165,1200 1215,1250 1331,1250 1350,1269 1500,1269 1528,1241 1529,1241 1632,1138 1632,1092 1615,1075 1512,1075 1465,1122 1465,1140 1420,1185 1390,1185 1365,1160 1365,1020 1430,955 1435,955 1520,870 1520,795 1550,765 1550,740 1550,725 1585,690 ; 1505,515 1610,515 1610,580 1610,610 1585,635 ; 1585,645 1585,635 ; 1585,665 1585,690 ; 990,1130 992.5,1136 1027.5,1136 1124,1136 1126,1134 1160,1100 1190,1100 1209,1081 1209,957 1230,936 1341,936 1360,917 1360,820 1400,780 1440,780 1505,715 1505,225 1470,190 910,190 620,-100 236,-100 161,-25 161,309 90,380 -10,380 -35,380 -55,400 -55,515 -30,540 0,540 10,550 10,670 90,750 540,750 870,1080 900,1080 990,1080 990,1130 ; 990,1130 990,1231.16 990,1366.77 1043.23,1420 1589.83,1420 1712,1297.83 1712,1271 1770,1213 1770,1199.23 1770,1188 1772,1188 1783,1177 1784,1177 1810,1151 1810,1095 1751,1036 1735,1036 1690,991 1690,812 1665,787 1665,782 1665,690 1585,690 ; 1585,635 1585,690 ; -88.35,1349.92 -48.61,1310.18 -17.61,1310.18 2.26,1290.31 2.26,1073.34 41.2,1034.39 121.29,1034.39 177.72,1090.82 212.08,1090.82 234.34,1068.57 234.34,1030.81 268.11,997.04 338.45,997.04 370.24,1028.83 370.24,1061.02 314.21,1117.05 175.92,1117.05 139.76,1153.21 139.76,1384.89 150.09,1395.23 263.35,1395.23 272.49,1386.09 274.47,1386.09 274.47,1366.22 291.96,1348.73 316.2,1348.73 334.48,1367.01 334.48,1434.57 322.16,1446.89 11.4,1446.89 -34.7,1400.79 -78.41,1400.79 -88.35,1390.85 -88.35,1349.92
  text ".Layer_Name" at -3581,-2857 h60
Internal-Plane 5 (plane layer: these items are gaps in the copper):
  rectangle: -293.8,798.84 506.2,898.84
  region: 506.19,798.84 825.99,1118.64 755.28,1189.35 435.48,869.55
  rectangle: 725.99,1118.64 825.99,1976.64
  lines w10: 727,1080 990,1080 990,1126 1000,1136 1124,1136 1160,1100 1190,1100 1209,1081 1209,957 1230,936 1341,936 1360,917 1360,820 1400,780 1440,780 1505,715 1505,472 1430,397 1023,397 993,397 941,345 941,222 779,60
  text ".Layer_Name" at -3576,-2852 h60

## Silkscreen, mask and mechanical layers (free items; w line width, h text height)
Top Overlay:
  region: 2292.34,1969.69 2292.34,1825 2357,1825 2357,1969.69
  lines w4: -45,255 -25,275
  text "ON" at 1140.99,1898 h20
  text "1" at 1946,1898 h20
  text "-" at 2344,1763 h40 r90
  text "BOOT" at 1983,1724 h20 r90
  text ".PCB_Rev" at 2342,1691 h40 r90
  text "JTAG ISO" at 1152,1683 h20 r90
  text "UART ISO" at 1363,1683 h20 r90
  text "OFF" at 1121,1602 h20
  text "0" at 1941,1601 h20
  text "OutFilt" at 818,703 h20
  text "C2000 F28004x controlCARD" at 2346,665 h40 r90
  text "PGA" at 979,486 h20 r90
  text "cJTAG" at 1049,388 h20
  text "Thru" at 861.32,297 h20
  text "Int" at 479,119 h20
  text "Ext" at 809,119 h20
  text "VREFHI" at 576,93 h20
  text "Std JTAG" at 1025,75 h20
  text "1" at 46.06,6.81 h30
  text "57" at 1038.19,6.81 h30
  text "119" at 1955.51,6.81 h30
  text "55" at 870,-5 h30
  text ".Layer_Name" at -3604.9,-2856.09 h60
Bottom Overlay:
  text "TMDSCNCD280049C" at 1892,111 h40
  text "'.PCB_Rev'" at 1648,48 h40
  text ".PRJ_Number" at 1891,48 h40
  text "2" at 57.87,6.81 h30
  text "58" at 1089.37,6.81 h30
  text "120" at 2022.44,6.81 h30
  text "56" at 915,-5 h30
  text ".Layer_Name" at -3604.9,-2856.09 h60
Top Paste:
  text ".Layer_Name" at -3604.9,-2856.09 h60
Bottom Paste:
  text ".Layer_Name" at -3604.9,-2856.09 h60
Top Solder:
  text ".Layer_Name" at -3604.9,-2856.09 h60
  text ".Layer_Name" at -3604.9,-2856.09 h60
Bottom Solder:
  text ".Layer_Name" at -3604.9,-2856.09 h60
Drill Guide:
  text ".Layer_Name" at -3604.9,-2856.09 h60
M1 Board Outline:
  lines w4: -284.78,1474.65 -284.78,248.72 -284.76,248.7 -93.62,248.7 -93.75,248.57 -93.75,115.24 -93.68,115.18 ; -284.78,1947.09 -284.68,1947.19 -284.68,1973.99 -284.57,1974.1 2362.36,1974.1 2362.36,249.2 2168.79,249.2 2168.46,248.86 2168.46,116.77 ccw(c2207.41,114.86) 2230.94,83.76 2247.19,83.76 2247.24,83.8 2247.24,4.91 ; -93.34,115.83 cw(c-132.3,113.92) -155.82,82.82 -172.1,82.82 -172.14,82.78 -172.14,4.89 -172.08,4.95 5.05,4.95 5.11,4.89 5.11,-231.04 5.17,-230.98 927.3,-230.98 927.3,-34.43 ; 1022.44,-34.43 1022.44,-231.33 1022.51,-231.27 2070.19,-231.27 2070.19,4.83 2070.27,4.91 2247.24,4.91 ; 2247.24,4.91 2247.24,4.91
  text ".Layer_Name" at -3593,-2846 h60
M2 Board Dimensions:
  rectangle: -4181.9,-2272.6 -4056.9,-2147.6
  rectangle: -4056.9,-2397.6 -3681.9,-2272.6
  lines w7: -4181.9,-2272.6 -3181.9,-2272.6 ; -4056.9,-2397.6 -4056.9,-2147.6 ; -3931.9,-2397.6 -3931.9,-2147.6 ; -3681.9,-2397.6 -3681.9,-2147.6 ; -3431.9,-2397.6 -3431.9,-2147.6 ; -4181.9,-2397.6 -3181.9,-2397.6 -3181.9,-2147.6 -4181.9,-2147.6 -4181.9,-2397.6
  lines w10: -3200,-522 -3132,-522 ; -3158,-551 -3131,-523 ; -3158,-492 -3131,-522 ; -3124,823 -3056,905 ; -3122,-569 -3122,-247 ; -3122,-206 -3072,-260 -2962,-260 -2915,-203 ; -3122,-204 -3122,826 ; -3057,906 -2993,819 ; -3039,-354 -2971,-354 ; -2997,-383 -2970,-355 ; -2997,-324 -2970,-354 ; -2992,818 -2920,908 ; -2961,-569 -2961,-287 ; -2915,-204 -2915,826 -2915,911 ; -2914,-569 -2914,-247 ; -2908.04,446.62 cw(c-2964,-261) -2524.66,296.54 ; -2906.16,445.26 ccw(c-2766.4,679.92) -2855.29,421.66 ; -2906,-519 -2879,-549 ; -2906,-518 -2879,-490 ; -2906,452 cw(c-2873.55,278.02) -2843.28,452.39 ; -2904,-518 -2836,-518 ; -2904,-355 -2877,-385 ; -2904,-354 -2877,-326 ; -2902,-354 -2834,-354 ; -2888,-165 -2425,407 ; -2578,311 ccw(c-2440.48,651.43) -2523.34,293.74 ; -2560.75,344.3 cw(c-2677.61,210.86) -2522,296
  text "30" at -2719,467 h60
  text "18MIL" at -2793,-382 h60
  text "62MIL" at -2800,-546 h60
  text "GOLD FINGER" at -3281,-783 h60
  text "SIDE VIEW" at -3227,-896 h60
  text ".Layer_Name" at -3604.9,-2856.09 h60
M3 3D STEP Top:
  text ".Layer_Name" at -3604.9,-2856.09 h60
M4 3D STEP Bottom:
  text ".Layer_Name" at -3604.9,-2856.09 h60
M5 Assembly Top:
  lines w10: -4473.9,-2927.77 2126.1,-2927.77 ; -4473.9,-2724.43 2128.1,-2724.43 ; -4473.9,-2521.1 -4473.9,-3131.1 -468.9,-3131.1 2128.1,-3131.1 2128.1,-2521.1 -4473.4,-2521.1 -4473.4,-3131.1 -2897.9,-3131.1 ; -2008.9,-3131.1 -2008.9,-2521.1 ; -741.9,-2724.43 -741.9,-2521.1 ; 98.1,-2724.43 98.1,-2521.1 ; 720.1,-3137.6 720.1,-2934.77
  text "COMPONENTS MARKED 'DNP' SHOULD NOT BE POPULATED." at -3028.4,-2316.1 h60
  text "ASSEMBLY VARIANT:" at -3028.9,-2431.6 h60
  text ".VariantName" at -1992.9,-2431.6 h60
  text "PCB VIEWED FROM TOP SIDE" at -4410.4,-2653.27 h60
  text "BOARD #:" at -1933.9,-2653.27 h60
  text ".PRJ_Number" at -1388.4,-2653.27 h60
  text "REV:" at -543.9,-2653.27 h60
  text ".PCB_Rev" at -252.4,-2653.27 h60
  text "SVN REV:" at 294.1,-2653.27 h60
  text ".VersionControl_RevNumber" at 800.1,-2653.27 h60
  text "TID #:" at -1933.9,-2856.6 h60
  text ".TID" at -1388.4,-2856.6 h60
  text "PLOT NAME =" at -4410.4,-3061.94 h60
  text ".plot_File_Name" at -3604.9,-3061.94 h60
  text "GENERATED    :" at -1931.9,-3061.94 h60
  text ".Print_Date" at -1062.4,-3061.94 h60
  text ".Print_Time" at -333.4,-3061.94 h60
  text "TEXAS INSTRUMENTS" at 931.1,-3061.94 h60
M6 Assembly Bottom:
  lines w10: -4474.4,-2724.93 2127.6,-2724.93 ; -4472.4,-2928.27 2127.6,-2928.27 ; -3066.4,-3138.1 -3066.4,-2935.27 ; -2444.4,-2724.93 -2444.4,-2521.6 ; -1604.4,-2724.93 -1604.4,-2521.6 ; -337.4,-3131.6 -337.4,-2521.6 ; 551.6,-3131.6 2127.1,-3131.6 2127.1,-2521.6 -4474.4,-2521.6 -4474.4,-3131.6 -1877.4,-3131.6 2127.6,-3131.6 2127.6,-2521.6
  text "COMPONENTS MARKED 'DNP' SHOULD NOT BE POPULATED." at 1920.1,-2315.6 h60
  text ".VariantName" at 876.1,-2431.6 h60
  text "ASSEMBLY VARIANT:" at 1915.1,-2431.6 h60
  text ".VersionControl_RevNumber" at -3146.4,-2653.77 h60
  text "SVN REV:" at -2640.4,-2653.77 h60
  text ".PCB_Rev" at -2093.9,-2653.77 h60
  text "REV:" at -1802.4,-2653.77 h60
  text ".PRJ_Number" at -957.9,-2653.77 h60
  text "BOARD #:" at -412.4,-2653.77 h60
  text "PCB VIEWED FROM BOTTOM SIDE" at 2064.1,-2653.77 h60
  text ".TID" at -957.9,-2857.1 h60
  text "TID #:" at -412.4,-2857.1 h60
  text "TEXAS INSTRUMENTS" at -3277.4,-3062.44 h60
  text ".Print_Time" at -2012.9,-3062.44 h60
  text ".Print_Date" at -1283.9,-3062.44 h60
  text "GENERATED    :" at -414.4,-3062.44 h60
  text ".plot_File_Name" at 1258.6,-3062.44 h60
  text "PLOT NAME =" at 2064.1,-3062.44 h60
M9 Title Sheet:
  drawing of 100 lines, arcs and shapes, not listed
  text "1" at -3442.06,6038.9 h70
  text "2" at -946.4,6038.9 h70
  text "3" at 1542.94,6038.9 h70
  text "4" at 4049.61,6038.9 h70
  text "5" at 6548.6,6038.9 h70
  text "6" at 9053.6,6038.9 h70
  text "A" at -4598.4,4895.9 h70
  text "A" at 10201.6,4895.9 h70
  text "B" at -4598.4,2515.9 h70
  text "B" at 10201.6,2515.9 h70
  text "C" at -4598.4,140.9 h70
  text "C" at 10201.6,140.9 h70
  text "PROJECT TITLE:" at 7161.6,-1720.1 h45
  text ".PRJ_Title" at 7211.6,-1853.43 h70
  text "DESIGNED FOR:" at 7161.6,-2021.1 h45
  text ".PRJ_Customer" at 7211.6,-2161.1 h70
  text "D" at -4598.4,-2229.1 h70
  text "D" at 10201.6,-2229.1 h70
  text "FILE NAME:" at 7161.6,-2321.1 h45
  text ".PCB_File_Name_No_Path" at 7211.6,-2441.1 h70
  text "Texas Instruments (TI) and/or its licensors do not warrant the accuracy or completeness of this specification" at 2192.1,-2602.94 h45
  text "ENGINEER:" at 7161.6,-2611.1 h45
  text "LAYOUT BY:" at 8666.6,-2611.1 h45
  text "or any information contained therein. TI and/or its licensors do not warrant that this design will meet" at 2147.11,-2715.6 h45
  text ".PRJ_Engineer" at 7211.6,-2766.09 h70
  text "QC Graphics Inc." at 8717.1,-2766.09 h70
  text "the specifications, will be suitable for your application or fit for any particular purpose, or will operate in" at 2147.11,-2828.27 h45
  text ".Layer_Name" at -3604.9,-2856.09 h60
  text "ALTIUM DESIGNER VERSION:" at 8666.6,-2921.1 h45
  text "an implementation. TI and/or its licensors do not warrant that the design is production worthy. You should" at 2147.11,-2940.93 h45
  text "completely validate and test your design implementation to confirm the system functionality for your application." at 2192.1,-3053.6 h45
  text ".print_Scale" at 7211.6,-3054.43 h70
  text ".Application_BuildNumber" at 8717.1,-3054.43 h70
  text "1" at -3442.06,-3261.1 h70
  text "2" at -946.4,-3261.1 h70
  text "3" at 1542.94,-3261.1 h70
  text "4" at 4049.61,-3261.1 h70
  text "5" at 6548.6,-3261.1 h70
  text "6" at 9053.6,-3261.1 h70
M10 Fab Notes:
  drawing of 173 lines, arcs and shapes, not listed
  text "DESIGN INFORMATION" at 8196.12,4203.4 h60
  text "MIN. TRACK WIDTH:" at 7551.56,4023.4 h60
  text "5" at 8647.8,4023.4 h60
  text "MIL" at 8802.56,4023.4 h60
  text "MIN. CLEARANCE:" at 7551.56,3891.4 h60
  text "0.1" at 8587.8,3891.4 h60
  text "mm" at 8802.56,3891.4 h60
  text "MIN. VIA PAD SIZE:" at 7551.56,3759.4 h60
  text "22" at 8617.81,3759.4 h60
  text "MIL" at 8802.56,3759.4 h60
  text "0.05mm (2MIL)" at 8246.56,3617.69 h60
  text "MINIMUM ANNULAR RING" at 7222.33,3613.4 h60
  text "EXTERNAL" at 8954.56,3613.4 h60
  text "PER" at 7422.33,3495.4 h60
  text "IPC-D-275 CLASS 2 LEVEL C" at 7642.33,3495.4 h60
  text "MIL, HOLES" at 9130.56,3383.11 h60
  text "+/-" at 8738.1,3382.4 h60
  text "+/-" at 9592.1,3382.4 h60
  text "REGISTRATION TOLERANCES:" at 7222.33,3377.4 h60
  text "METAL" at 8422.1,3377.4 h60
  text "5" at 8998.3,3377.4 h60
  text "3" at 9831.3,3377.4 h60
  text "MIL" at 9947.56,3377.4 h60
  text "+/-" at 9592.1,3264.4 h60
  text "HOLE SIZE TOLERANCE (UNLESS OTHERWISE SPECIFIED):" at 7222.33,3259.4 h60
  text "3" at 9831.3,3259.4 h60
  text "MIL" at 9947.56,3259.4 h60
  text "MATERIAL:" at 7147.56,3049.94 h60
  text "FR-4 High Tg" at 8134,2909.61 h60
  text "FR-408" at 7568.56,2901.04 h60
  text "OTHER" at 9056.56,2901.04 h60
  text "X" at 7979.1,2897.4 h60
  text "THICKNESS:" at 7222.33,2734.04 h60
  text "X" at 7760.5,2734.04 h60
  text "OTHER" at 9243.6,2734.47 h60
  text "62 MIL (1.6mm) +/- 6MIL" at 7896.21,2732.66 h60
  text "TOLERANCE:" at 7222.33,2576.04 h60
  text "X" at 8061.63,2576.04 h60
  text "ANSI IPC-6012 TYPE 3 CLASS 2" at 8248.58,2576.04 h60
  text "OTHER +/-" at 8248.56,2420.04 h60
  text "BOW & TWIST:" at 7222.33,2263.04 h60
  text "X" at 8061.63,2263.04 h60
  text "ANSI IPC-6012 TYPE 3 CLASS 2" at 8248.58,2263.04 h60
  text "OTHER +/-" at 8248.56,2104.53 h60
  text "DRILLING:" at 7147.56,1966.04 h60
  text "REFERENCE:" at 7222.33,1849.04 h60
  text "X" at 7870.56,1849.04 h60
  text "AS SHOWN" at 8057.56,1849.04 h60
  text "X" at 8771.56,1849.04 h60
  text "NC_DRILL FILES" at 8908.56,1849.04 h60
  text "PTH COPPER THICKNESS:" at 7222.33,1691.04 h60
  text "X" at 8352.56,1691.04 h60
  text "20-30 um" at 8489.56,1691.04 h60
  text "OTHER" at 9206.56,1691.04 h60
  text "BOARD FINISH:" at 7147.56,1532.04 h60
  text "SILKSCREEN:" at 7302.78,1414.04 h60
  text "X" at 8251.56,1414.04 h60
  text "TOP" at 8377.56,1414.04 h60
  text "X" at 8761.56,1414.04 h60
  text "BOTTOM" at 8888.56,1414.04 h60
  text "SILKSCREEN COLOR:" at 7302.78,1247.04 h60
  text "X" at 8250.52,1247.04 h60
  text "WHITE" at 8377.56,1247.04 h60
  text "OTHER" at 8888.56,1247.04 h60
  text "X" at 8381.52,1087.84 h60
  text "GREEN" at 8508.56,1087.84 h60
  text "OTHER" at 9126.56,1087.84 h60
  text "SOLDER RESIST COLOR:" at 7302.78,1077.04 h60
  text "X" at 8381.52,917.84 h60
  text "MATTE" at 8508.56,917.84 h60
  text "SEMI-GLOSS" at 9126.1,917.2 h60
  text "IMMERSION GOLD (ENIG)" at 8208.56,729.32 h60
  text "ENEPIG" at 9546.1,726.04 h60
  text "SURFACE FINISH:" at 7147.56,725.04 h60
  text "X" at 8021.61,725.04 h60
  text "HARD GOLD FINGERS" at 9228,570 h60
  text "IMM. TIN/SILVER OR EQUIV" at 7477.1,568.04 h60
  text "OTHER" at 8908.56,568.04 h60
  text "X" at 8715.61,552.04 h60
  text "ARRAY/PANEL:" at 7147.56,389.04 h60
  text "CUT AND TRIM PER M1 BOARD OUTLINE" at 8208.56,384.75 h60
  text "N.C. ROUTE" at 8208.56,233.04 h60
  text "X" at 8887.56,233.04 h60
  text "V. SCORE" at 9074.56,233.04 h60
  text "CERTIFICATION:" at 7147.56,96.04 h60
  text "MATERIALS AND WORKMANSHIP FOR ALL PCBS" at 7872.56,96.04 h60
  text "TO MEET OR EXCEED THE REQUIREMENTS OF:" at 7872.56,-1.96 h60
  text "X" at 7499.06,-138.47 h60
  text "ANSI IPC-A-600F CLASS ->" at 7638.06,-138.47 h60
  text "X" at 9277.12,-138.47 h60
  text "2" at 9396.06,-138.46 h60
  text "1" at 9081.06,-139.96 h60
  text "3" at 9750.06,-139.96 h60
  text "X" at 8313.12,-297.96 h60
  text "RoHS" at 8450.06,-297.96 h60
  text "OTHER" at 9094.46,-297.96 h60
  text "PER ORDER" at 9491.52,-297.96 h60
  text "ALL BOARDS MUST MEET OR EXCEED UL94-V0 REQUIREMENTS." at 7175.1,-463.6 h60
  text "PCB MUST BEAR THE UL94V-0 UL REGISTERED MATERIAL ID NUMBER" at 7175.1,-583.6 h60
  text "ADDITIONAL REQUIREMENTS:" at 7147.56,-756.96 h60
  text "MICROSECTION:" at 7222.33,-871.96 h60
  text "YES" at 8128.06,-871.96 h60
  text "REQUIRED" at 8989.56,-1028.11 h60
  text "BARE BOARD ELEC. TEST:" at 7222.33,-1030.96 h60
  text "NONE" at 8528.06,-1030.96 h60
  text "X" at 8862.56,-1030.96 h60
  text "PER ORDER" at 9581.56,-1030.96 h60
  text ".Layer_Name" at -3604.9,-2856.09 h60
M11 Gerber Information:
  lines w10: -4473.9,-2927.77 2126.1,-2927.77 ; -4473.9,-2724.43 2128.1,-2724.43 ; -4473.9,-2521.1 -4473.9,-3131.1 -468.9,-3131.1 2128.1,-3131.1 2128.1,-2521.1 -4473.4,-2521.1 -4473.4,-3131.1 -2897.9,-3131.1 ; -2008.9,-3131.1 -2008.9,-2521.1 ; -741.9,-2724.43 -741.9,-2521.1 ; 98.1,-2724.43 98.1,-2521.1 ; 720.1,-3137.6 720.1,-2934.77
  text "ALL ARTWORK VIEWED FROM TOP SIDE" at -4410.4,-2653.27 h60
  text "BOARD #:" at -1933.9,-2653.27 h60
  text ".PRJ_Number" at -1388.4,-2653.27 h60
  text "REV:" at -543.9,-2653.27 h60
  text ".PCB_Rev" at -252.4,-2653.27 h60
  text "SVN REV:" at 294.1,-2653.27 h60
  text ".VersionControl_RevNumber" at 800.1,-2653.27 h60
  text "LAYER NAME =" at -4410.4,-2856.09 h60
  text "TID #:" at -1933.9,-2856.6 h60
  text ".TID" at -1388.4,-2856.6 h60
  text "PLOT NAME =" at -4410.4,-3061.94 h60
  text ".plot_File_Name" at -3604.9,-3061.94 h60
  text "GENERATED    :" at -1931.9,-3061.94 h60
  text ".Print_Date" at -1062.4,-3061.94 h60
  text ".Print_Time" at -333.4,-3061.94 h60
  text "TEXAS INSTRUMENTS" at 931.1,-3061.94 h60
M12 Stackup:
  drawing of 607 lines, arcs and shapes, not listed
  text "Layer" at 2306.38,5808.5 h60
  text "Name" at 2716.29,5808.5 h60
  text "Material" at 3756,5808.5 h60
  text "Thickness" at 4615.77,5808.5 h60
  text "Constant" at 5265.6,5808.5 h60
  text "Board Layer Stack" at 5835.46,5808.5 h60
  text "1" at 2306.38,5688.5 h60
  text "Top Overlay" at 2716.29,5688.5 h60
  text "2" at 2306.38,5568.5 h60
  text "Top Solder" at 2716.29,5568.5 h60
  text "Solder Resist" at 3756,5568.5 h60
  text "0.50mil" at 4615.77,5568.5 h60
  text "3.5" at 5265.6,5568.5 h60
  text "3" at 2306.38,5448.5 h60
  text "Top Layer" at 2716.29,5448.5 h60
  text "Copper" at 3756,5448.5 h60
  text "1.40mil" at 4615.77,5448.5 h60
  text "4" at 2306.38,5328.5 h60
  text "Dielectric1" at 2716.29,5328.5 h60
  text "FR-4" at 3756,5328.5 h60
  text "5.20mil" at 4615.77,5328.5 h60
  text "4.8" at 5265.6,5328.5 h60
  text "5" at 2306.38,5208.5 h60
  text "Internal-Plane 2" at 2716.29,5208.5 h60
  text "Copper" at 3756,5208.5 h60
  text "1.40mil" at 4615.77,5208.5 h60
  text "6" at 2306.38,5088.5 h60
  text "Dielectric6" at 2716.29,5088.5 h60
  text "FR-4" at 3756,5088.5 h60
  text "5.20mil" at 4615.77,5088.5 h60
  text "4.8" at 5265.6,5088.5 h60
  text "7" at 2306.38,4968.5 h60
  text "Mid-Layer 3" at 2716.29,4968.5 h60
  text "Copper" at 3756,4968.5 h60
  text "1.40mil" at 4615.77,4968.5 h60
  text "8" at 2306.38,4848.5 h60
  text "Dielectric2" at 2716.29,4848.5 h60
  text "FR-4" at 3756,4848.5 h60
  text "5.20mil" at 4615.77,4848.5 h60
  text "4.8" at 5265.6,4848.5 h60
  text "9" at 2306.38,4728.5 h60
  text "Mid-Layer 4" at 2716.29,4728.5 h60
  text "Copper" at 3756,4728.5 h60
  text "1.40mil" at 4615.77,4728.5 h60
  text "10" at 2306.38,4608.5 h60
  text "Dielectric3" at 2716.29,4608.5 h60
  text "FR-4" at 3756,4608.5 h60
  text "5.20mil" at 4615.77,4608.5 h60
  text "4.8" at 5265.6,4608.5 h60
  text "11" at 2306.38,4488.5 h60
  text "Internal-Plane 5" at 2716.29,4488.5 h60
  text "Copper" at 3756,4488.5 h60
  text "1.40mil" at 4615.77,4488.5 h60
  text "12" at 2306.38,4368.5 h60
  text "Dielectric8" at 2716.29,4368.5 h60
  text "FR-4" at 3756,4368.5 h60
  text "5.20mil" at 4615.77,4368.5 h60
  text "4.8" at 5265.6,4368.5 h60
  text "13" at 2306.38,4248.5 h60
  text "Internal-Plane 6" at 2716.29,4248.5 h60
  text "Copper" at 3756,4248.5 h60
  text "1.40mil" at 4615.77,4248.5 h60
  text "14" at 2306.38,4128.5 h60
  text "Dielectric7" at 2716.29,4128.5 h60
  text "FR-4" at 3756,4128.5 h60
  text "5.20mil" at 4615.77,4128.5 h60
  text "4.8" at 5265.6,4128.5 h60
  text "15" at 2306.38,4008.5 h60
  text "Mid-Layer 7" at 2716.29,4008.5 h60
  text "Copper" at 3756,4008.5 h60
  text "1.40mil" at 4615.77,4008.5 h60
  text "16" at 2306.38,3888.5 h60
  text "Dielectric5" at 2716.29,3888.5 h60
  text "FR-4" at 3756,3888.5 h60
  text "5.20mil" at 4615.77,3888.5 h60
  text "4.8" at 5265.6,3888.5 h60
  text "17" at 2306.38,3768.5 h60
  text "Mid-Layer 8" at 2716.29,3768.5 h60
  text "Copper" at 3756,3768.5 h60
  text "1.40mil" at 4615.77,3768.5 h60
  text "18" at 2306.38,3648.5 h60
  text "Dielectric4" at 2716.29,3648.5 h60
  text "FR-4" at 3756,3648.5 h60
  text "5.20mil" at 4615.77,3648.5 h60
  text "4.8" at 5265.6,3648.5 h60
  text "19" at 2306.38,3528.5 h60
  text "Internal-Plane 9" at 2716.29,3528.5 h60
  text "Copper" at 3756,3528.5 h60
  text "1.40mil" at 4615.77,3528.5 h60
  text "20" at 2306.38,3408.5 h60
  text "Dielectric9" at 2716.29,3408.5 h60
  text "FR-4" at 3756,3408.5 h60
  text "5.20mil" at 4615.77,3408.5 h60
  text "4.8" at 5265.6,3408.5 h60
  text "21" at 2306.38,3288.5 h60
  text "Bottom Layer" at 2716.29,3288.5 h60
  text "Copper" at 3756,3288.5 h60
  text "1.40mil" at 4615.77,3288.5 h60
  text "22" at 2306.38,3168.5 h60
  text "Bottom Solder" at 2716.29,3168.5 h60
  text "Solder Resist" at 3756,3168.5 h60
  text "0.50mil" at 4615.77,3168.5 h60
  text "3.5" at 5265.6,3168.5 h60
  text "23" at 2306.38,3048.5 h60
  text "Bottom Overlay" at 2716.29,3048.5 h60
  text ".Layer_Name" at -3604.9,-2856.09 h60
M13 Component Bodies Top:
  text ".Layer_Name" at -3604.9,-2856.09 h60
M14 Component Bodies Bottom:
  text ".Layer_Name" at -3604.9,-2856.09 h60
M15 Courtyards Top:
  text ".Layer_Name" at -3604.9,-2856.09 h60
M16 Courtyards Bottom:
  text ".Layer_Name" at -3604.9,-2856.09 h60
Drill Drawing:
  circle w10: c3073.41,2274.33 r33.33
  lines w10: 2362.44,249.21 2172.34,249.21 2168.7,245.57 2168.7,114.83 ccw(c2207.7,114.97) 2231.22,83.86 2246.88,83.86 2247.22,84.2 2247.22,5.22 2247.6,4.84 2073.05,4.84 2070.04,1.83 2070.04,-230.98 2070.29,-231.23 1021.39,-231.23 1021.3,-231.15 1021.3,-34.16 ccw(c974.3,-34.16) 927.3,-34.16 927.34,-34.19 927.34,-230.61 927.59,-230.86 21.21,-230.86 21.09,-230.98 5.27,-230.98 5.14,-231.11 5.14,2.71 2.88,4.97 -172.17,4.97 -172.17,82.57 -171.91,82.83 -155.78,82.83 ccw(c-132.26,113.93) -93.3,115.84 -93.69,116.22 -93.69,223.46 -93.69,248.62 -284.81,248.62 -284.81,1974.27 -284.6,1974.07 2362.44,1974.07 2362.44,249.21 ; 2362.44,249.21 2362.44,249.21 ; 3040.07,2091 3106.74,2091 3106.74,2157.67 3040.07,2157.67 3040.07,2091 ; 3040.07,2391 3073.41,2407.67 3106.74,2391 3090.07,2424.33 3106.74,2457.67 3073.41,2441 3040.07,2457.67 3056.74,2424.33 3040.07,2391 ; 3040.07,2557.67 3056.74,2557.67 3073.41,2541 3090.07,2557.67 3106.74,2557.67 3090.07,2574.33 3106.74,2591 3090.07,2591 3073.41,2607.67 3056.74,2591 3040.07,2591 3056.74,2574.33 3040.07,2557.67
  lines w12: 2980.28,2046 6505.36,2046 ; 2980.28,2646 6505.36,2646 ; 3531.16,1896 3531.16,2796 ; 4121,1896 4121,2796 ; 5220.68,1896 5220.68,2796 ; 5726.56,1896 5726.56,2796 ; 2980.28,1896 6505.36,1896 6505.36,2796 2980.28,2796 2980.28,1896
  text "Symbol" at 3070.28,2691 h72
  text "Count" at 3576.16,2691 h72
  text "Hole Size" at 4166,2691 h72
  text "Plated" at 5265.68,2691 h72
  text "Hole Type" at 5771.56,2691 h72
  text "2" at 3576.16,2541 h60
  text "35.43mil (0.900mm)" at 4166,2541 h60
  text "NPTH" at 5265.68,2541 h60
  text "Round" at 5771.56,2541 h60
  text "8" at 3576.16,2391 h60
  text "35.04mil (0.890mm)" at 4166,2391 h60
  text "PTH" at 5265.68,2391 h60
  text "Round" at 5771.56,2391 h60
  text "9" at 3576.16,2241 h60
  text "25.00mil (0.635mm)" at 4166,2241 h60
  text "PTH" at 5265.68,2241 h60
  text "Round" at 5771.56,2241 h60
  text "493" at 3576.16,2091 h60
  text "8.00mil (0.203mm)" at 4166,2091 h60
  text "PTH" at 5265.68,2091 h60
  text "Round" at 5771.56,2091 h60
  text "512 Total" at 3576.16,1941 h60
  text ".Layer_Name" at -3604.9,-2856.09 h60
M17 Embedded Cavity:
  text ".Layer_Name" at -3604.9,-2856.09 h60
M18 Embedded Assembly:
  text ".Layer_Name" at -3604.9,-2856.09 h60
M19 Embedded Keepout:
  text ".Layer_Name" at -3604.9,-2856.09 h60

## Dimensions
1644,-261 to 2027,-656 on M2 Board Dimensions
-284.57,1974.1 to 5.17,-230.98 on M2 Board Dimensions
-284.78,248.72 to 2362.36,249.2 on M2 Board Dimensions
-4181.9,-2397.6 to -3181.9,-2397.6 on M2 Board Dimensions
